FUNCTION_BLOCK "fb_53_startstopDiesel"
TITLE =Control of a Diesel engine (Start, Stop, auxiliary functions)
//Version!Date    !Author !Segment    ! Description
//-------+--------+-------+-----------+-------------------------------
// 1.3   !07.04.00!Bauch  ! ---       ! Last valid version
// 1.4   !09.05.00!Kahle  ! 50        ! Shore conn on ->stop with load redu
// 1.5   !17.05.00!Kahle  ! 79        ! store failure "engine failure"
// 1.6   !15.09.00!Kahle  ! 49        ! stop if shore on in semi also
//       !        !       ! 50        ! stop if shore on with soft unload
//       !        !       ! 51        ! stop if shore on without soft unload
// 1.7   !16.12.00!Bauch  ! 65, new66 ! Generator breaker trip command
// 1.8   !03.01.01!Kahle  !27,28,29,74! monitoring prelub.press while start
//       !        !       !22,23,29   !
//       !        !       !22         ! corr. prelub. befor start
// 1.9   !11.01.01!Bauch  ! 8         ! Add. prelubrication in all modes
//       !        !       ! 12,24     ! Signal #stat_DG_Running moved from 12->24
// 1.10  !20.01.01!Bauch  ! 76        ! No blocking by signal "#out_Fail_Stop"
// 1.11  !24.01.01!Bauch  ! 29        ! Prelubrication before start
//       !        !       ! 27-->24   ! Prelubrication failure
//       !        !       ! 37        ! New signal "#stat_StartStep3Out"
//       !        !       ! 85        ! Function for "Start & Prelub"
//       !        !       ! Deklar.   ! Naming of "in_PrelubPress_Low",
//       !        !       !           ! "in_PrelubPress_OK"
// 1.12  !26.01.01!Bauch  ! new 90    ! Indication "Rated speed" for OP7
//       !        !       !           ! New variable "in_DI_RatedSpeed"
// 1.13  !31.01.01!Bauch  ! 22        ! Prelubrication Off with disappearing
//       !        !       !           ! of start request
// 1.14  !14.02.01!Kahle  ! 42        ! Delay time "volt.missing" adjustable
//       !        !       ! 45(new)   ! Create "delay stop pulse"
//       !        !       ! 80        ! Correction "engine available"
//       !        !       ! 82        ! Correction "creating engine failure"
// 1.15  !12.03.01!Kahle  ! 56        ! No cool down in case of delayed shutdown
// 2.0   !02.01.02!Kahle  ! 9-25,29,74! Prelubrication functionality is changed
//       !        !       ! 75        !
//       !        !       ! 52        ! Diesel stop in semiIMAC if CB open only
//       !        !       ! 77 ->29   ! Blocking criterion segment changed
//       !        !       ! 78        ! Out_blocked if diesel stopped only
//       !        !       ! 73        ! del.
//       !        !       !92-94 ->88f! move segm.92-94 ->88ff
//       !        !       ! 79        ! Standstill instead of standstill_delayed
AUTHOR : Bauch
FAMILY : PMA71
NAME : DiesCont
VERSION : 2.0
CODE_VERSION1


VAR_INPUT
  in_Nmb_Gen_LoadSh : INT ;	//Number of other generators, taking part in loadsharing
  in_act_mode : BYTE ;	//Active operation mode
  in_EG_set : BOOL ;	//Generator is an emergency generator
  in_DG_Start : BOOL ;	//Diesel generator start command
  in_DG_Stop : BOOL ;	//Diesel generator stop command
  in_UndelayStop : BOOL ;	//Diesel undelayed stop command (from diesel/generator protection, etc.)
  in_DelayStop : BOOL ;	//Diesel delayed stop command (from diesel/generator protection, etc.)
  in_EmergencyStop : BOOL ;	//Diesel emergency stop command
  in_Underload_Limit : BOOL ;	//Load below limit for underload shutdown
  in_Autom_Stop : BOOL ;	//Automatik stop (e.g. Underload shutdown command)
  in_Shore_Stop : BOOL ;	//Automatik stop from shore connection/external program
  in_DG_Load_Off : BOOL ;	//Load value below the diesel stop limit (->stop after manual load reduction)
  in_DI_GenBrk_FB_On : BOOL ;	//Feedback signal generator breaker is ON
  in_DI_GenBrk_FB_Off : BOOL ;	//Feedback signal generator breaker is OFF (for stop release)
  in_DI_IgnitionSpeed : BOOL ;	//Ignition speed
  in_DI_RatedSpeed : BOOL ;	//Rated speed
  in_GenVolt_avail : BOOL ;	//Generator voltage available (Standard: >85%)
  in_MonitTime1 : BOOL ;	//Monitoring time 1
  in_DG_Block_Engine : BOOL ;	//Diesel engine blocked (signal from engine/local panel; "1"=blocked)
  in_DG_Blocking : BOOL ;	//Conditions for blocking of diesel generator
  in_Blocking_Reset : BOOL ;	//Blocking reset
  in_LubPress : BOOL ;	//Lubrication oil pressure available
  in_PrelubPress : BOOL ;	//Lubrication oil pressure available
  in_DRelStdby : BOOL ;	//Release standby function
  in_Blackout : BOOL ;	//Blackout
  in_NoWireBrk_StartValve : BOOL ;	//No wire breakage start valve (digital input)
  in_NoWireBrk_StopValve : BOOL ;	//No wire breakage stop valve (digital input)
  in_NoWireBrk_EmStopValve : BOOL ;	//No wire breakage emergency stop valve (digital input)
  in_NoWireBrk_SupprValve : BOOL ;	//No wire breakage suppression valve (digital input)
  in_Reset : BOOL ;	//Reset
END_VAR
VAR_OUTPUT
  out_Operat_Status : INT ;	//Actual operational status (as number)
  out_StartValve : BOOL ;	//Start valve
  out_StopValve : BOOL ;	//Stop valve
  out_EmStpValve : BOOL ;	//Emergency stop valve
  out_SupprValve : BOOL ;	//Suppression valve
  out_Release_SpeedContr : BOOL ;	//Release of speed controller
  out_PreLub : BOOL ;	//Prelubrication
  out_PreHeat : BOOL ;	//Preheating
  out_SlowTurn : BOOL ;	//Slow Turn
  out_StandbyStart : BOOL ;	//Request of standby start
  out_ChOver_Semi : BOOL ;	//Forced change over from automatic to semi automatic mode
  out_GenBrkOff_LoadRed : BOOL ;	//Generator breaker Off after load reduction (Off after P < Limit)
  out_GenBrkOff : BOOL ;	//Generator breaker Off command (without previous load reduction)
  out_GenBrkTrip : BOOL ;	//Generator breaker trip command
  out_DG_Blocked_Fault : BOOL ;	//Diesel generator blocked by fault
  out_DG_Blocked : BOOL ;	//Diesel generator blocked
  out_DG_Starting : BOOL ;	//Diesel generator starting
  out_DG_Runn : BOOL ;	//Diesel generator running
  out_DG_Avail : BOOL ;	//Diesel generator available
  out_Fail_Start : BOOL ;	//Start failure
  out_Fail_Stop : BOOL ;	//Stop failure
  out_Fail_IgnSpd : BOOL ;	//Signal "Ignition speed" missing, but "Gen. voltage available"
  out_Fail_GenVolt : BOOL ;	//Signal "Gen. voltage available" missing, but "Ignition speed"
  out_Fail_UndelayStop : BOOL ;	//Indication "Undelayed stop"
  out_Fail_DelayStop : BOOL ;	//Indication "Delayed stop"
  out_Fail_DieselEngine : BOOL ;	//Indication "Diesel engine failure"
  out_Fail_PrelubOil : BOOL ;	//Indication "Low prelubrication oil pressure" (Diesel engine start blocking)
  out_Fail_LubOil : BOOL ;	//Indication "Low lubrication oil pressure"
  out_Fail_WBr_StartValve : BOOL ;	//Indication "Wire breakage start valve"
  out_Fail_WBr_StopValve : BOOL ;	//Indication "Wire breakage stop valve"
  out_Fail_WBr_EmStopValve : BOOL ;	//Indication "Wire breakage emergency stop valve"
  out_Fail_WBr_SuppValve : BOOL ;	//Indication "Wire breakage suppression valve"
END_VAR
VAR
  stat_CountStAtt : INT ;	//Down-counter for start attempts
  stat_Nmb_Gen_LoadSh_Old : INT ;	//Number of other generators, taking part in loadsharing (old value)
  stat_CntValue01 : INT ;	//Memory for FC100 (timer/counter) No. 01 (Prelubr. before start necessary)
  stat_CntValue02 : INT ;	//Memory for FC100 (timer/counter) No. 02 (Prelub bef. start, prelub time)
  stat_CntValue03 : INT ;	//Memory for FC100 (timer/counter) No. 03 (Suppression valve)
  stat_CntValue04 : INT ;	//Memory for FC100 (timer/counter) No. 04 (Stopping time after ign. speed Off)
  stat_CntValue05 : INT ;	//Memory for FC100 (timer/counter) No. 05 (Time for delayed shutdown)
  stat_CntValue06 : INT ;	//Memory for FC100 (timer/counter) No. 06 (Cool down time)
  stat_CntValue07 : INT ;	//Memory for FC100 (timer/counter) No. 07 (Time for load reduction)
  stat_CntValue08 : INT ;	//Memory for FC100 (timer/counter) No. 08 (p_TManLoadRed)
  stat_CntValue09 : INT ;	//Memory for FC100 (timer/counter) No. 09 (Failure Ign. speed missing)
  stat_CntValue10 : INT ;	//Memory for FC100 (timer/counter) No. 10 (Failure Gen. voltage missing)
  stat_CntValue11 : INT ;	//Memory for FC100 (timer/counter) No. 11 (Low prelub oil press.)
  stat_CntValue12 : INT ;	//Memory for FC100 (timer/counter) No. 12 (Ignition speed is Off)
  stat_CntValue13 : INT ;	//Memory for FC100 (timer/counter) No. 13 (Wire breakage start valve)
  stat_CntValue14 : INT ;	//Memory for FC100 (timer/counter) No. 14 (Wire breakage stop valve)
  stat_CntValue15 : INT ;	//Memory for FC100 (timer/counter) No. 15 (Wire breakage emergency stop valve)
  stat_CntValue16 : INT ;	//Memory for FC100 (timer/counter) No. 16 (Wire breakage suppression valve)
  stat_CntValue17 : INT ;	//Memory for FC100 (timer/counter) No. 17 (Monitoring time for stop failure)
  stat_CntValue18 : INT ;	//Memory for FC100 (timer/counter) No. 18 (Waiting time before diesel start)
  stat_CntValue19 : INT ;	//Memory for FC100 (timer/counter) No. 19 (Monitoring time luboil after start)
  stat_CntStart01 : BOOL ;	//Memory for FC100 (timer/counter) No. 01
  stat_CntStarted01 : BOOL ;	//Memory for FC100 (timer/counter) No. 01
  stat_CntStart02 : BOOL ;	//Memory for FC100 (timer/counter) No. 02
  stat_CntStarted02 : BOOL ;	//Memory for FC100 (timer/counter) No. 02
  stat_CntStart03 : BOOL ;	//Memory for FC100 (timer/counter) No. 03
  stat_CntStarted03 : BOOL ;	//Memory for FC100 (timer/counter) No. 03
  stat_CntStart04 : BOOL ;	//Memory for FC100 (timer/counter) No. 04
  stat_CntStarted04 : BOOL ;	//Memory for FC100 (timer/counter) No. 04
  stat_CntStart05 : BOOL ;	//Memory for FC100 (timer/counter) No. 05
  stat_CntStarted05 : BOOL ;	//Memory for FC100 (timer/counter) No. 05
  stat_CntStart06 : BOOL ;	//Memory for FC100 (timer/counter) No. 06
  stat_CntStarted06 : BOOL ;	//Memory for FC100 (timer/counter) No. 06
  stat_CntStart07 : BOOL ;	//Memory for FC100 (timer/counter) No. 07
  stat_CntStarted07 : BOOL ;	//Memory for FC100 (timer/counter) No. 07
  stat_CntStart08 : BOOL ;	//Memory for FC100 (timer/counter) No. 08
  stat_CntStarted08 : BOOL ;	//Memory for FC100 (timer/counter) No. 08
  stat_CntStart09 : BOOL ;	//Memory for FC100 (timer/counter) No. 09
  stat_CntStarted09 : BOOL ;	//Memory for FC100 (timer/counter) No. 09
  stat_CntStart10 : BOOL ;	//Memory for FC100 (timer/counter) No. 10
  stat_CntStarted10 : BOOL ;	//Memory for FC100 (timer/counter) No. 10
  stat_CntStart11 : BOOL ;	//Memory for FC100 (timer/counter) No. 11
  stat_CntStarted11 : BOOL ;	//Memory for FC100 (timer/counter) No. 11
  stat_CntStart12 : BOOL ;	//Memory for FC100 (timer/counter) No. 12
  stat_CntStarted12 : BOOL ;	//Memory for FC100 (timer/counter) No. 12
  stat_CntStart13 : BOOL ;	//Memory for FC100 (timer/counter) No. 13
  stat_CntStarted13 : BOOL ;	//Memory for FC100 (timer/counter) No. 13
  stat_CntStart14 : BOOL ;	//Memory for FC100 (timer/counter) No. 14
  stat_CntStarted14 : BOOL ;	//Memory for FC100 (timer/counter) No. 14
  stat_CntStart15 : BOOL ;	//Memory for FC100 (timer/counter) No. 15
  stat_CntStarted15 : BOOL ;	//Memory for FC100 (timer/counter) No. 15
  stat_CntStart16 : BOOL ;	//Memory for FC100 (timer/counter) No. 16
  stat_CntStarted16 : BOOL ;	//Memory for FC100 (timer/counter) No. 16
  stat_CntStart17 : BOOL ;	//Memory for FC100 (timer/counter) No. 17
  stat_CntStarted17 : BOOL ;	//Memory for FC100 (timer/counter) No. 17
  stat_CntStart18 : BOOL ;	//Memory for FC100 (timer/counter) No. 18
  stat_CntStarted18 : BOOL ;	//Memory for FC100 (timer/counter) No. 18
  stat_CntStart19 : BOOL ;	//Memory for FC100 (timer/counter) No. 19
  stat_CntStarted19 : BOOL ;	//Memory for FC100 (timer/counter) No. 19
  stat_StartRequ : BOOL ;	//Diesel start request
  stat_StartBegin : BOOL ;	//Diesel start beginning
  stat_StartBegPulse : BOOL ;	//Diesel start beginning, pulse 0-->1
  stat_StartStep1Out : BOOL ;	//Diesel start, step 1 output (intermediate step)
  stat_StartStep1Fin : BOOL ;	//Diesel start, step 1 finished (intermediate step)
  stat_StartStep2Cond : BOOL ;	//Diesel start, condition for step 2 (start valve active)
  stat_StartStep2Fin : BOOL ;	//Diesel start, step 2 finished (start valve active)
  stat_StartValve : BOOL ;	//Start valve active
  stat_StartStep3Out : BOOL ;	//Diesel start, step 3 output (pause between start attempts)
  stat_StartStep3Fin : BOOL ;	//Diesel start, step 3 finished (pause between start attempts)
  stat_DG_Stop : BOOL ;	//Diesel generator stop command
  stat_DelayStopRequ_Latch : BOOL ;	//Diesel delayed stop request (caused by a failure), latch
  stat_DelayStop_TimeEx : BOOL ;	//Diesel delayed stop, time expired
  stat_Standby_Conn : BOOL ;	//New started standby set has been connected to the busbar, pulse
  stat_Stop_Shore : BOOL ;	//Automatic stop from shore connection/external program
  stat_StopLoadRed_Latch : BOOL ;	//Diesel stop request with previous load reduction, latch
  stat_StopNoLoadRed_Latch : BOOL ;	//Diesel stop request without previous load reduction, latch
  stat_Stop_CoolDown : BOOL ;	//Diesel stop request, engine running for cool down
  stat_Stop_CoolDownEx : BOOL ;	//Diesel stop request, after time for cool down has expired
  stat_Stop_EG_NoLoadRun : BOOL ;	//Diesel stop request, with previous cool down/no load run function (for EG)
  stat_Stop_BreakOff : BOOL ;	//Diesel stop request, after time for generator breaker Off has expired
  stat_StopRequ_Pulse : BOOL ;	//Diesel stop request, pulse
  stat_StopRequ_Latch : BOOL ;	//Diesel stop request, latch
  stat_StopDelay : BOOL ;	//Diesel stop command delayed Off after "Ignition speed" and "Gen. volt." is Off
  stat_StopGoing : BOOL ;	//Diesel stop procedure going on
  stat_DG_Standstill : BOOL ;	//Diesel engine standstill
  stat_DG_Standstill_Delay : BOOL ;	//Diesel engine standstill, Off-delayed
  stat_DiesStarting_Aux : BOOL ;	//Diesel engine starting, auxiliary
  stat_DiesStarting_Pulse : BOOL ;	//Diesel engine starting, pulse
  stat_DG_Running : BOOL ;	//Diesel generator running ("Ignition speed" or "Generator voltage" present)
  stat_DG_Block_Fault : BOOL ;	//Diesel engine blocked by fault
  stat_PreLAct : BOOL ;	//Prelubrication active (Standby, Auto, etc.)
  stat_PreLContMode : BOOL ;	//Mode with constant prelubrication active
  stat_PreLCyclMode : BOOL ;	//Mode with cyclic prelubrication active
  stat_PreLStartMode : BOOL ;	//Mode with prelubrication before diesel start active
  stat_PreLContOn : BOOL ;	//Constant prelubrication On
  stat_PreLCyclOn : BOOL ;	//Cyclic prelubrication On
  stat_PreLPump : BOOL ;	//Prelubrication pump running also after diesel start
  stat_PreLCyStep0Cond : BOOL ;	//Cyclic prelubrication, condition for sequence start
  stat_PreLCyStep1 : BOOL ;	//Cyclic prelubrication, condition for step 1 (intermediate step)
  stat_PreLCyStep1Fin : BOOL ;	//Cyclic prelubrication, step 1 finished (intermediate step)
  stat_PreLCyStep2Cond : BOOL ;	//Cyclic prelubrication, condition for step 2 (pause)
  stat_PreLCyStep2Fin : BOOL ;	//Cyclic prelubrication, step 2 finished (pause)
  stat_PreLCyStep3Out : BOOL ;	//Cyclic prelubrication, step 3 output (prelubrication)
  stat_PreLCyStep3Fin : BOOL ;	//Cyclic prelubrication, step 3 finished (intermediate step)
  stat_PreLStNBegin : BOOL ;	//Prelubrication before start necessity, delay time starts
  stat_PreLStNReady : BOOL ;	//Prelubrication before start necessity, prelubrication necessary
  stat_PreLStBegin : BOOL ;	//Prelubrication before start beginning
  stat_PreLlowPress : BOOL ;	//Prelubrication: failure low pressure (time exceeded)
  stat_SuppValvRequOff : BOOL ;	//Suppression valve, delayed Off request
  stat_PrelPress_Delay : BOOL ;	//"Low prelubrication oil pressure", time delayed
  stat_PrelPress_Blocking : BOOL ;	//Diesel engine blocking, caused by "Low prelubrication oil pressure"
  stat_IgnSpeedOff_Delay : BOOL ;	//Signal "Ignition speed is Off", time delayed
  stat_IgnSpeedOff_Aux : BOOL ;	//Auxiliary flag for pulse "Ignition speed is Off"
  stat_Fail_DieselEngine : BOOL ;	//Memory: Engine failure
  stat_DG_Running2 : BOOL ;	//Memory: Engine running
  stat_DelayStop : BOOL ;	//Pulse delay stop
  stat_failLubPress : BOOL ;	//Failure Lubrication pressure after start
END_VAR
VAR_TEMP
  temp_OM_Local : BOOL ;	//Active operation mode: Local
  temp_OM_Semi_OP : BOOL ;	//Active operation mode: Semi automatic OP
  temp_OM_Auto_OP : BOOL ;	//Active operation mode: Auto OP
  temp_OM_Semi_MMI : BOOL ;	//Active operation mode: Semi automatic MMI
  temp_OM_Auto_MMI : BOOL ;	//Active operation mode: Auto MMI
  temp_OM_Test : BOOL ;	//Active operation mode: Test (EG only)
  temp_Reserve_006 : BOOL ;	//Reserved (Transfer Byte --> Bit)
  temp_Reserve_007 : BOOL ;	//Reserved (Transfer Byte --> Bit)
  temp_Auto : BOOL ;	//Active operation mode: Auto
  temp_Semi : BOOL ;	//Active operation mode: Semi automatic
  temp_ScratchFlag : BOOL ;	//Scratch flag
  temp_StartStep2Fin : BOOL ;	//Diesel start, step 2 finished (start valve active)
  temp_StartStep3Fin : BOOL ;	//Diesel start, step 3 finished (pause between start attempts)
  temp_Standby_Start : BOOL ;	//Standby start command
  temp_lastSet : BOOL ;	//This set is the last one in load balance
  temp_automLoadRed : BOOL ;	//Mode "Automatic load reduction" is active
  temp_manLoadRed : BOOL ;	//Mode "Manual load reduction" is active
  temp_Fail_Stop : BOOL ;	//Stop failure
  temp_Fail_PreLub : BOOL ;	//Prelubrication failure
  temp_Pls_DelayStop : BOOL ;	//positive pulse delay stop
  temp_DelayStop : BOOL ;	//delay stop activated
  temp_PreLub : BOOL ;	//prelubrication is activated
  temp_startDiesel : BOOL ;	//start diesel if prelubrication time is exceeded
END_VAR
BEGIN
NETWORK
TITLE =Active operation mode (Transfer Byte --> Bit)
//This transfer function is relaying on the relative addresses of the "temp"
//variables "temp_OM_Local" ... "temp_OM_Auto" in the area from 0.0 ... 0.7.
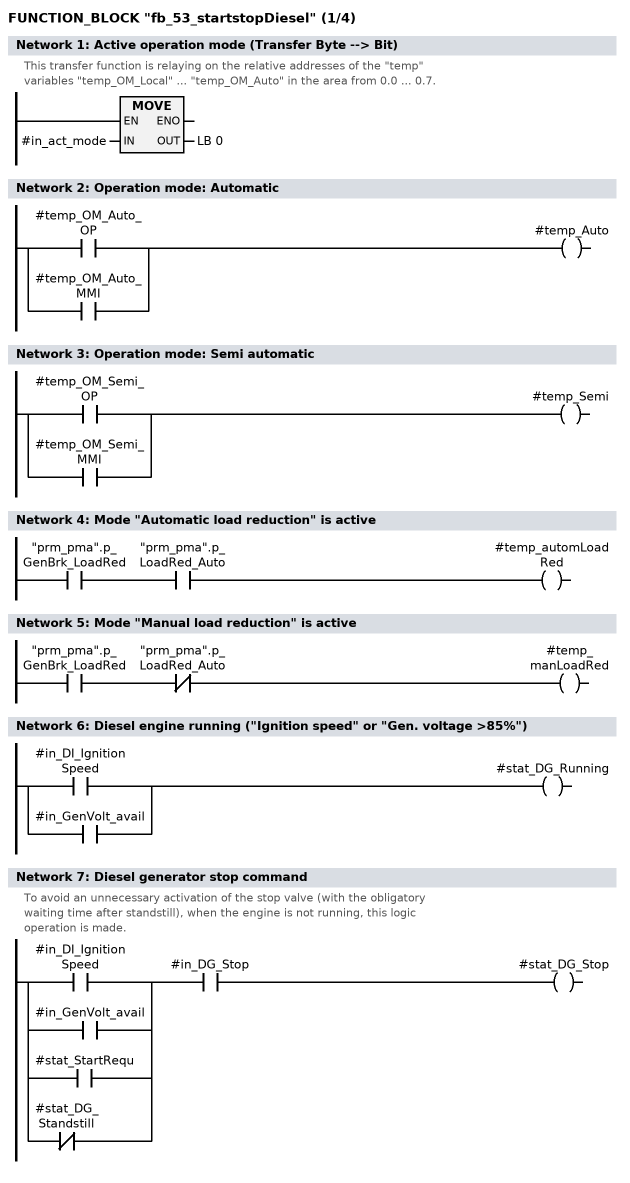
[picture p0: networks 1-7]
      L     #in_act_mode;
      T     LB     0;
NETWORK
TITLE =Operation mode: Automatic

      O     #temp_OM_Auto_OP;
      O     #temp_OM_Auto_MMI;
      =     #temp_Auto;
NETWORK
TITLE =Operation mode: Semi automatic

      O     #temp_OM_Semi_OP;
      O     #temp_OM_Semi_MMI;
      =     #temp_Semi;
NETWORK
TITLE =Mode "Automatic load reduction" is active

      U     "prm_pma".p_GenBrk_LoadRed;
      U     "prm_pma".p_LoadRed_Auto;
      =     #temp_automLoadRed;
NETWORK
TITLE =Mode "Manual load reduction" is active

      U     "prm_pma".p_GenBrk_LoadRed;
      UN    "prm_pma".p_LoadRed_Auto;
      =     #temp_manLoadRed;
NETWORK
TITLE =Diesel engine running ("Ignition speed" or "Gen. voltage >85%")

      O     #in_DI_IgnitionSpeed;
      O     #in_GenVolt_avail;
      =     #stat_DG_Running;
NETWORK
TITLE =Diesel generator stop command
//To avoid an unnecessary activation of the stop valve (with the obligatory
//waiting time after standstill), when the engine is not running, this logic
//operation is made.
      U(    ;
      O     #in_DI_IgnitionSpeed;
      O     #in_GenVolt_avail;
      O     #stat_StartRequ;
      ON    #stat_DG_Standstill;
      )     ;
      U     #in_DG_Stop;
      =     #stat_DG_Stop;
NETWORK
TITLE =Prelubrication active (with standby, auto, etc.)

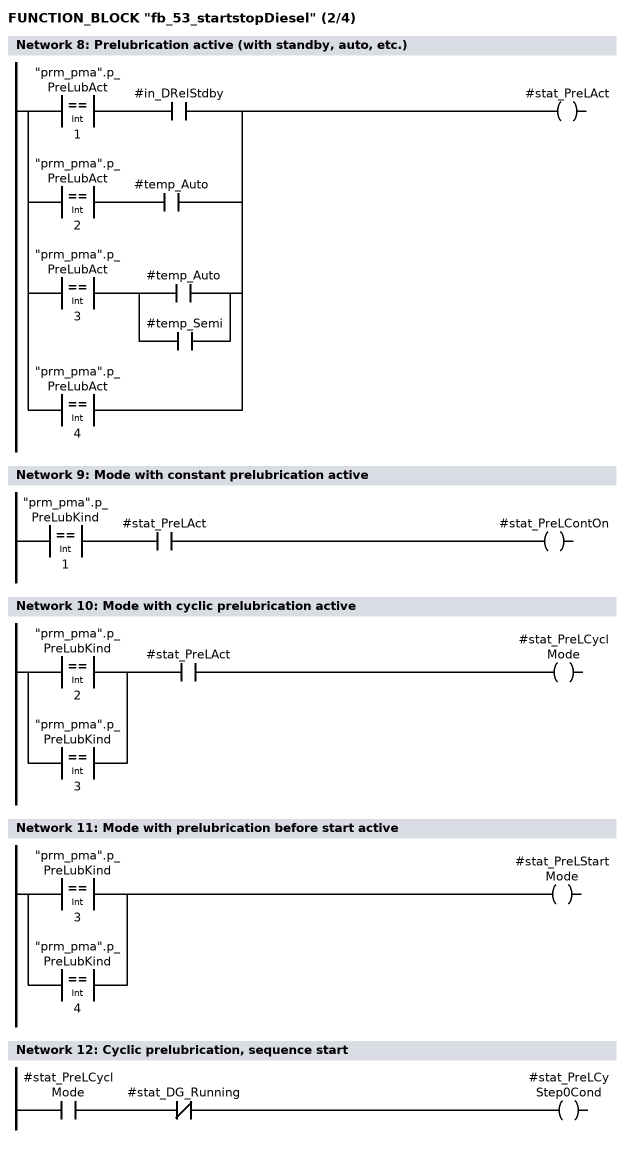
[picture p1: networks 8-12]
      U(    ;
      L     "prm_pma".p_PreLubAct;
      L     1;
      ==I   ;
      )     ;
      U     #in_DRelStdby;
      O     ;
      U(    ;
      L     "prm_pma".p_PreLubAct;
      L     2;
      ==I   ;
      )     ;
      U     #temp_Auto;
      O     ;
      U(    ;
      L     "prm_pma".p_PreLubAct;
      L     3;
      ==I   ;
      )     ;
      U(    ;
      O     #temp_Auto;
      O     #temp_Semi;
      )     ;
      O(    ;
      L     "prm_pma".p_PreLubAct;
      L     4;
      ==I   ;
      )     ;
      =     #stat_PreLAct;
NETWORK
TITLE =Mode with constant prelubrication active

      U(    ;
      L     "prm_pma".p_PreLubKind;
      L     1;
      ==I   ;
      )     ;
      U     #stat_PreLAct;
      =     #stat_PreLContOn;
NETWORK
TITLE =Mode with cyclic prelubrication active

      U(    ;
      O(    ;
      L     "prm_pma".p_PreLubKind;
      L     2;
      ==I   ;
      )     ;
      O(    ;
      L     "prm_pma".p_PreLubKind;
      L     3;
      ==I   ;
      )     ;
      )     ;
      U     #stat_PreLAct;
      =     #stat_PreLCyclMode;
NETWORK
TITLE =Mode with prelubrication before start active

      O(    ;
      L     "prm_pma".p_PreLubKind;
      L     3;
      ==I   ;
      )     ;
      O(    ;
      L     "prm_pma".p_PreLubKind;
      L     4;
      ==I   ;
      )     ;
      =     #stat_PreLStartMode;
NETWORK
TITLE =Cyclic prelubrication, sequence start

      U     #stat_PreLCyclMode;
      UN    #stat_DG_Running;
      =     #stat_PreLCyStep0Cond;
NETWORK
TITLE =NW13 -17: Cyclic prelubrication, sequence start
//The sequence starts with the stopping of the engine ("Ignition speed" and
//"Generator voltage" Off), when cyclic prelubrication is selected.
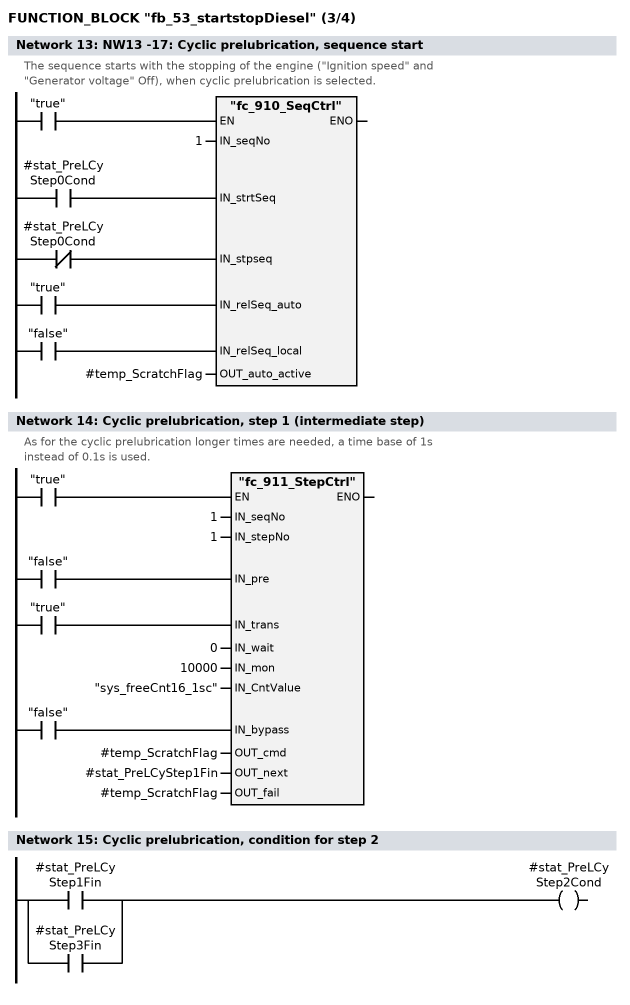
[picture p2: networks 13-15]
      U     #stat_PreLCyStep0Cond;
      =     L      3.0;
      BLD   103;
      UN    #stat_PreLCyStep0Cond;
      =     L      3.1;
      BLD   103;
      U     "true";
      =     L      3.2;
      BLD   103;
      U     "false";
      =     L      3.3;
      BLD   103;
      U     "true";
      SPBNB _00b;
      CALL "fc_910_SeqCtrl" (
           IN_seqNo                 := 1,
           IN_strtSeq               := L      3.0,
           IN_stpseq                := L      3.1,
           IN_relSeq_auto           := L      3.2,
           IN_relSeq_local          := L      3.3,
           OUT_auto_active          := #temp_ScratchFlag);
_00b: NOP   0;
NETWORK
TITLE =Cyclic prelubrication, step 1 (intermediate step)
//As for the cyclic prelubrication longer times are needed, a time base of 1s
//instead of 0.1s is used.
      U     "false";
      =     L      3.0;
      BLD   103;
      U     "true";
      =     L      3.1;
      BLD   103;
      U     "false";
      =     L      3.2;
      BLD   103;
      U     "true";
      SPBNB _00f;
      CALL "fc_911_StepCtrl" (
           IN_seqNo                 := 1,
           IN_stepNo                := 1,
           IN_pre                   := L      3.0,
           IN_trans                 := L      3.1,
           IN_wait                  := 0,
           IN_mon                   := 10000,
           IN_CntValue              := "sys_freeCnt16_1sc",
           IN_bypass                := L      3.2,
           OUT_cmd                  := #temp_ScratchFlag,
           OUT_next                 := #stat_PreLCyStep1Fin,
           OUT_fail                 := #temp_ScratchFlag);
_00f: NOP   0;
NETWORK
TITLE =Cyclic prelubrication, condition for step 2

      O     #stat_PreLCyStep1Fin;
      O     #stat_PreLCyStep3Fin;
      =     #stat_PreLCyStep2Cond;
NETWORK
TITLE =Cyclic prelubrication, step 2 (pause)
//As for the cyclic prelubrication longer times are needed, a time base of 1s
//instead of 0.1s is used.
//
//During standstill of the diesel engine the sequence moves between steps 2 and
//3.
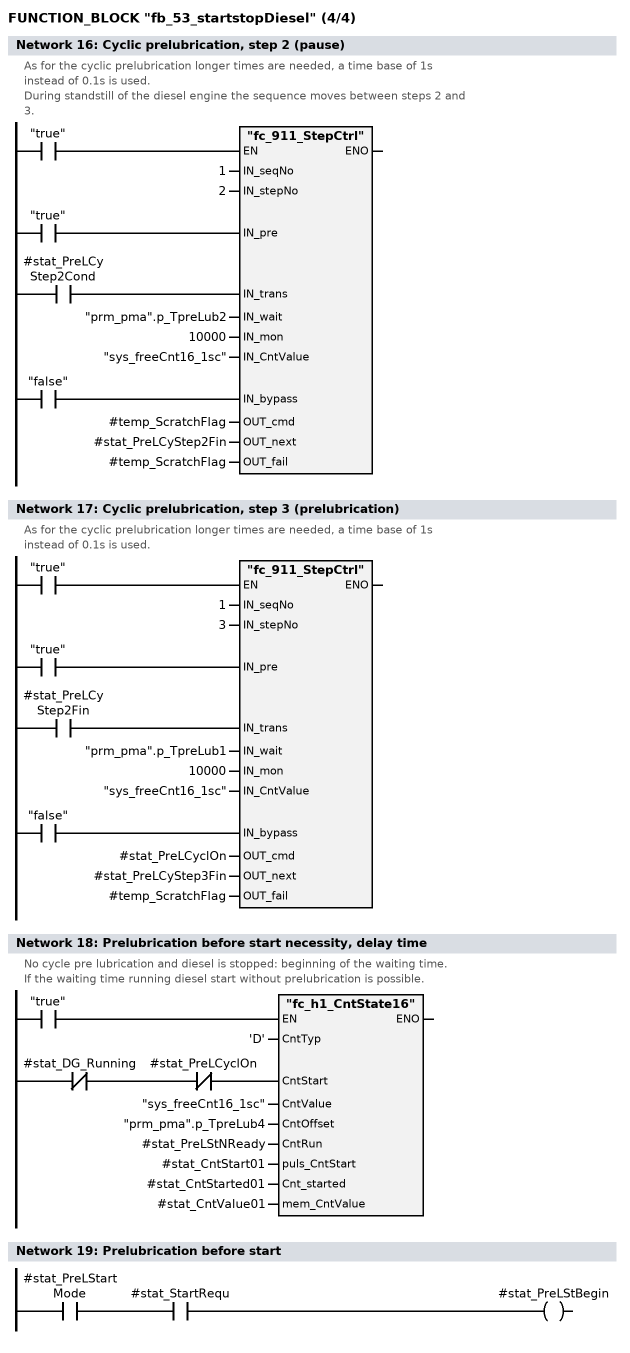
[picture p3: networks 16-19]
      U     "true";
      =     L      3.0;
      BLD   103;
      U     #stat_PreLCyStep2Cond;
      =     L      3.1;
      BLD   103;
      U     "false";
      =     L      3.2;
      BLD   103;
      U     "true";
      SPBNB _013;
      CALL "fc_911_StepCtrl" (
           IN_seqNo                 := 1,
           IN_stepNo                := 2,
           IN_pre                   := L      3.0,
           IN_trans                 := L      3.1,
           IN_wait                  := "prm_pma".p_TpreLub2,
           IN_mon                   := 10000,
           IN_CntValue              := "sys_freeCnt16_1sc",
           IN_bypass                := L      3.2,
           OUT_cmd                  := #temp_ScratchFlag,
           OUT_next                 := #stat_PreLCyStep2Fin,
           OUT_fail                 := #temp_ScratchFlag);
_013: NOP   0;
NETWORK
TITLE =Cyclic prelubrication, step 3 (prelubrication)
//As for the cyclic prelubrication longer times are needed, a time base of 1s
//instead of 0.1s is used.
      U     "true";
      =     L      3.0;
      BLD   103;
      U     #stat_PreLCyStep2Fin;
      =     L      3.1;
      BLD   103;
      U     "false";
      =     L      3.2;
      BLD   103;
      U     "true";
      SPBNB _01c;
      CALL "fc_911_StepCtrl" (
           IN_seqNo                 := 1,
           IN_stepNo                := 3,
           IN_pre                   := L      3.0,
           IN_trans                 := L      3.1,
           IN_wait                  := "prm_pma".p_TpreLub1,
           IN_mon                   := 10000,
           IN_CntValue              := "sys_freeCnt16_1sc",
           IN_bypass                := L      3.2,
           OUT_cmd                  := #stat_PreLCyclOn,
           OUT_next                 := #stat_PreLCyStep3Fin,
           OUT_fail                 := #temp_ScratchFlag);
_01c: NOP   0;
NETWORK
TITLE =Prelubrication before start necessity, delay time
//No cycle pre lubrication and diesel is stopped: beginning of the waiting time.
//If the waiting time running diesel start without prelubrication is possible.
      UN    #stat_DG_Running;
      UN    #stat_PreLCyclOn;
      =     L      3.0;
      BLD   103;
      U     "true";
      SPBNB _01d;
      CALL "fc_h1_CntState16" (
           CntTyp                   := 'D',
           CntStart                 := L      3.0,
           CntValue                 := "sys_freeCnt16_1sc",
           CntOffset                := "prm_pma".p_TpreLub4,
           CntRun                   := #stat_PreLStNReady,
           puls_CntStart            := #stat_CntStart01,
           Cnt_started              := #stat_CntStarted01,
           mem_CntValue             := #stat_CntValue01);
_01d: NOP   0;
NETWORK
TITLE =Prelubrication before start

      U     #stat_PreLStartMode;
      U     #stat_StartRequ;
      =     #stat_PreLStBegin;
NETWORK
TITLE =Prelubrication output

      U(    ;
      O     #stat_PreLContOn;
      O     ;
      U     #stat_PreLCyclOn;
      UN    #stat_PreLStNReady;
      O     #stat_PreLStBegin;
      )     ;
      UN    #stat_DG_Running;
      O(    ;
      U     #stat_PreLStBegin;
      U     "prm_pma".p_PrelubOil_Blackout;
      S     #stat_PreLPump;
      U(    ;
      O     #in_LubPress;
      O     #stat_PreLlowPress;
      O     #stat_failLubPress;
      )     ;
      R     #stat_PreLPump;
      U     #stat_PreLPump;
      )     ;
      =     #out_PreLub;
NETWORK
TITLE =Monitoring Prelubrication before start

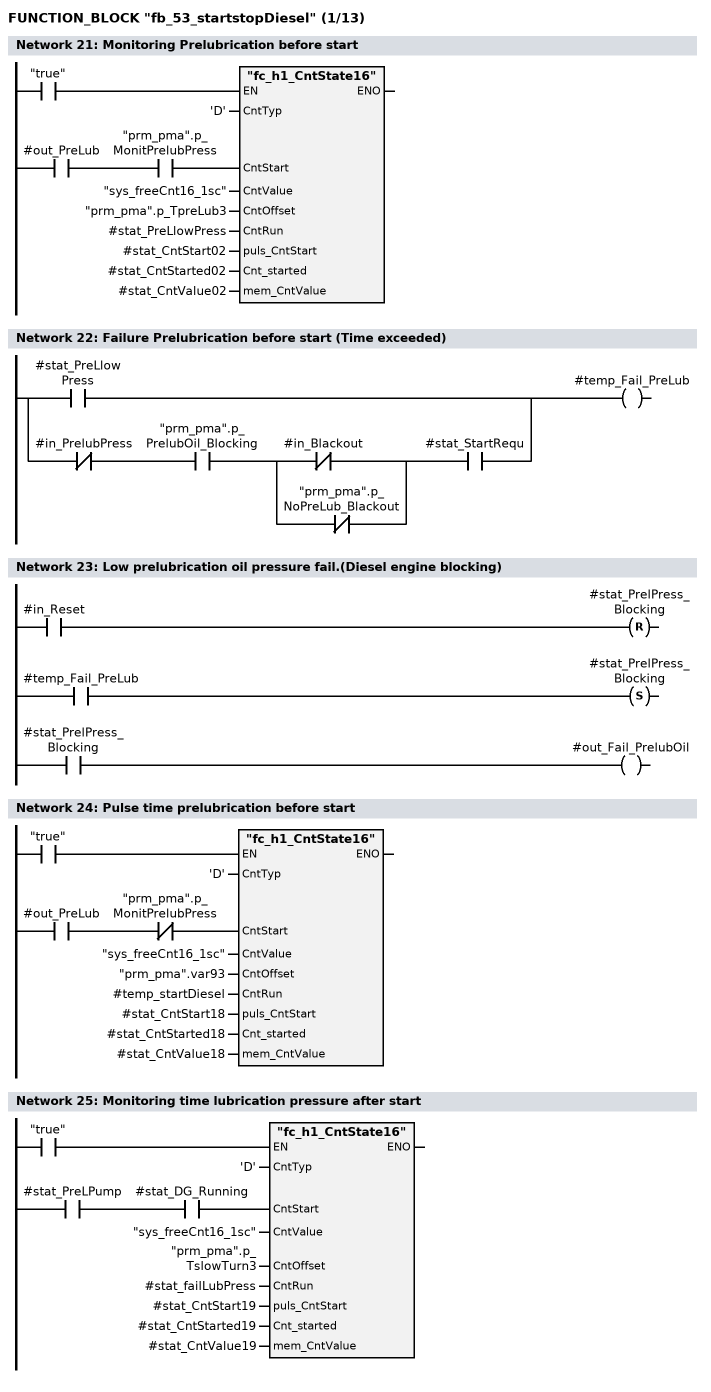
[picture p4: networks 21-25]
      U     #out_PreLub;
      U     "prm_pma".p_MonitPrelubPress;
      =     L      3.0;
      BLD   103;
      U     "true";
      SPBNB _01e;
      CALL "fc_h1_CntState16" (
           CntTyp                   := 'D',
           CntStart                 := L      3.0,
           CntValue                 := "sys_freeCnt16_1sc",
           CntOffset                := "prm_pma".p_TpreLub3,
           CntRun                   := #stat_PreLlowPress,
           puls_CntStart            := #stat_CntStart02,
           Cnt_started              := #stat_CntStarted02,
           mem_CntValue             := #stat_CntValue02);
_01e: NOP   0;
NETWORK
TITLE =Failure Prelubrication before start (Time exceeded)

      O     #stat_PreLlowPress;
      O     ;
      UN    #in_PrelubPress;
      U     "prm_pma".p_PrelubOil_Blocking;
      U(    ;
      ON    #in_Blackout;
      ON    "prm_pma".p_NoPreLub_Blackout;
      )     ;
      U     #stat_StartRequ;
      =     #temp_Fail_PreLub;
NETWORK
TITLE =Low prelubrication oil pressure fail.(Diesel engine blocking)

      U     #in_Reset;
      R     #stat_PrelPress_Blocking;
      U     #temp_Fail_PreLub;
      S     #stat_PrelPress_Blocking;
      U     #stat_PrelPress_Blocking;
      =     #out_Fail_PrelubOil;
NETWORK
TITLE =Pulse time prelubrication before start

      U     #out_PreLub;
      UN    "prm_pma".p_MonitPrelubPress;
      =     L      3.0;
      BLD   103;
      U     "true";
      SPBNB _01f;
      CALL "fc_h1_CntState16" (
           CntTyp                   := 'D',
           CntStart                 := L      3.0,
           CntValue                 := "sys_freeCnt16_1sc",
           CntOffset                := "prm_pma".var93,
           CntRun                   := #temp_startDiesel,
           puls_CntStart            := #stat_CntStart18,
           Cnt_started              := #stat_CntStarted18,
           mem_CntValue             := #stat_CntValue18);
_01f: NOP   0;
NETWORK
TITLE =Monitoring time lubrication pressure after start

      U     #stat_PreLPump;
      U     #stat_DG_Running;
      =     L      3.0;
      BLD   103;
      U     "true";
      SPBNB _022;
      CALL "fc_h1_CntState16" (
           CntTyp                   := 'D',
           CntStart                 := L      3.0,
           CntValue                 := "sys_freeCnt16_1sc",
           CntOffset                := "prm_pma".p_TslowTurn3,
           CntRun                   := #stat_failLubPress,
           puls_CntStart            := #stat_CntStart19,
           Cnt_started              := #stat_CntStarted19,
           mem_CntValue             := #stat_CntValue19);
_022: NOP   0;
NETWORK
TITLE =failure: low lubrication oil pressure

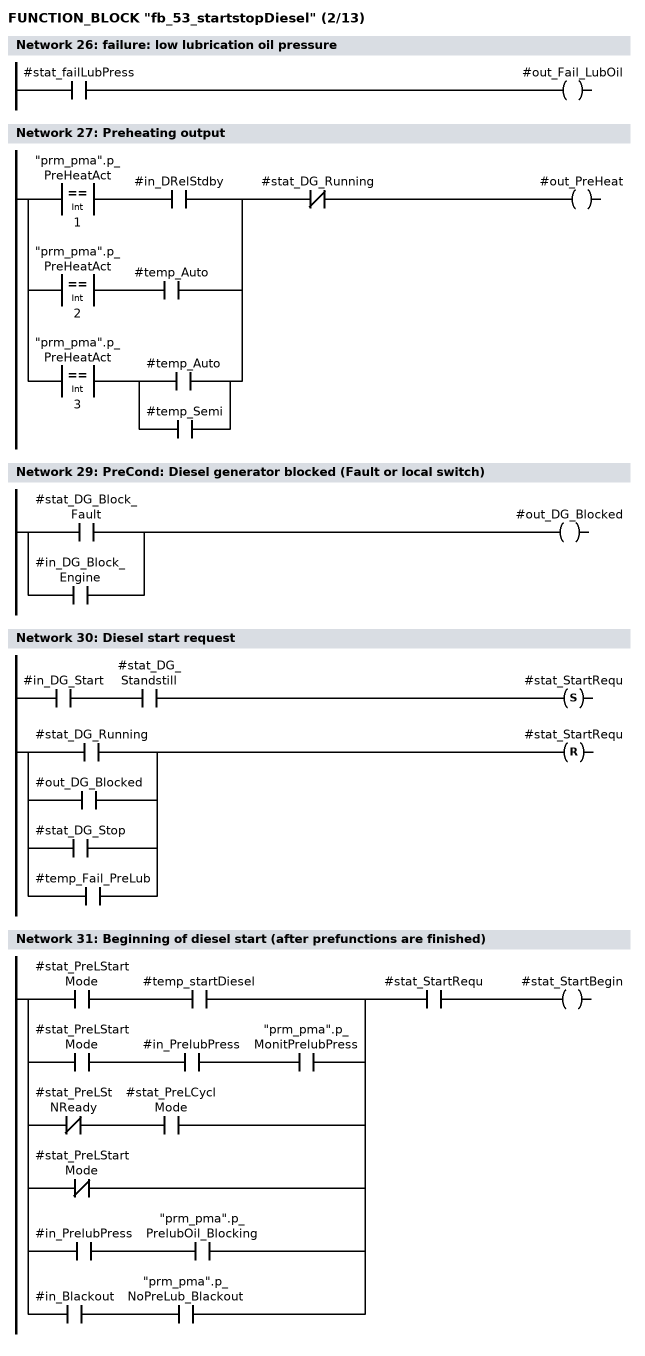
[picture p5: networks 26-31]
      U     #stat_failLubPress;
      =     #out_Fail_LubOil;
NETWORK
TITLE =Preheating output

      U(    ;
      U(    ;
      L     "prm_pma".p_PreHeatAct;
      L     1;
      ==I   ;
      )     ;
      U     #in_DRelStdby;
      O     ;
      U(    ;
      L     "prm_pma".p_PreHeatAct;
      L     2;
      ==I   ;
      )     ;
      U     #temp_Auto;
      O     ;
      U(    ;
      L     "prm_pma".p_PreHeatAct;
      L     3;
      ==I   ;
      )     ;
      U(    ;
      O     #temp_Auto;
      O     #temp_Semi;
      )     ;
      )     ;
      UN    #stat_DG_Running;
      =     #out_PreHeat;
NETWORK
TITLE =

NETWORK
TITLE =PreCond: Diesel generator blocked (Fault or local switch)

      O     #stat_DG_Block_Fault;
      O     #in_DG_Block_Engine;
      =     #out_DG_Blocked;
NETWORK
TITLE =Diesel start request

      U     #in_DG_Start;
      U     #stat_DG_Standstill;
      S     #stat_StartRequ;
      U(    ;
      O     #stat_DG_Running;
      O     #out_DG_Blocked;
      O     #stat_DG_Stop;
      O     #temp_Fail_PreLub;
      )     ;
      R     #stat_StartRequ;
      NOP   0;
NETWORK
TITLE =Beginning of diesel start (after prefunctions are finished)

      U(    ;
      U     #stat_PreLStartMode;
      U     #temp_startDiesel;
      O     ;
      U     #stat_PreLStartMode;
      U     #in_PrelubPress;
      U     "prm_pma".p_MonitPrelubPress;
      O     ;
      UN    #stat_PreLStNReady;
      U     #stat_PreLCyclMode;
      ON    #stat_PreLStartMode;
      O     ;
      U     #in_PrelubPress;
      U     "prm_pma".p_PrelubOil_Blocking;
      O     ;
      U     #in_Blackout;
      U     "prm_pma".p_NoPreLub_Blackout;
      )     ;
      U     #stat_StartRequ;
      =     #stat_StartBegin;
NETWORK
TITLE =Diesel start procedure, sequence start

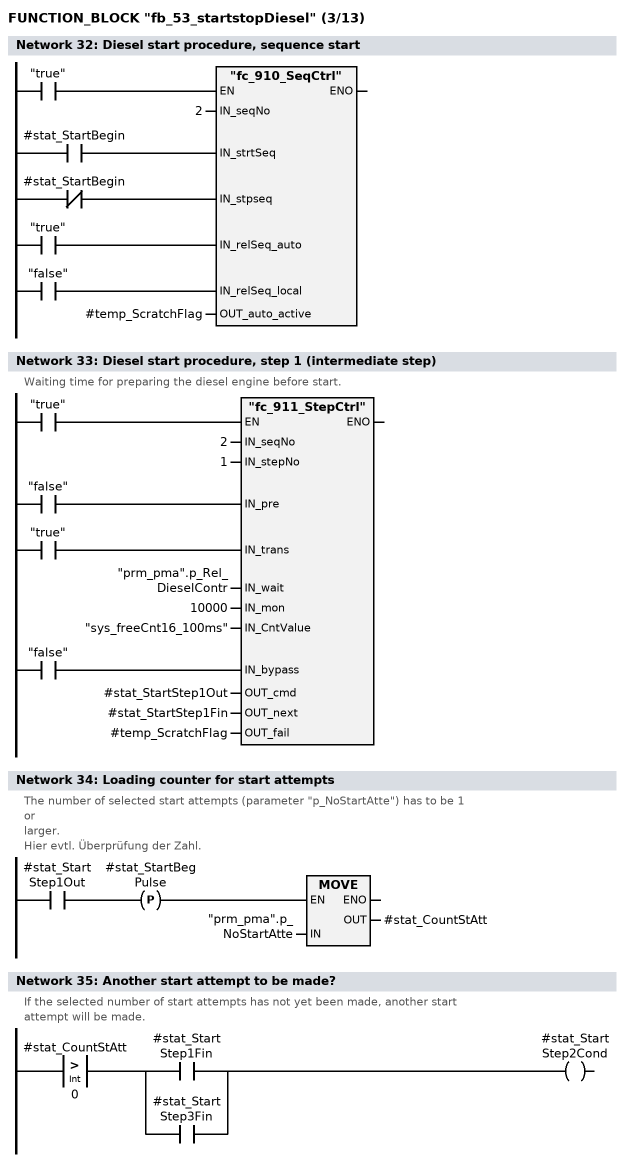
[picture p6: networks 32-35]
      U     #stat_StartBegin;
      =     L      3.0;
      BLD   103;
      UN    #stat_StartBegin;
      =     L      3.1;
      BLD   103;
      U     "true";
      =     L      3.2;
      BLD   103;
      U     "false";
      =     L      3.3;
      BLD   103;
      U     "true";
      SPBNB _02c;
      CALL "fc_910_SeqCtrl" (
           IN_seqNo                 := 2,
           IN_strtSeq               := L      3.0,
           IN_stpseq                := L      3.1,
           IN_relSeq_auto           := L      3.2,
           IN_relSeq_local          := L      3.3,
           OUT_auto_active          := #temp_ScratchFlag);
_02c: NOP   0;
NETWORK
TITLE =Diesel start procedure, step 1 (intermediate step)
//Waiting time for preparing the diesel engine before start.
      U     "false";
      =     L      3.0;
      BLD   103;
      U     "true";
      =     L      3.1;
      BLD   103;
      U     "false";
      =     L      3.2;
      BLD   103;
      U     "true";
      SPBNB _02d;
      CALL "fc_911_StepCtrl" (
           IN_seqNo                 := 2,
           IN_stepNo                := 1,
           IN_pre                   := L      3.0,
           IN_trans                 := L      3.1,
           IN_wait                  := "prm_pma".p_Rel_DieselContr,
           IN_mon                   := 10000,
           IN_CntValue              := "sys_freeCnt16_100ms",
           IN_bypass                := L      3.2,
           OUT_cmd                  := #stat_StartStep1Out,
           OUT_next                 := #stat_StartStep1Fin,
           OUT_fail                 := #temp_ScratchFlag);
_02d: NOP   0;
NETWORK
TITLE =Loading counter for start attempts
//The number of selected start attempts (parameter "p_NoStartAtte") has to be 1
//or
//larger.
//Hier evtl. Überprüfung der Zahl.
      U     #stat_StartStep1Out;
      FP    #stat_StartBegPulse;
      SPBNB _02e;
      L     "prm_pma".p_NoStartAtte;
      T     #stat_CountStAtt;
_02e: NOP   0;
NETWORK
TITLE =Another start attempt to be made?
//If the selected number of start attempts has not yet been made, another start
//attempt will be made.
      U(    ;
      L     #stat_CountStAtt;
      L     0;
      >I    ;
      )     ;
      U(    ;
      O     #stat_StartStep1Fin;
      O     #stat_StartStep3Fin;
      )     ;
      =     #stat_StartStep2Cond;
NETWORK
TITLE =Diesel start procedure, step 2 (start valve activated)

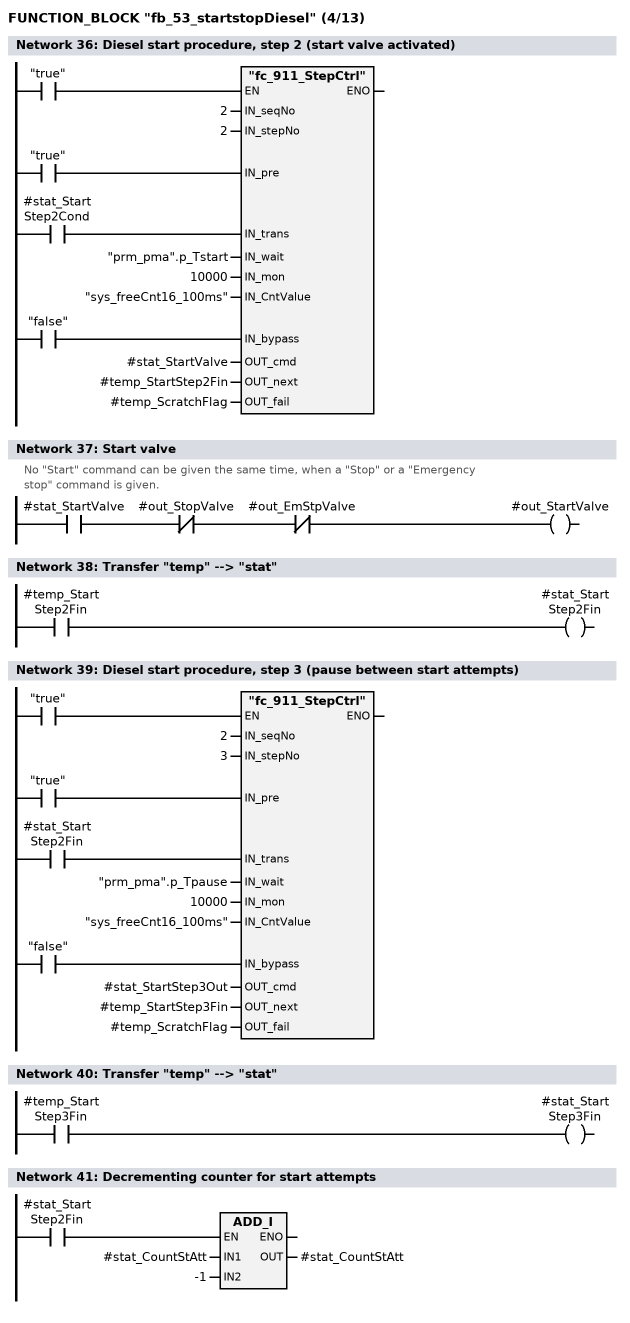
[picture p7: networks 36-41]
      U     "true";
      =     L      3.0;
      BLD   103;
      U     #stat_StartStep2Cond;
      =     L      3.1;
      BLD   103;
      U     "false";
      =     L      3.2;
      BLD   103;
      U     "true";
      SPBNB _02f;
      CALL "fc_911_StepCtrl" (
           IN_seqNo                 := 2,
           IN_stepNo                := 2,
           IN_pre                   := L      3.0,
           IN_trans                 := L      3.1,
           IN_wait                  := "prm_pma".p_Tstart,
           IN_mon                   := 10000,
           IN_CntValue              := "sys_freeCnt16_100ms",
           IN_bypass                := L      3.2,
           OUT_cmd                  := #stat_StartValve,
           OUT_next                 := #temp_StartStep2Fin,
           OUT_fail                 := #temp_ScratchFlag);
_02f: NOP   0;
NETWORK
TITLE =Start valve
//No "Start" command can be given the same time, when a "Stop" or a "Emergency
//stop" command is given.
      U     #stat_StartValve;
      UN    #out_StopValve;
      UN    #out_EmStpValve;
      =     #out_StartValve;
NETWORK
TITLE =Transfer "temp" --> "stat"

      U     #temp_StartStep2Fin;
      =     #stat_StartStep2Fin;
NETWORK
TITLE =Diesel start procedure, step 3 (pause between start attempts)

      U     "true";
      =     L      3.0;
      BLD   103;
      U     #stat_StartStep2Fin;
      =     L      3.1;
      BLD   103;
      U     "false";
      =     L      3.2;
      BLD   103;
      U     "true";
      SPBNB _037;
      CALL "fc_911_StepCtrl" (
           IN_seqNo                 := 2,
           IN_stepNo                := 3,
           IN_pre                   := L      3.0,
           IN_trans                 := L      3.1,
           IN_wait                  := "prm_pma".p_Tpause,
           IN_mon                   := 10000,
           IN_CntValue              := "sys_freeCnt16_100ms",
           IN_bypass                := L      3.2,
           OUT_cmd                  := #stat_StartStep3Out,
           OUT_next                 := #temp_StartStep3Fin,
           OUT_fail                 := #temp_ScratchFlag);
_037: NOP   0;
NETWORK
TITLE =Transfer "temp" --> "stat"

      U     #temp_StartStep3Fin;
      =     #stat_StartStep3Fin;
NETWORK
TITLE =Decrementing counter for start attempts

      U     #stat_StartStep2Fin;
      SPBNB _03b;
      L     #stat_CountStAtt;
      L     -1;
      +I    ;
      T     #stat_CountStAtt;
_03b: NOP   0;
NETWORK
TITLE =Start failure

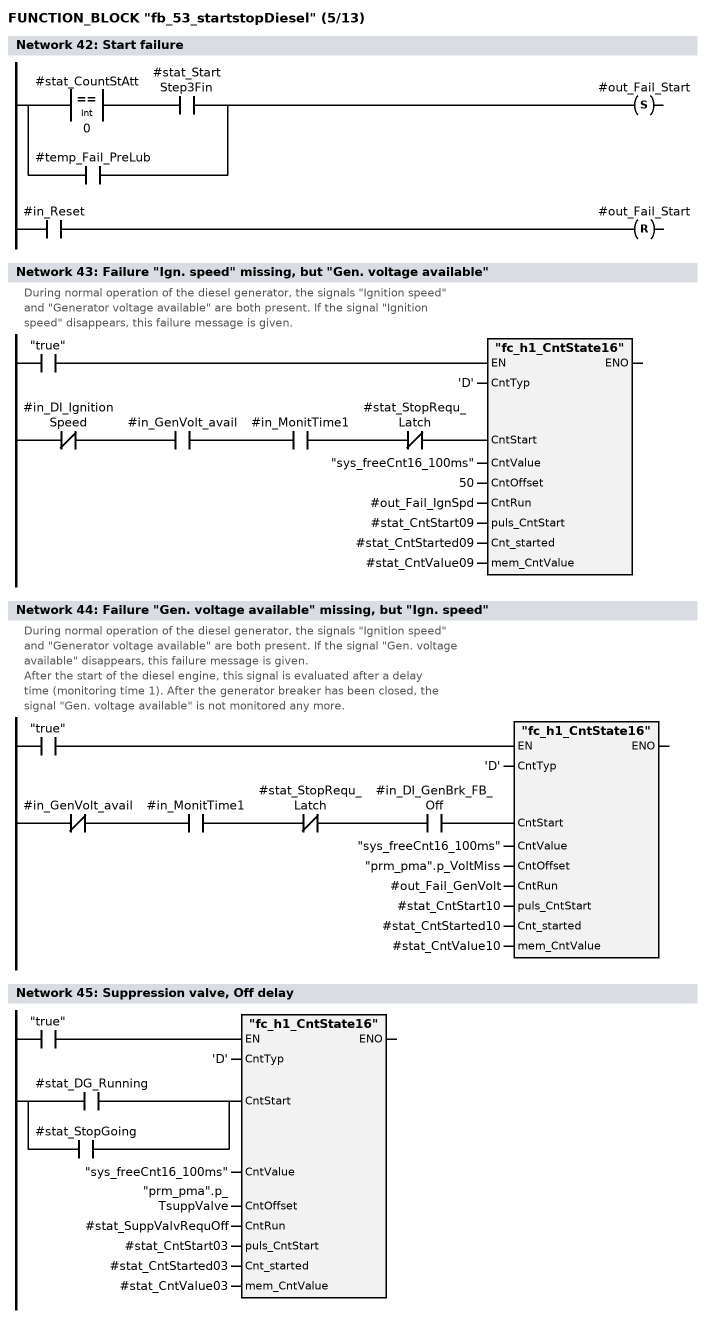
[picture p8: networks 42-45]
      U(    ;
      U(    ;
      L     #stat_CountStAtt;
      L     0;
      ==I   ;
      )     ;
      U     #stat_StartStep3Fin;
      O     #temp_Fail_PreLub;
      )     ;
      S     #out_Fail_Start;
      U     #in_Reset;
      R     #out_Fail_Start;
      NOP   0;
NETWORK
TITLE =Failure "Ign. speed" missing, but "Gen. voltage available"
//During normal operation of the diesel generator, the signals "Ignition speed"
//and "Generator voltage available" are both present. If the signal "Ignition
//speed" disappears, this failure message is given.
      UN    #in_DI_IgnitionSpeed;
      U     #in_GenVolt_avail;
      U     #in_MonitTime1;
      UN    #stat_StopRequ_Latch;
      =     L      3.0;
      BLD   103;
      U     "true";
      SPBNB _03f;
      CALL "fc_h1_CntState16" (
           CntTyp                   := 'D',
           CntStart                 := L      3.0,
           CntValue                 := "sys_freeCnt16_100ms",
           CntOffset                := 50,
           CntRun                   := #out_Fail_IgnSpd,
           puls_CntStart            := #stat_CntStart09,
           Cnt_started              := #stat_CntStarted09,
           mem_CntValue             := #stat_CntValue09);
_03f: NOP   0;
NETWORK
TITLE =Failure "Gen. voltage available" missing, but "Ign. speed"
//During normal operation of the diesel generator, the signals "Ignition speed"
//and "Generator voltage available" are both present. If the signal "Gen. voltage
//available" disappears, this failure message is given.
//
//After the start of the diesel engine, this signal is evaluated after a delay
//time (monitoring time 1). After the generator breaker has been closed, the
//signal "Gen. voltage available" is not monitored any more.
      UN    #in_GenVolt_avail;
      U     #in_MonitTime1;
      UN    #stat_StopRequ_Latch;
      U     #in_DI_GenBrk_FB_Off;
      =     L      3.0;
      BLD   103;
      U     "true";
      SPBNB _040;
      CALL "fc_h1_CntState16" (
           CntTyp                   := 'D',
           CntStart                 := L      3.0,
           CntValue                 := "sys_freeCnt16_100ms",
           CntOffset                := "prm_pma".p_VoltMiss,
           CntRun                   := #out_Fail_GenVolt,
           puls_CntStart            := #stat_CntStart10,
           Cnt_started              := #stat_CntStarted10,
           mem_CntValue             := #stat_CntValue10);
_040: NOP   0;
NETWORK
TITLE =Suppression valve, Off delay

      U(    ;
      O     #stat_DG_Running;
      O     #stat_StopGoing;
      )     ;
      =     L      3.0;
      BLD   103;
      U     "true";
      SPBNB _041;
      CALL "fc_h1_CntState16" (
           CntTyp                   := 'D',
           CntStart                 := L      3.0,
           CntValue                 := "sys_freeCnt16_100ms",
           CntOffset                := "prm_pma".p_TsuppValve,
           CntRun                   := #stat_SuppValvRequOff,
           puls_CntStart            := #stat_CntStart03,
           Cnt_started              := #stat_CntStarted03,
           mem_CntValue             := #stat_CntValue03);
_041: NOP   0;
NETWORK
TITLE =Suppression valve
//The suppression valve is active, when the diesel engine is not running, and is
//switched off with a delay time after the start of the engine.
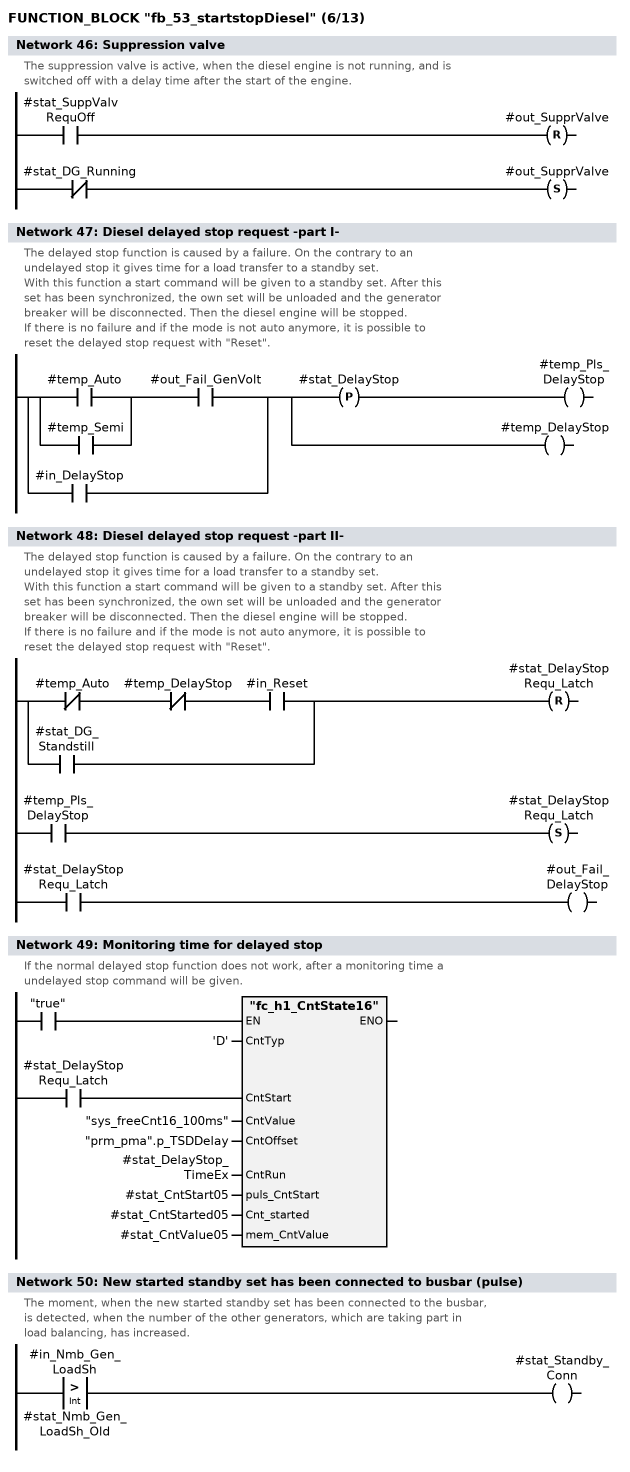
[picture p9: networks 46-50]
      U     #stat_SuppValvRequOff;
      R     #out_SupprValve;
      UN    #stat_DG_Running;
      S     #out_SupprValve;
      NOP   0;
NETWORK
TITLE =Diesel delayed stop request -part I-
//The delayed stop function is caused by a failure. On the contrary to an
//undelayed stop it gives time for a load transfer to a standby set.
//
//With this function a start command will be given to a standby set. After this
//set has been synchronized, the own set will be unloaded and the generator
//breaker will be disconnected. Then the diesel engine will be stopped.
//
//If there is no failure and if the mode is not auto anymore, it is possible to
//reset the delayed stop request with "Reset".
      U(    ;
      O     #temp_Auto;
      O     #temp_Semi;
      )     ;
      U     #out_Fail_GenVolt;
      O     #in_DelayStop;
      =     L      3.0;
      U     L      3.0;
      FP    #stat_DelayStop;
      =     #temp_Pls_DelayStop;
      U     L      3.0;
      BLD   102;
      =     #temp_DelayStop;
NETWORK
TITLE =Diesel delayed stop request -part II-
//The delayed stop function is caused by a failure. On the contrary to an
//undelayed stop it gives time for a load transfer to a standby set.
//
//With this function a start command will be given to a standby set. After this
//set has been synchronized, the own set will be unloaded and the generator
//breaker will be disconnected. Then the diesel engine will be stopped.
//
//If there is no failure and if the mode is not auto anymore, it is possible to
//reset the delayed stop request with "Reset".
      U(    ;
      UN    #temp_Auto;
      UN    #temp_DelayStop;
      U     #in_Reset;
      O     #stat_DG_Standstill;
      )     ;
      R     #stat_DelayStopRequ_Latch;
      U     #temp_Pls_DelayStop;
      S     #stat_DelayStopRequ_Latch;
      U     #stat_DelayStopRequ_Latch;
      =     #out_Fail_DelayStop;
NETWORK
TITLE =Monitoring time for delayed stop
//If the normal delayed stop function does not work, after a monitoring time a
//undelayed stop command will be given.
      U     #stat_DelayStopRequ_Latch;
      =     L      3.0;
      BLD   103;
      U     "true";
      SPBNB _042;
      CALL "fc_h1_CntState16" (
           CntTyp                   := 'D',
           CntStart                 := L      3.0,
           CntValue                 := "sys_freeCnt16_100ms",
           CntOffset                := "prm_pma".p_TSDDelay,
           CntRun                   := #stat_DelayStop_TimeEx,
           puls_CntStart            := #stat_CntStart05,
           Cnt_started              := #stat_CntStarted05,
           mem_CntValue             := #stat_CntValue05);
_042: NOP   0;
NETWORK
TITLE =New started standby set has been connected to busbar (pulse)
//The moment, when the new started standby set has been connected to the busbar,
//is detected, when the number of the other generators, which are taking part in
//load balancing, has increased.
      L     #in_Nmb_Gen_LoadSh;
      L     #stat_Nmb_Gen_LoadSh_Old;
      >I    ;
      =     #stat_Standby_Conn;
NETWORK
TITLE =Number of generators, transfer new --> old

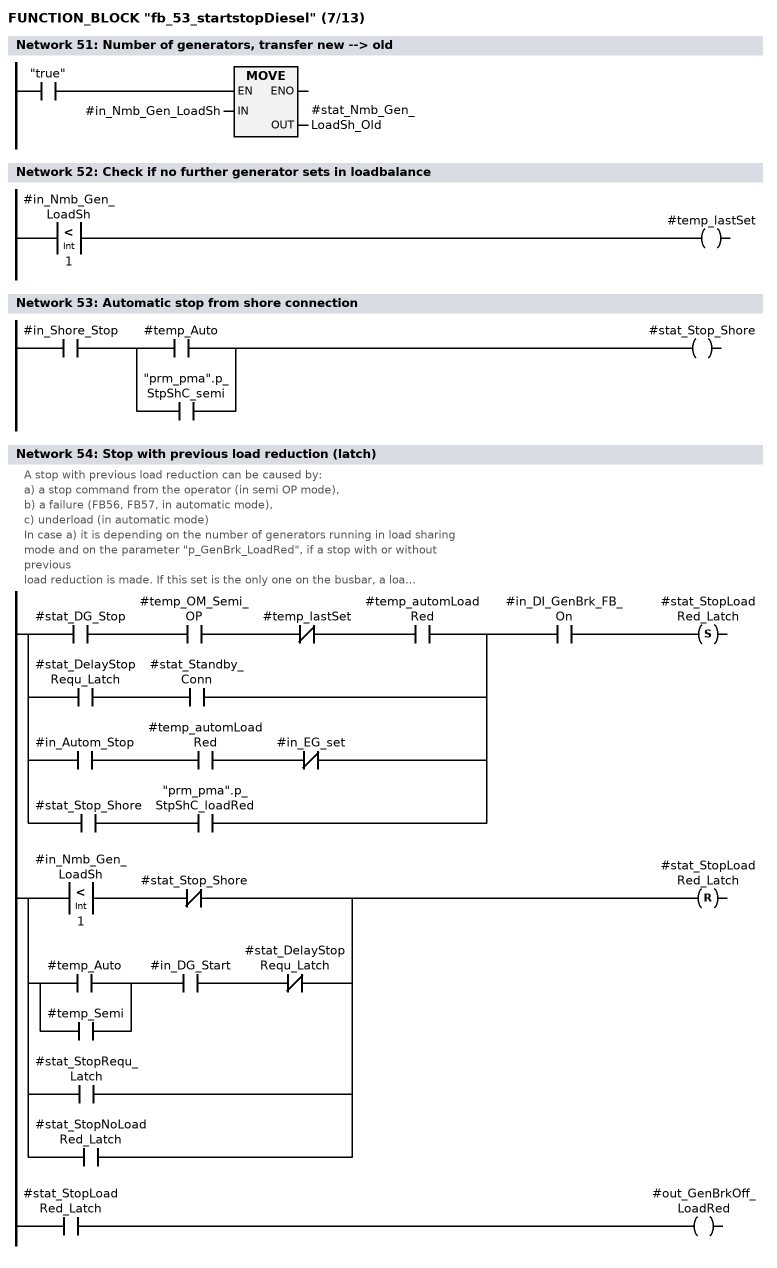
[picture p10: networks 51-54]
      U     "true";
      SPBNB _043;
      L     #in_Nmb_Gen_LoadSh;
      T     #stat_Nmb_Gen_LoadSh_Old;
_043: NOP   0;
NETWORK
TITLE =Check if no further generator sets in loadbalance

      L     #in_Nmb_Gen_LoadSh;
      L     1;
      <I    ;
      =     #temp_lastSet;
NETWORK
TITLE =Automatic stop from shore connection

      U     #in_Shore_Stop;
      U(    ;
      O     #temp_Auto;
      O     "prm_pma".p_StpShC_semi;
      )     ;
      =     #stat_Stop_Shore;
NETWORK
TITLE =Stop with previous load reduction (latch)
//A stop with previous load reduction can be caused by:
//a) a stop command from the operator (in semi OP mode),
//b) a failure (FB56, FB57, in automatic mode),
//c) underload (in automatic mode)
//
//In case a) it is depending on the number of generators running in load sharing
//mode and on the parameter "p_GenBrk_LoadRed", if a stop with or without
//previous
//load reduction is made. If this set is the only one on the busbar, a load
//transfer is not possible, and the generator breaker is tripped without load
//reduction.
//
//Depending on the parameter "p_NoLoadRun" (Running without load for cooling down
//before stopping the engine, 0= No, 1= Yes), in all cases the engine will be
//stopped, after the generator has been unloaded and the generator breaker has
//been opened or it will run without load for cooling down for some time.
//
//In case b) however, the engine will run not longer than preselected by the time
//"p_TSDDelay" (monitoring time for delayed stop). After this the engine will be
//stopped.
//=========================================================================
//Setzen u.a. mit: Verzögert Stopp, Unterlast, Fernstopp, Hand-Stopp
//   Hand-Stopp abhängig vom eingestellten Mode (ohne oder mit Entlastung)
//   Aktivierung durch verzögert Stopp erst nach Impuls "neues Aggr. auf Schiene"
//Rücksetzen u.a. mit: Kein anderes Aggr. auf Sammelschiene, neue Anforderung
      U(    ;
      U     #stat_DG_Stop;
      U     #temp_OM_Semi_OP;
      UN    #temp_lastSet;
      U     #temp_automLoadRed;
      O     ;
      U     #stat_DelayStopRequ_Latch;
      U     #stat_Standby_Conn;
      O     ;
      U     #in_Autom_Stop;
      U     #temp_automLoadRed;
      UN    #in_EG_set;
      O     ;
      U     #stat_Stop_Shore;
      U     "prm_pma".p_StpShC_loadRed;
      )     ;
      U     #in_DI_GenBrk_FB_On;
      S     #stat_StopLoadRed_Latch;
      U(    ;
      U(    ;
      L     #in_Nmb_Gen_LoadSh;
      L     1;
      <I    ;
      )     ;
      UN    #stat_Stop_Shore;
      O     ;
      U(    ;
      O     #temp_Auto;
      O     #temp_Semi;
      )     ;
      U     #in_DG_Start;
      UN    #stat_DelayStopRequ_Latch;
      O     #stat_StopRequ_Latch;
      O     #stat_StopNoLoadRed_Latch;
      )     ;
      R     #stat_StopLoadRed_Latch;
      U     #stat_StopLoadRed_Latch;
      =     #out_GenBrkOff_LoadRed;
NETWORK
TITLE =Stop without previous load reduction (latch)
//A stop without previous load reduction can be caused by:
//a) a stop command from the operator (in semi OP mode),
//b) a stop command in semi MMI mode,
//c) the time for the load reduction has expired
//d) the generator breaker is Off
//
//In case a) it is depending on the number of generators running in load sharing
//mode and on the parameter "p_GenBrk_LoadRed", if a stop with or without previous
//
//load reduction is made. If this generator set is the only one on the busbar, a
//load transfer is not possible, and the generator breaker is tripped without
//previous load reduction.
//
//Depending on the parameter "p_NoLoadRun" (Running without load for cooling down
//before stopping the engine, 0= No, 1= Yes), in all cases the engine will be
//stopped, after the generator has been unloaded and the generator breaker has
//been opened or it will run without load for cooling down for some time.
//
//=========================================================================
//Setzen u.a. mit: Verzögert Stopp, Unterlast, Fernstopp, Hand-Stopp
//   Hand-Stopp abhängig vom eingestellten Mode (ohne oder mit Entlastung)
//   Aktivierung durch verzögert Stopp erst nach Impuls "neues Aggr. auf Schiene"
//Rücksetzen u.a. mit: Kein anderes Aggr. auf Sammelschiene, neue Anforderung
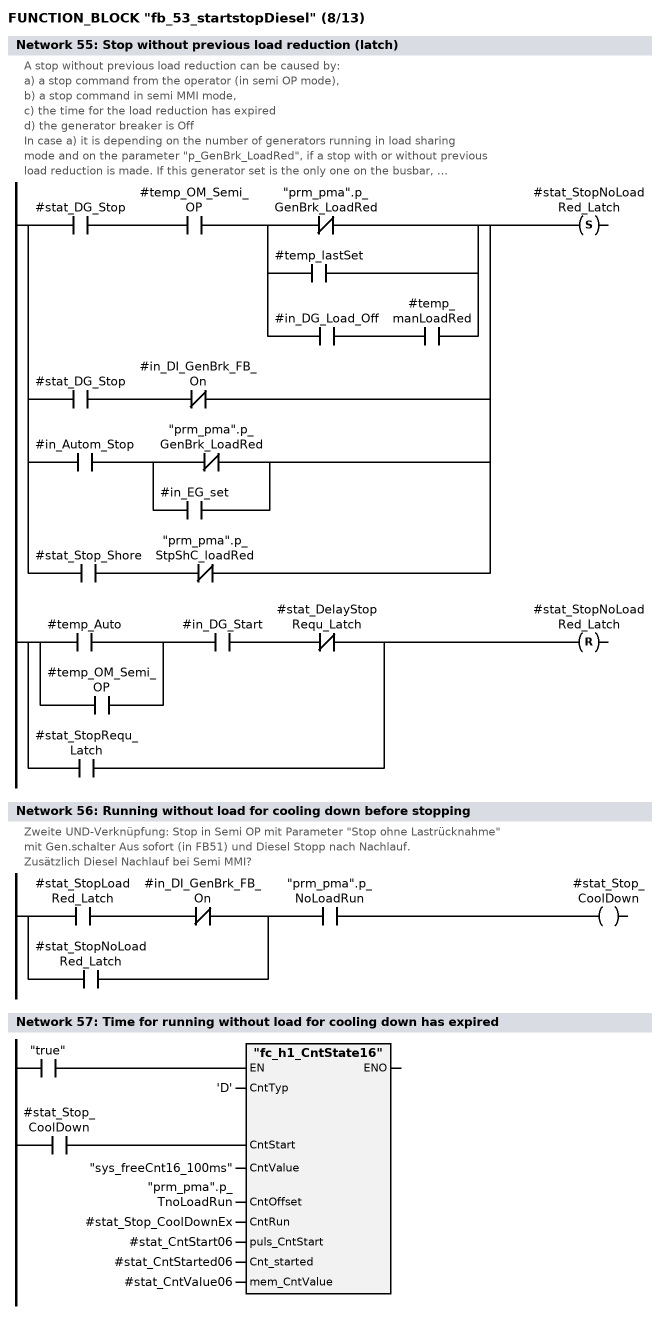
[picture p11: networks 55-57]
      U(    ;
      U     #stat_DG_Stop;
      U     #temp_OM_Semi_OP;
      U(    ;
      ON    "prm_pma".p_GenBrk_LoadRed;
      O     #temp_lastSet;
      O     ;
      U     #in_DG_Load_Off;
      U     #temp_manLoadRed;
      )     ;
      O     ;
      U     #stat_DG_Stop;
      UN    #in_DI_GenBrk_FB_On;
      O     ;
      U     #in_Autom_Stop;
      U(    ;
      ON    "prm_pma".p_GenBrk_LoadRed;
      O     #in_EG_set;
      )     ;
      O     ;
      U     #stat_Stop_Shore;
      UN    "prm_pma".p_StpShC_loadRed;
      )     ;
      S     #stat_StopNoLoadRed_Latch;
      U(    ;
      U(    ;
      O     #temp_Auto;
      O     #temp_OM_Semi_OP;
      )     ;
      U     #in_DG_Start;
      UN    #stat_DelayStopRequ_Latch;
      O     #stat_StopRequ_Latch;
      )     ;
      R     #stat_StopNoLoadRed_Latch;
      NOP   0;
NETWORK
TITLE =Running without load for cooling down before stopping
//Zweite UND-Verknüpfung: Stop in Semi OP mit Parameter "Stop ohne Lastrücknahme"
//mit Gen.schalter Aus sofort (in FB51) und Diesel Stopp nach Nachlauf.
//Zusätzlich Diesel Nachlauf bei Semi MMI?
      U(    ;
      U     #stat_StopLoadRed_Latch;
      UN    #in_DI_GenBrk_FB_On;
      O     #stat_StopNoLoadRed_Latch;
      )     ;
      U     "prm_pma".p_NoLoadRun;
      =     #stat_Stop_CoolDown;
NETWORK
TITLE =Time for running without load for cooling down has expired

      U     #stat_Stop_CoolDown;
      =     L      3.0;
      BLD   103;
      U     "true";
      SPBNB _056;
      CALL "fc_h1_CntState16" (
           CntTyp                   := 'D',
           CntStart                 := L      3.0,
           CntValue                 := "sys_freeCnt16_100ms",
           CntOffset                := "prm_pma".p_TnoLoadRun,
           CntRun                   := #stat_Stop_CoolDownEx,
           puls_CntStart            := #stat_CntStart06,
           Cnt_started              := #stat_CntStarted06,
           mem_CntValue             := #stat_CntValue06);
_056: NOP   0;
NETWORK
TITLE =Diesel stop valve

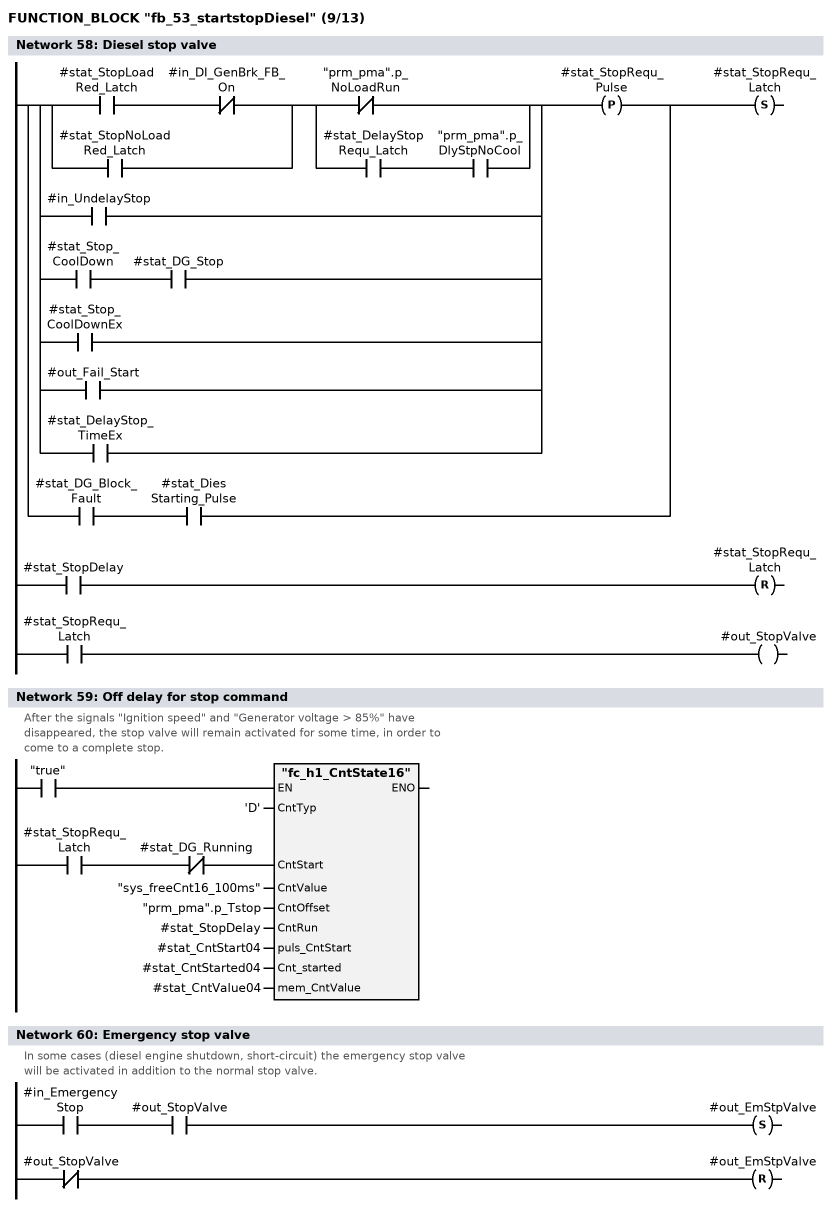
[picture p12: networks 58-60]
      U(    ;
      U(    ;
      U(    ;
      U     #stat_StopLoadRed_Latch;
      UN    #in_DI_GenBrk_FB_On;
      O     #stat_StopNoLoadRed_Latch;
      )     ;
      U(    ;
      ON    "prm_pma".p_NoLoadRun;
      O     ;
      U     #stat_DelayStopRequ_Latch;
      U     "prm_pma".p_DlyStpNoCool;
      )     ;
      O     #in_UndelayStop;
      O     ;
      U     #stat_Stop_CoolDown;
      U     #stat_DG_Stop;
      O     #stat_Stop_CoolDownEx;
      O     #out_Fail_Start;
      O     #stat_DelayStop_TimeEx;
      )     ;
      FP    #stat_StopRequ_Pulse;
      O     ;
      U     #stat_DG_Block_Fault;
      U     #stat_DiesStarting_Pulse;
      )     ;
      S     #stat_StopRequ_Latch;
      U     #stat_StopDelay;
      R     #stat_StopRequ_Latch;
      U     #stat_StopRequ_Latch;
      =     #out_StopValve;
NETWORK
TITLE =Off delay for stop command
//After the signals "Ignition speed" and "Generator voltage > 85%" have
//disappeared, the stop valve will remain activated for some time, in order to
//come to a complete stop.
      U     #stat_StopRequ_Latch;
      UN    #stat_DG_Running;
      =     L      3.0;
      BLD   103;
      U     "true";
      SPBNB _057;
      CALL "fc_h1_CntState16" (
           CntTyp                   := 'D',
           CntStart                 := L      3.0,
           CntValue                 := "sys_freeCnt16_100ms",
           CntOffset                := "prm_pma".p_Tstop,
           CntRun                   := #stat_StopDelay,
           puls_CntStart            := #stat_CntStart04,
           Cnt_started              := #stat_CntStarted04,
           mem_CntValue             := #stat_CntValue04);
_057: NOP   0;
NETWORK
TITLE =Emergency stop valve
//In some cases (diesel engine shutdown, short-circuit) the emergency stop valve
//will be activated in addition to the normal stop valve.
      U     #in_EmergencyStop;
      U     #out_StopValve;
      S     #out_EmStpValve;
      UN    #out_StopValve;
      R     #out_EmStpValve;
      NOP   0;
NETWORK
TITLE =Stop failure
//When the signals "Ignition speed" and "Generator voltage" do not disappear
//within a certain time after the begin of the stop command, it seems, that the
//engine is not able to stop and that there is something wrong.
//
//The stop command itself will be given for some time after the signals "Ignition
//speed" and "Generator voltage" have disappeared and if they do not disappear,
//permanently.
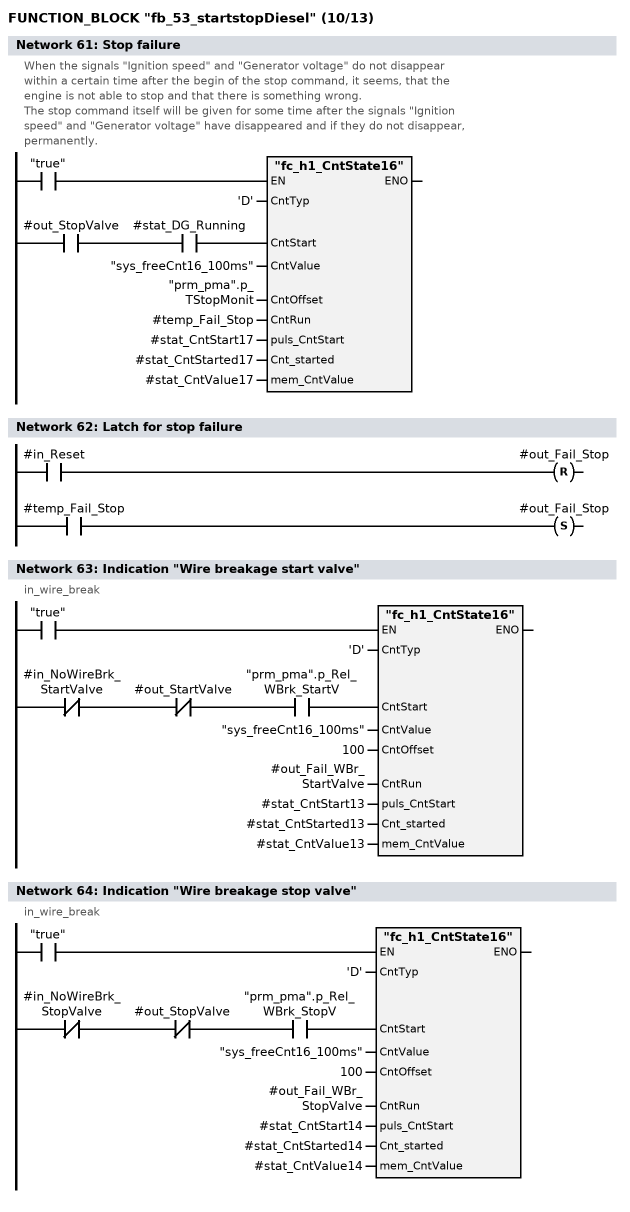
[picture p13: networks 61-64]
      U     #out_StopValve;
      U     #stat_DG_Running;
      =     L      3.0;
      BLD   103;
      U     "true";
      SPBNB _058;
      CALL "fc_h1_CntState16" (
           CntTyp                   := 'D',
           CntStart                 := L      3.0,
           CntValue                 := "sys_freeCnt16_100ms",
           CntOffset                := "prm_pma".p_TStopMonit,
           CntRun                   := #temp_Fail_Stop,
           puls_CntStart            := #stat_CntStart17,
           Cnt_started              := #stat_CntStarted17,
           mem_CntValue             := #stat_CntValue17);
_058: NOP   0;
NETWORK
TITLE =Latch for stop failure

      U     #in_Reset;
      R     #out_Fail_Stop;
      U     #temp_Fail_Stop;
      S     #out_Fail_Stop;
      NOP   0;
NETWORK
TITLE =Indication "Wire breakage start valve"
//in_wire_break
      UN    #in_NoWireBrk_StartValve;
      UN    #out_StartValve;
      U     "prm_pma".p_Rel_WBrk_StartV;
      =     L      3.0;
      BLD   103;
      U     "true";
      SPBNB _059;
      CALL "fc_h1_CntState16" (
           CntTyp                   := 'D',
           CntStart                 := L      3.0,
           CntValue                 := "sys_freeCnt16_100ms",
           CntOffset                := 100,
           CntRun                   := #out_Fail_WBr_StartValve,
           puls_CntStart            := #stat_CntStart13,
           Cnt_started              := #stat_CntStarted13,
           mem_CntValue             := #stat_CntValue13);
_059: NOP   0;
NETWORK
TITLE =Indication "Wire breakage stop valve"
//in_wire_break
      UN    #in_NoWireBrk_StopValve;
      UN    #out_StopValve;
      U     "prm_pma".p_Rel_WBrk_StopV;
      =     L      3.0;
      BLD   103;
      U     "true";
      SPBNB _05c;
      CALL "fc_h1_CntState16" (
           CntTyp                   := 'D',
           CntStart                 := L      3.0,
           CntValue                 := "sys_freeCnt16_100ms",
           CntOffset                := 100,
           CntRun                   := #out_Fail_WBr_StopValve,
           puls_CntStart            := #stat_CntStart14,
           Cnt_started              := #stat_CntStarted14,
           mem_CntValue             := #stat_CntValue14);
_05c: NOP   0;
NETWORK
TITLE =Indication "Wire breakage emergency stop valve"

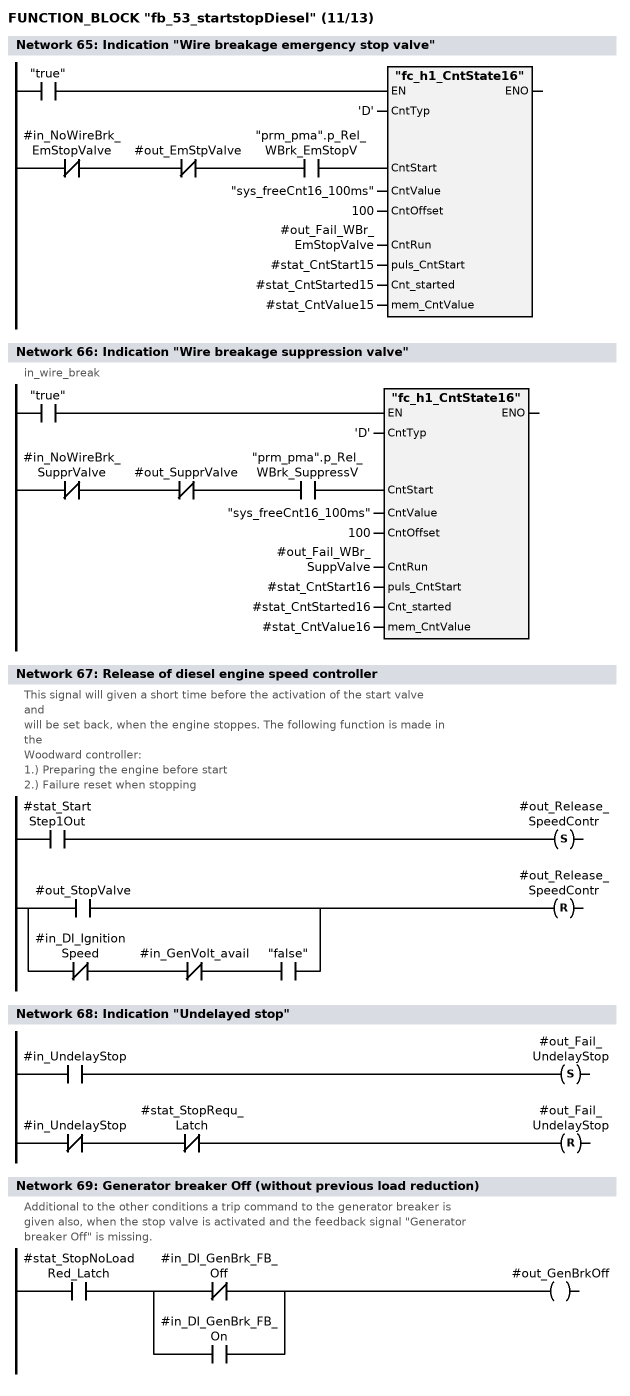
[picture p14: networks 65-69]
      UN    #in_NoWireBrk_EmStopValve;
      UN    #out_EmStpValve;
      U     "prm_pma".p_Rel_WBrk_EmStopV;
      =     L      3.0;
      BLD   103;
      U     "true";
      SPBNB _05d;
      CALL "fc_h1_CntState16" (
           CntTyp                   := 'D',
           CntStart                 := L      3.0,
           CntValue                 := "sys_freeCnt16_100ms",
           CntOffset                := 100,
           CntRun                   := #out_Fail_WBr_EmStopValve,
           puls_CntStart            := #stat_CntStart15,
           Cnt_started              := #stat_CntStarted15,
           mem_CntValue             := #stat_CntValue15);
_05d: NOP   0;
NETWORK
TITLE =Indication "Wire breakage suppression valve"
//in_wire_break
      UN    #in_NoWireBrk_SupprValve;
      UN    #out_SupprValve;
      U     "prm_pma".p_Rel_WBrk_SuppressV;
      =     L      3.0;
      BLD   103;
      U     "true";
      SPBNB _05e;
      CALL "fc_h1_CntState16" (
           CntTyp                   := 'D',
           CntStart                 := L      3.0,
           CntValue                 := "sys_freeCnt16_100ms",
           CntOffset                := 100,
           CntRun                   := #out_Fail_WBr_SuppValve,
           puls_CntStart            := #stat_CntStart16,
           Cnt_started              := #stat_CntStarted16,
           mem_CntValue             := #stat_CntValue16);
_05e: NOP   0;
NETWORK
TITLE =Release of diesel engine speed controller
//This signal will given a short time before the activation of the start valve
//and
//will be set back, when the engine stoppes. The following function is made in
//the
//Woodward controller:
//1.) Preparing the engine before start
//2.) Failure reset when stopping
      U     #stat_StartStep1Out;
      S     #out_Release_SpeedContr;
      U(    ;
      O     #out_StopValve;
      O     ;
      UN    #in_DI_IgnitionSpeed;
      UN    #in_GenVolt_avail;
      U     "false";
      )     ;
      R     #out_Release_SpeedContr;
      NOP   0;
NETWORK
TITLE =Indication "Undelayed stop"

      U     #in_UndelayStop;
      S     #out_Fail_UndelayStop;
      UN    #in_UndelayStop;
      UN    #stat_StopRequ_Latch;
      R     #out_Fail_UndelayStop;
      NOP   0;
NETWORK
TITLE =Generator breaker Off (without previous load reduction)
//Additional to the other conditions a trip command to the generator breaker is
//given also, when the stop valve is activated and the feedback signal "Generator
//breaker Off" is missing.
      U     #stat_StopNoLoadRed_Latch;
      U(    ;
      ON    #in_DI_GenBrk_FB_Off;
      O     #in_DI_GenBrk_FB_On;
      )     ;
      =     #out_GenBrkOff;
NETWORK
TITLE =Generator breaker trip command

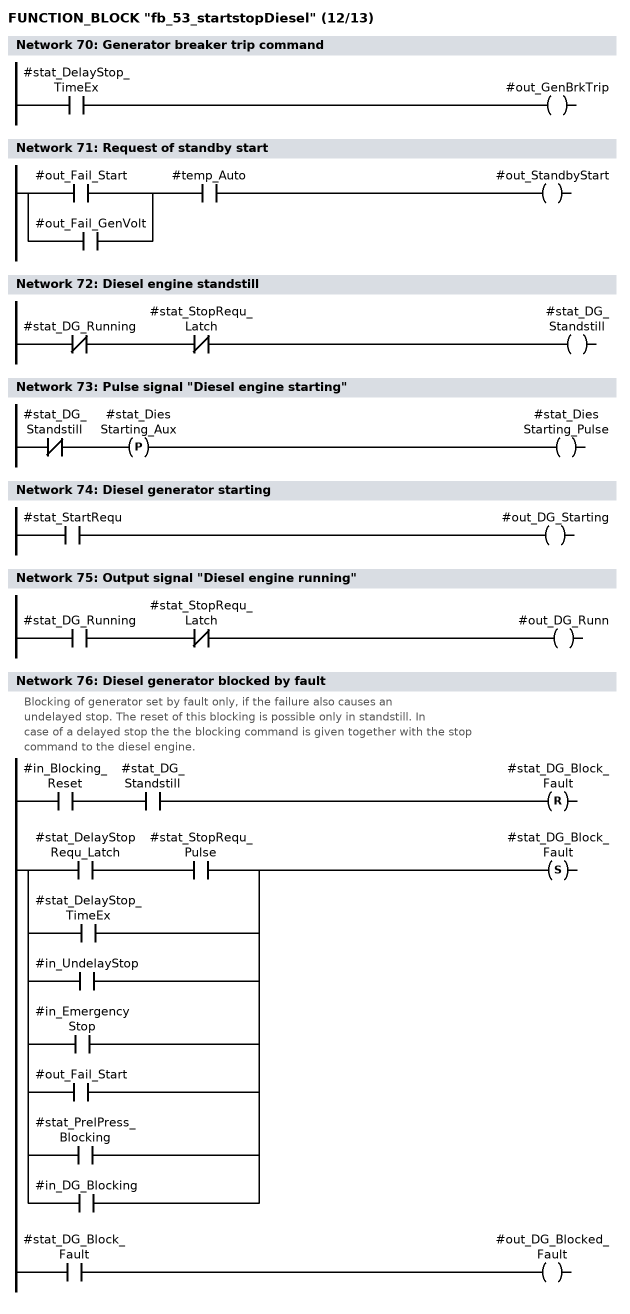
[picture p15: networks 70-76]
      U     #stat_DelayStop_TimeEx;
      =     #out_GenBrkTrip;
NETWORK
TITLE =Request of standby start

      U(    ;
      O     #out_Fail_Start;
      O     #out_Fail_GenVolt;
      )     ;
      U     #temp_Auto;
      =     #out_StandbyStart;
NETWORK
TITLE =Diesel engine standstill

      UN    #stat_DG_Running;
      UN    #stat_StopRequ_Latch;
      =     #stat_DG_Standstill;
NETWORK
TITLE =Pulse signal "Diesel engine starting"

      UN    #stat_DG_Standstill;
      FP    #stat_DiesStarting_Aux;
      =     #stat_DiesStarting_Pulse;
NETWORK
TITLE =Diesel generator starting

      U     #stat_StartRequ;
      =     #out_DG_Starting;
NETWORK
TITLE =Output signal "Diesel engine running"

      U     #stat_DG_Running;
      UN    #stat_StopRequ_Latch;
      =     #out_DG_Runn;
NETWORK
TITLE =Diesel generator blocked by fault
//Blocking of generator set by fault only, if the failure also causes an
//undelayed stop. The reset of this blocking is possible only in standstill. In
//case of a delayed stop the the blocking command is given together with the stop
//command to the diesel engine.
      U     #in_Blocking_Reset;
      U     #stat_DG_Standstill;
      R     #stat_DG_Block_Fault;
      U(    ;
      U     #stat_DelayStopRequ_Latch;
      U     #stat_StopRequ_Pulse;
      O     #stat_DelayStop_TimeEx;
      O     #in_UndelayStop;
      O     #in_EmergencyStop;
      O     #out_Fail_Start;
      O     #stat_PrelPress_Blocking;
      O     #in_DG_Blocking;
      )     ;
      S     #stat_DG_Block_Fault;
      U     #stat_DG_Block_Fault;
      =     #out_DG_Blocked_Fault;
NETWORK
TITLE =Forced change over from automatic to semi automatic mode
//The blocking of the generator set always causes a change over from "Automatic"
//to "Semi automatic" mode. There may be some additional conditions, which cause
//a
//changeover to "Semi automatic" mode, but no blocking.
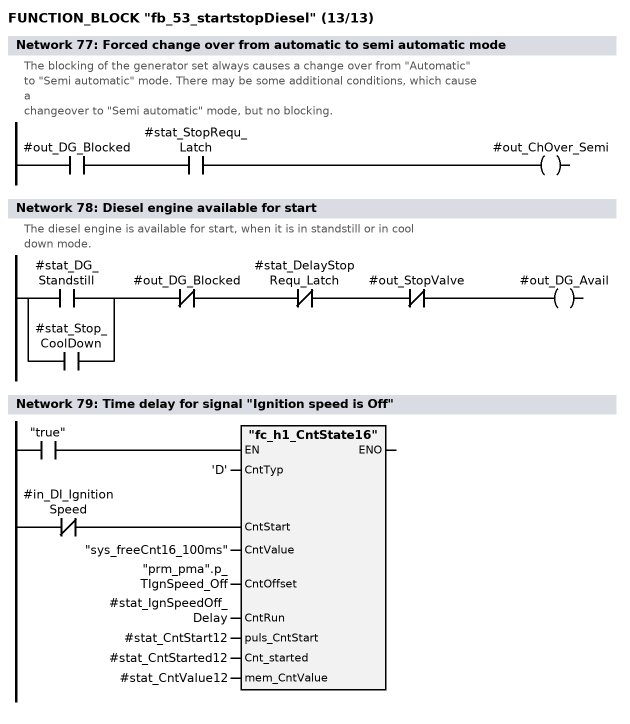
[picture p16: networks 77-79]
      U     #out_DG_Blocked;
      U     #stat_StopRequ_Latch;
      =     #out_ChOver_Semi;
NETWORK
TITLE =Diesel engine available for start
//The diesel engine is available for start, when it is in standstill or in cool
//down mode.
      U(    ;
      O     #stat_DG_Standstill;
      O     #stat_Stop_CoolDown;
      )     ;
      UN    #out_DG_Blocked;
      UN    #stat_DelayStopRequ_Latch;
      UN    #out_StopValve;
      =     #out_DG_Avail;
NETWORK
TITLE =Time delay for signal "Ignition speed is Off"

      UN    #in_DI_IgnitionSpeed;
      =     L      3.0;
      BLD   103;
      U     "true";
      SPBNB _060;
      CALL "fc_h1_CntState16" (
           CntTyp                   := 'D',
           CntStart                 := L      3.0,
           CntValue                 := "sys_freeCnt16_100ms",
           CntOffset                := "prm_pma".p_TIgnSpeed_Off,
           CntRun                   := #stat_IgnSpeedOff_Delay,
           puls_CntStart            := #stat_CntStart12,
           Cnt_started              := #stat_CntStarted12,
           mem_CntValue             := #stat_CntValue12);
_060: NOP   0;
NETWORK
TITLE =Indication "Diesel engine failure"

      U     #stat_IgnSpeedOff_Delay;
      FP    #stat_IgnSpeedOff_Aux;
      U(    ;
      U(    ;
      O     #in_DG_Start;
      O     ;
      U(    ;
      O     #temp_Auto;
      O     #temp_Semi;
      )     ;
      U     #stat_DG_Running;
      )     ;
      S     #stat_DG_Running2;
      U(    ;
      O     #stat_StopRequ_Latch;
      O     #stat_Fail_DieselEngine;
      )     ;
      R     #stat_DG_Running2;
      U     #stat_DG_Running2;
      )     ;
      S     #stat_Fail_DieselEngine;
      U     #in_Reset;
      R     #stat_Fail_DieselEngine;
      U     #stat_Fail_DieselEngine;
      =     #out_Fail_DieselEngine;
NETWORK
TITLE =Indication no. 31: "Prelubricating"

      L     31;
      U     #out_PreLub;
      UN    #out_PreHeat;
      UN    #stat_PreLPump;
      SPB   indi;
NETWORK
TITLE =Indication no. 32: "Preheating"

      L     32;
      U     #out_PreHeat;
      UN    #out_PreLub;
      SPB   indi;
NETWORK
TITLE =Indication no. 33: "Prelubricating + preheating"

      L     33;
      U     #out_PreLub;
      U     #out_PreHeat;
      UN    #stat_PreLPump;
      SPB   indi;
NETWORK
TITLE =Indication no. 34: "Start&Prelub"

      L     34;
      U     #out_PreLub;
      U     #stat_StartRequ;
      SPB   indi;
NETWORK
TITLE =Indication no. 35: "Start valve active"

      L     35;
      U     #out_StartValve;
      UN    #stat_DG_Running;
      SPB   indi;
NETWORK
TITLE =Indication no. 36: "Start pause"

      L     36;
      U     #stat_StartBegin;
      UN    #out_StartValve;
      UN    #stat_DG_Running;
      SPB   indi;
NETWORK
TITLE =Indication no. 42: "Cool down run"

      L     42;
      U     #stat_Stop_CoolDown;
      UN    #out_StopValve;
      SPB   indi;
NETWORK
TITLE =Indication no. 39: "Delayed stop" without kW display

      L     39;
      U     #stat_DelayStopRequ_Latch;
      UN    #in_DI_GenBrk_FB_On;
      UN    #stat_StopLoadRed_Latch;
      UN    #stat_Stop_CoolDown;
      UN    #out_StopValve;
      SPB   indi;
NETWORK
TITLE =Indication no. 40: "Delayed stop" with kW display

      L     40;
      U     #stat_DelayStopRequ_Latch;
      U     #in_DI_GenBrk_FB_On;
      UN    #stat_StopLoadRed_Latch;
      UN    #stat_Stop_CoolDown;
      UN    #out_StopValve;
      SPB   indi;
NETWORK
TITLE =Indication no. 41: "Load reduction"

      L     41;
      U     #stat_StopLoadRed_Latch;
      UN    #stat_Stop_CoolDown;
      UN    #out_StopValve;
      SPB   indi;
NETWORK
TITLE =Indication no. 37: "Generator set running" without kW display

      L     37;
      U     #stat_DG_Running;
      UN    #in_DI_RatedSpeed;
      UN    #in_DI_GenBrk_FB_On;
      UN    #stat_DelayStopRequ_Latch;
      UN    #out_StopValve;
      SPB   indi;
NETWORK
TITLE =Indication no. 45: "Rated speed" without kW display

      L     45;
      U     #stat_DG_Running;
      U     #in_DI_RatedSpeed;
      UN    #in_DI_GenBrk_FB_On;
      UN    #stat_DelayStopRequ_Latch;
      UN    #out_StopValve;
      SPB   indi;
NETWORK
TITLE =Indication no. 38: "Generator set running" with kW display

      L     38;
      U     #stat_DG_Running;
      U     #in_DI_GenBrk_FB_On;
      UN    #stat_DelayStopRequ_Latch;
      UN    #out_StopValve;
      SPB   indi;
NETWORK
TITLE =Indication no. 43: "Stopping"

      L     43;
      U     #out_StopValve;
      SPB   indi;
NETWORK
TITLE =Indication no. 30: "_______" (No indication)
//If there is no indication coming from this FB, "30" is delivered.
      L     30;
indi: T     #out_Operat_Status;
END_FUNCTION_BLOCK




DATA_BLOCK "startstopD"
TITLE =
VERSION : 0.0

"fb_53_startstopDiesel"
BEGIN
   in_Nmb_Gen_LoadSh := 0;
   in_act_mode := B#16#0;
   in_EG_set := FALSE;
   in_DG_Start := FALSE;
   in_DG_Stop := FALSE;
   in_UndelayStop := FALSE;
   in_DelayStop := FALSE;
   in_EmergencyStop := FALSE;
   in_Underload_Limit := FALSE;
   in_Autom_Stop := FALSE;
   in_Shore_Stop := FALSE;
   in_DG_Load_Off := FALSE;
   in_DI_GenBrk_FB_On := FALSE;
   in_DI_GenBrk_FB_Off := FALSE;
   in_DI_IgnitionSpeed := FALSE;
   in_DI_RatedSpeed := FALSE;
   in_GenVolt_avail := FALSE;
   in_MonitTime1 := FALSE;
   in_DG_Block_Engine := FALSE;
   in_DG_Blocking := FALSE;
   in_Blocking_Reset := FALSE;
   in_LubPress := FALSE;
   in_PrelubPress := FALSE;
   in_DRelStdby := FALSE;
   in_Blackout := FALSE;
   in_NoWireBrk_StartValve := FALSE;
   in_NoWireBrk_StopValve := FALSE;
   in_NoWireBrk_EmStopValve := FALSE;
   in_NoWireBrk_SupprValve := FALSE;
   in_Reset := FALSE;
   out_Operat_Status := 0;
   out_StartValve := FALSE;
   out_StopValve := FALSE;
   out_EmStpValve := FALSE;
   out_SupprValve := FALSE;
   out_Release_SpeedContr := FALSE;
   out_PreLub := FALSE;
   out_PreHeat := FALSE;
   out_SlowTurn := FALSE;
   out_StandbyStart := FALSE;
   out_ChOver_Semi := FALSE;
   out_GenBrkOff_LoadRed := FALSE;
   out_GenBrkOff := FALSE;
   out_GenBrkTrip := FALSE;
   out_DG_Blocked_Fault := FALSE;
   out_DG_Blocked := FALSE;
   out_DG_Starting := FALSE;
   out_DG_Runn := FALSE;
   out_DG_Avail := FALSE;
   out_Fail_Start := FALSE;
   out_Fail_Stop := FALSE;
   out_Fail_IgnSpd := FALSE;
   out_Fail_GenVolt := FALSE;
   out_Fail_UndelayStop := FALSE;
   out_Fail_DelayStop := FALSE;
   out_Fail_DieselEngine := FALSE;
   out_Fail_PrelubOil := FALSE;
   out_Fail_LubOil := FALSE;
   out_Fail_WBr_StartValve := FALSE;
   out_Fail_WBr_StopValve := FALSE;
   out_Fail_WBr_EmStopValve := FALSE;
   out_Fail_WBr_SuppValve := FALSE;
   stat_CountStAtt := 0;
   stat_Nmb_Gen_LoadSh_Old := 0;
   stat_CntValue01 := 0;
   stat_CntValue02 := 0;
   stat_CntValue03 := 0;
   stat_CntValue04 := 0;
   stat_CntValue05 := 0;
   stat_CntValue06 := 0;
   stat_CntValue07 := 0;
   stat_CntValue08 := 0;
   stat_CntValue09 := 0;
   stat_CntValue10 := 0;
   stat_CntValue11 := 0;
   stat_CntValue12 := 0;
   stat_CntValue13 := 0;
   stat_CntValue14 := 0;
   stat_CntValue15 := 0;
   stat_CntValue16 := 0;
   stat_CntValue17 := 0;
   stat_CntValue18 := 0;
   stat_CntValue19 := 0;
   stat_CntStart01 := FALSE;
   stat_CntStarted01 := FALSE;
   stat_CntStart02 := FALSE;
   stat_CntStarted02 := FALSE;
   stat_CntStart03 := FALSE;
   stat_CntStarted03 := FALSE;
   stat_CntStart04 := FALSE;
   stat_CntStarted04 := FALSE;
   stat_CntStart05 := FALSE;
   stat_CntStarted05 := FALSE;
   stat_CntStart06 := FALSE;
   stat_CntStarted06 := FALSE;
   stat_CntStart07 := FALSE;
   stat_CntStarted07 := FALSE;
   stat_CntStart08 := FALSE;
   stat_CntStarted08 := FALSE;
   stat_CntStart09 := FALSE;
   stat_CntStarted09 := FALSE;
   stat_CntStart10 := FALSE;
   stat_CntStarted10 := FALSE;
   stat_CntStart11 := FALSE;
   stat_CntStarted11 := FALSE;
   stat_CntStart12 := FALSE;
   stat_CntStarted12 := FALSE;
   stat_CntStart13 := FALSE;
   stat_CntStarted13 := FALSE;
   stat_CntStart14 := FALSE;
   stat_CntStarted14 := FALSE;
   stat_CntStart15 := FALSE;
   stat_CntStarted15 := FALSE;
   stat_CntStart16 := FALSE;
   stat_CntStarted16 := FALSE;
   stat_CntStart17 := FALSE;
   stat_CntStarted17 := FALSE;
   stat_CntStart18 := FALSE;
   stat_CntStarted18 := FALSE;
   stat_CntStart19 := FALSE;
   stat_CntStarted19 := FALSE;
   stat_StartRequ := FALSE;
   stat_StartBegin := FALSE;
   stat_StartBegPulse := FALSE;
   stat_StartStep1Out := FALSE;
   stat_StartStep1Fin := FALSE;
   stat_StartStep2Cond := FALSE;
   stat_StartStep2Fin := FALSE;
   stat_StartValve := FALSE;
   stat_StartStep3Out := FALSE;
   stat_StartStep3Fin := FALSE;
   stat_DG_Stop := FALSE;
   stat_DelayStopRequ_Latch := FALSE;
   stat_DelayStop_TimeEx := FALSE;
   stat_Standby_Conn := FALSE;
   stat_Stop_Shore := FALSE;
   stat_StopLoadRed_Latch := FALSE;
   stat_StopNoLoadRed_Latch := FALSE;
   stat_Stop_CoolDown := FALSE;
   stat_Stop_CoolDownEx := FALSE;
   stat_Stop_EG_NoLoadRun := FALSE;
   stat_Stop_BreakOff := FALSE;
   stat_StopRequ_Pulse := FALSE;
   stat_StopRequ_Latch := FALSE;
   stat_StopDelay := FALSE;
   stat_StopGoing := FALSE;
   stat_DG_Standstill := FALSE;
   stat_DG_Standstill_Delay := FALSE;
   stat_DiesStarting_Aux := FALSE;
   stat_DiesStarting_Pulse := FALSE;
   stat_DG_Running := FALSE;
   stat_DG_Block_Fault := FALSE;
   stat_PreLAct := FALSE;
   stat_PreLContMode := FALSE;
   stat_PreLCyclMode := FALSE;
   stat_PreLStartMode := FALSE;
   stat_PreLContOn := FALSE;
   stat_PreLCyclOn := FALSE;
   stat_PreLPump := FALSE;
   stat_PreLCyStep0Cond := FALSE;
   stat_PreLCyStep1 := FALSE;
   stat_PreLCyStep1Fin := FALSE;
   stat_PreLCyStep2Cond := FALSE;
   stat_PreLCyStep2Fin := FALSE;
   stat_PreLCyStep3Out := FALSE;
   stat_PreLCyStep3Fin := FALSE;
   stat_PreLStNBegin := FALSE;
   stat_PreLStNReady := FALSE;
   stat_PreLStBegin := FALSE;
   stat_PreLlowPress := FALSE;
   stat_SuppValvRequOff := FALSE;
   stat_PrelPress_Delay := FALSE;
   stat_PrelPress_Blocking := FALSE;
   stat_IgnSpeedOff_Delay := FALSE;
   stat_IgnSpeedOff_Aux := FALSE;
   stat_Fail_DieselEngine := FALSE;
   stat_DG_Running2 := FALSE;
   stat_DelayStop := FALSE;
   stat_failLubPress := FALSE;
END_DATA_BLOCK



FUNCTION "fc_512__SD_Function" : VOID
TITLE =Shut down function for 1 channel
//version!date    !author !change_segm!change_description
//-------+--------+-------+-----------+-------------------------------
// 1.0   !10.11.99!Bauch  ! ---       ! 1st vaild version
AUTHOR : Bauch
FAMILY : PMA71
NAME : SD_Funct
VERSION : 1.0


VAR_INPUT
  in_SD : BOOL ;	//Input "Shutdown", channel x
  in_NoWirebrk : BOOL ;	//Input "No wire breakage", channel x (0=wire breakage)
  in_MonitTime1 : BOOL ;	//Monitoring time 1
  in_MonitTime2 : BOOL ;	//Monitoring time 2
  in_SD_used : BOOL ;	//Shutdown used, channel x
  in_SD_delay_select : BOOL ;	//Delayed shutdown selected, channel x
  in_SD_MonT1_select : BOOL ;	//Release with Monitoring time 1 selected, channel x
  in_SD_MonT2_select : BOOL ;	//Release with Monitoring time 2 selected, channel x
  in_Reset : BOOL ;	//Reset
  in_Delay : INT ;	//Stabilization time (in 0.1s) for channel x
END_VAR
VAR_OUTPUT
  out_SD_undelayStop : BOOL ;	//Undelayed stop, channel x
  out_SD_delayStop : BOOL ;	//Delayed stop, channel x
  out_SD : BOOL ;	//Indication: Shutdown, channel x
  out_Wirebrk : BOOL ;	//Indication: Wire breakage, channel x
END_VAR
VAR_IN_OUT
  inout_CntValue : INT ;	//Memory for FC100 (timer/counter)
  inout_CntStart : BOOL ;	//Memory for FC100 (timer/counter)
  inout_Cnt_started : BOOL ;	//Memory for FC100 (timer/counter)
  inout_SD_undelayStop : BOOL ;	//Memory for "Undelayed Stop"
  inout_SD_delayStop : BOOL ;	//Memory for "Delayed Stop"
END_VAR
VAR_TEMP
  temp_SD_stabiliz : BOOL ;	//Shutdown after stabilization time, channel x
  temp_SD_active : BOOL ;	//Shutsdown active, channel x
END_VAR
BEGIN
NETWORK
TITLE =Stabilization time for shut down, channel x

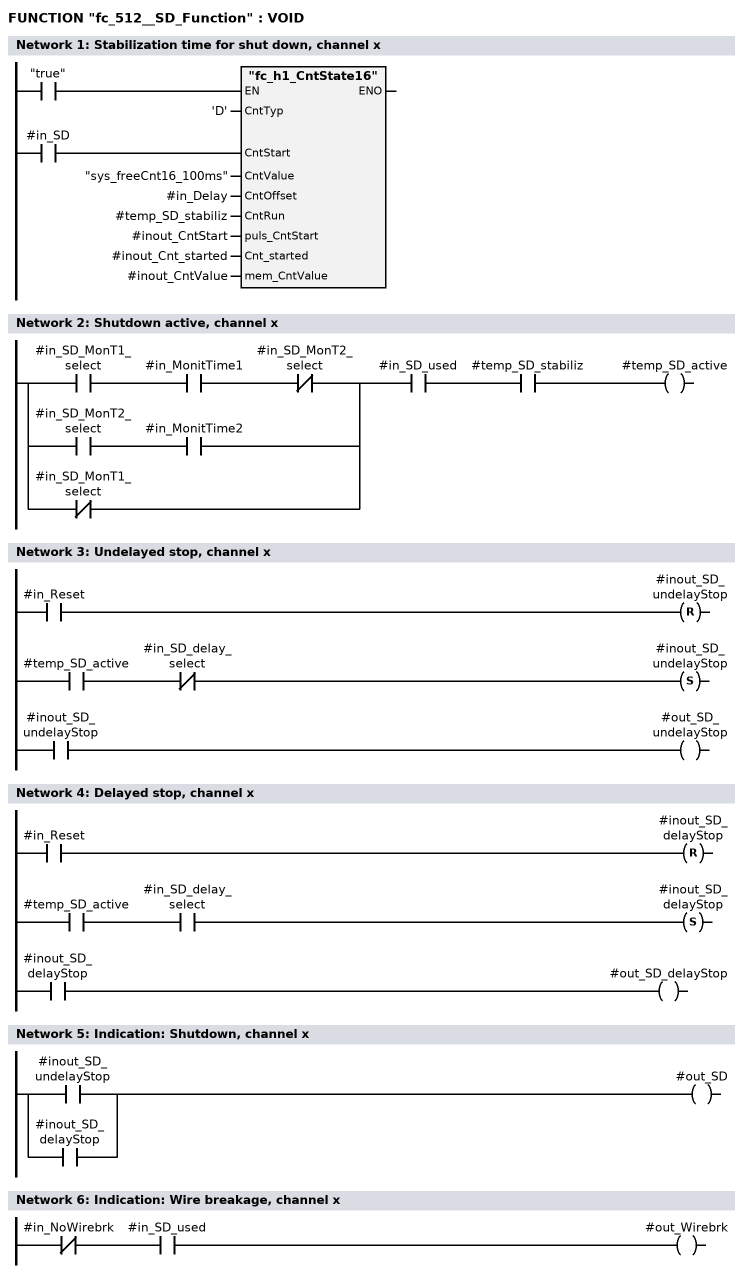
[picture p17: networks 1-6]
      U     #in_SD;
      =     L      1.0;
      BLD   103;
      U     "true";
      SPBNB _001;
      CALL "fc_h1_CntState16" (
           CntTyp                   := 'D',
           CntStart                 := L      1.0,
           CntValue                 := "sys_freeCnt16_100ms",
           CntOffset                := #in_Delay,
           CntRun                   := #temp_SD_stabiliz,
           puls_CntStart            := #inout_CntStart,
           Cnt_started              := #inout_Cnt_started,
           mem_CntValue             := #inout_CntValue);
_001: NOP   0;
NETWORK
TITLE =Shutdown active, channel x

      U(    ;
      U     #in_SD_MonT1_select;
      U     #in_MonitTime1;
      UN    #in_SD_MonT2_select;
      O     ;
      U     #in_SD_MonT2_select;
      U     #in_MonitTime2;
      ON    #in_SD_MonT1_select;
      )     ;
      U     #in_SD_used;
      U     #temp_SD_stabiliz;
      =     #temp_SD_active;
NETWORK
TITLE =Undelayed stop, channel x

      U     #in_Reset;
      R     #inout_SD_undelayStop;
      U     #temp_SD_active;
      UN    #in_SD_delay_select;
      S     #inout_SD_undelayStop;
      U     #inout_SD_undelayStop;
      =     #out_SD_undelayStop;
NETWORK
TITLE =Delayed stop, channel x

      U     #in_Reset;
      R     #inout_SD_delayStop;
      U     #temp_SD_active;
      U     #in_SD_delay_select;
      S     #inout_SD_delayStop;
      U     #inout_SD_delayStop;
      =     #out_SD_delayStop;
NETWORK
TITLE =Indication: Shutdown, channel x

      O     #inout_SD_undelayStop;
      O     #inout_SD_delayStop;
      =     #out_SD;
NETWORK
TITLE =Indication: Wire breakage, channel x

      UN    #in_NoWirebrk;
      U     #in_SD_used;
      =     #out_Wirebrk;
NETWORK
TITLE =

END_FUNCTION


FUNCTION_BLOCK "fb_512_DieselProtect"
TITLE =Protection of diesel engine (safety system function)
//version!date    !author !change_segm!change_description
//-------+--------+-------+-----------+-------------------------------
// 1.1   !17.04.00!Bauch  ! ---       ! last vaild version
// 1.2   !09.05.00!Bauch  ! 12        ! shutdown active only if no stop command
// 1.3   !14.05.00!Kahle  ! 22        ! especially input NORIS deleted
// 1.4   !29.06.00!Bauch  ! 30        ! Generator breaker Off with Emergency stop
//       !        !       !           ! manual
// 1.5   !05.08.00!Kahle  ! 27        ! EmergStopVv active in case of overspeed
//       !        !       !           ! only (selectible)
// 1.6   !31.01.01!Kahle  ! 12        ! Shutdown also active without stop command
// 1.7   !23.02.01!Kahle  ! 22        ! EmergStop activated if diesel running only
// 1.8   !12.03.01!Kahle  ! 32 new    ! Indication prealarm
// 1.9   !06.04.01!Bauch  ! 23,24     ! Standby start only if DG is running
// 1.10  !19.11.01!Kahle  ! 27        ! del. delayStop -->Emerg.Stop
AUTHOR : Bauch
FAMILY : PMA71
NAME : DiesSafe
VERSION : 1.10
CODE_VERSION1


VAR_INPUT
  in_act_mode : BYTE ;	//Active operation mode
  in_EG_Set : BOOL ;	//Generator set is an Emergency generator
  in_EG_Harbour_Mode : BOOL ;	//Emergency generator is in "Harbour mode"
  in_EG_PowerFb_Mode : BOOL ;	//Emergency generator is in "Power feedback mode"
  in_SD_C1 : BOOL ;	//Shutdown channel 1
  in_SD_C2 : BOOL ;	//Shutdown channel 2
  in_SD_C3 : BOOL ;	//Shutdown channel 3
  in_SD_C4 : BOOL ;	//Shutdown channel 4
  in_SD_C5 : BOOL ;	//Shutdown channel 5
  in_SD_C6 : BOOL ;	//Shutdown channel 6
  in_SD_C7 : BOOL ;	//Shutdown channel 7
  in_SD_C8 : BOOL ;	//Shutdown channel 8
  in_NoWirebrk_C1 : BOOL ;	//No wire breakage shutdown channel 1 (0=Wire breakage)
  in_NoWirebrk_C2 : BOOL ;	//No wire breakage shutdown channel 2 (0=Wire breakage)
  in_NoWirebrk_C3 : BOOL ;	//No wire breakage shutdown channel 3 (0=Wire breakage)
  in_NoWirebrk_C4 : BOOL ;	//No wire breakage shutdown channel 4 (0=Wire breakage)
  in_NoWirebrk_C5 : BOOL ;	//No wire breakage shutdown channel 5 (0=Wire breakage)
  in_NoWirebrk_C6 : BOOL ;	//No wire breakage shutdown channel 6 (0=Wire breakage)
  in_NoWirebrk_C7 : BOOL ;	//No wire breakage shutdown channel 7 (0=Wire breakage)
  in_NoWirebrk_C8 : BOOL ;	//No wire breakage shutdown channel 8 (0=Wire breakage)
  in_DI_EmergSt_PB : BOOL ;	//Emergency stop (Pushbutton)
  in_DI_Prealarm : BOOL ;	//Prealarm
  in_DI_FB_GenBrk_Off : BOOL ;	//Feedback signal generator breaker is OFF (for stop release)
  in_DI_IgnitionSpeed : BOOL ;	//Ignition speed
  in_GenVolt_avail : BOOL ;	//Generator voltage is available (Standard: >85%)
  in_Prelub : BOOL ;	//Diesel engine is prelubricated
  in_Stop_Command : BOOL ;	//Diesel Engine Stop Command is active
  in_Reset : BOOL ;	//Reset
END_VAR
VAR_OUTPUT
  out_StandbyStart : BOOL ;	//Request for standby generator start
  out_StandbyStart2 : BOOL ;	//Request for 2nd standby generator start (in case of shutdown)
  out_UndelayStop : BOOL ;	//Diesel undelayed stop command (to FB47)
  out_DelayStop : BOOL ;	//Diesel delayed stop command (to FB47)
  out_EmergencyStop : BOOL ;	//Diesel emergency stop command (to FB47)
  out_Blocking : BOOL ;	//Blocking of the generator set
  out_ChOver_Semi : BOOL ;	//Forced change over from automatic to semi automatic mode
  out_GenBrkOff : BOOL ;	//Generator breaker Off command
  out_MonitTime1 : BOOL ;	//Monitoring time 1 expired
  out_MonitTime2 : BOOL ;	//Monitoring time 2 expired
  out_Fail_SD_C1 : BOOL ;	//Indication: Shutdown channel 1
  out_Fail_SD_C2 : BOOL ;	//Indication: Shutdown channel 2
  out_Fail_SD_C3 : BOOL ;	//Indication: Shutdown channel 3
  out_Fail_SD_C4 : BOOL ;	//Indication: Shutdown channel 4
  out_Fail_SD_C5 : BOOL ;	//Indication: Shutdown channel 5
  out_Fail_SD_C6 : BOOL ;	//Indication: Shutdown channel 6
  out_Fail_SD_C7 : BOOL ;	//Indication: Shutdown channel 7
  out_Fail_SD_C8 : BOOL ;	//Indication: Shutdown channel 8
  out_Fail_Wbrk_C1 : BOOL ;	//Indication: Wire breakage shutdown channel 1
  out_Fail_Wbrk_C2 : BOOL ;	//Indication: Wire breakage shutdown channel 2
  out_Fail_Wbrk_C3 : BOOL ;	//Indication: Wire breakage shutdown channel 3
  out_Fail_Wbrk_C4 : BOOL ;	//Indication: Wire breakage shutdown channel 4
  out_Fail_Wbrk_C5 : BOOL ;	//Indication: Wire breakage shutdown channel 5
  out_Fail_Wbrk_C6 : BOOL ;	//Indication: Wire breakage shutdown channel 6
  out_Fail_Wbrk_C7 : BOOL ;	//Indication: Wire breakage shutdown channel 7
  out_Fail_Wbrk_C8 : BOOL ;	//Indication: Wire breakage shutdown channel 8
  out_Fail_EmStpMan : BOOL ;	//Indication: Emergency stop manual
  out_Fail_Prealarm : BOOL ;	//Indication: Prealarm
  out_Fail_Sensor_SD2 : BOOL ;	//Indication: Sensor failure of shutdown channel 2
END_VAR
VAR
  stat_CntValue01 : INT ;	//Memory for FC100 (timer/counter) No. 01 (Delay SD1)
  stat_CntValue02 : INT ;	//Memory for FC100 (timer/counter) No. 02 (Delay SD2)
  stat_CntValue03 : INT ;	//Memory for FC100 (timer/counter) No. 03 (Delay SD3)
  stat_CntValue04 : INT ;	//Memory for FC100 (timer/counter) No. 04 (Delay SD4)
  stat_CntValue05 : INT ;	//Memory for FC100 (timer/counter) No. 05 (Delay SD5)
  stat_CntValue06 : INT ;	//Memory for FC100 (timer/counter) No. 06 (Delay SD6)
  stat_CntValue07 : INT ;	//Memory for FC100 (timer/counter) No. 07 (Delay SD7)
  stat_CntValue08 : INT ;	//Memory for FC100 (timer/counter) No. 08 (Delay SD8)
  stat_CntValue09 : INT ;	//Memory for FC100 (timer/counter) No. 09 (Monitoring time 1)
  stat_CntValue10 : INT ;	//Memory for FC100 (timer/counter) No. 10 (Monitoring time 2)
  stat_CntValue11 : INT ;	//Memory for FC100 (timer/counter) No. 11 (Sensor failure SD2)
  stat_CntStart01 : BOOL ;	//Memory for FC100 (timer/counter) No. 01 (Delay SD1)
  stat_CntStarted01 : BOOL ;	//Memory for FC100 (timer/counter) No. 01 (Delay SD1)
  stat_CntStart02 : BOOL ;	//Memory for FC100 (timer/counter) No. 02 (Delay SD2)
  stat_CntStarted02 : BOOL ;	//Memory for FC100 (timer/counter) No. 02 (Delay SD2)
  stat_CntStart03 : BOOL ;	//Memory for FC100 (timer/counter) No. 03 (Delay SD3)
  stat_CntStarted03 : BOOL ;	//Memory for FC100 (timer/counter) No. 03 (Delay SD3)
  stat_CntStart04 : BOOL ;	//Memory for FC100 (timer/counter) No. 04 (Delay SD4)
  stat_CntStarted04 : BOOL ;	//Memory for FC100 (timer/counter) No. 04 (Delay SD4)
  stat_CntStart05 : BOOL ;	//Memory for FC100 (timer/counter) No. 05 (Delay SD5)
  stat_CntStarted05 : BOOL ;	//Memory for FC100 (timer/counter) No. 05 (Delay SD5)
  stat_CntStart06 : BOOL ;	//Memory for FC100 (timer/counter) No. 06 (Delay SD6)
  stat_CntStarted06 : BOOL ;	//Memory for FC100 (timer/counter) No. 06 (Delay SD6)
  stat_CntStart07 : BOOL ;	//Memory for FC100 (timer/counter) No. 07 (Delay SD7)
  stat_CntStarted07 : BOOL ;	//Memory for FC100 (timer/counter) No. 07 (Delay SD7)
  stat_CntStart08 : BOOL ;	//Memory for FC100 (timer/counter) No. 08 (Delay SD8)
  stat_CntStarted08 : BOOL ;	//Memory for FC100 (timer/counter) No. 08 (Delay SD8)
  stat_CntStart09 : BOOL ;	//Memory for FC100 (timer/counter) No. 09 (Monitoring time 1)
  stat_CntStarted09 : BOOL ;	//Memory for FC100 (timer/counter) No. 09 (Monitoring time 1)
  stat_CntStart10 : BOOL ;	//Memory for FC100 (timer/counter) No. 10 (Monitoring time 2)
  stat_CntStarted10 : BOOL ;	//Memory for FC100 (timer/counter) No. 10 (Monitoring time 2)
  stat_CntStart11 : BOOL ;	//Memory for FC100 (timer/counter) No. 11 (Sensor failure SD2)
  stat_CntStarted11 : BOOL ;	//Memory for FC100 (timer/counter) No. 11 (Sensor failure SD2)
  stat_SD1_M_Undelay : BOOL ;	//Memory for FC57 (RS) (Undelayed Stop, channel 1)
  stat_SD1_M_Delay : BOOL ;	//Memory for FC57 (RS) (Delayed Stop, channel 1)
  stat_SD2_M_Undelay : BOOL ;	//Memory for FC57 (RS) (Undelayed Stop, channel 2)
  stat_SD2_M_Delay : BOOL ;	//Memory for FC57 (RS) (Delayed Stop, channel 2)
  stat_SD3_M_Undelay : BOOL ;	//Memory for FC57 (RS) (Undelayed Stop, channel 3)
  stat_SD3_M_Delay : BOOL ;	//Memory for FC57 (RS) (Delayed Stop, channel 3)
  stat_SD4_M_Undelay : BOOL ;	//Memory for FC57 (RS) (Undelayed Stop, channel 4)
  stat_SD4_M_Delay : BOOL ;	//Memory for FC57 (RS) (Delayed Stop, channel 4)
  stat_SD5_M_Undelay : BOOL ;	//Memory for FC57 (RS) (Undelayed Stop, channel 5)
  stat_SD5_M_Delay : BOOL ;	//Memory for FC57 (RS) (Delayed Stop, channel 5)
  stat_SD6_M_Undelay : BOOL ;	//Memory for FC57 (RS) (Undelayed Stop, channel 6)
  stat_SD6_M_Delay : BOOL ;	//Memory for FC57 (RS) (Delayed Stop, channel 6)
  stat_SD7_M_Undelay : BOOL ;	//Memory for FC57 (RS) (Undelayed Stop, channel 7)
  stat_SD7_M_Delay : BOOL ;	//Memory for FC57 (RS) (Delayed Stop, channel 7)
  stat_SD8_M_Undelay : BOOL ;	//Memory for FC57 (RS) (Undelayed Stop, channel 8)
  stat_SD8_M_Delay : BOOL ;	//Memory for FC57 (RS) (Delayed Stop, channel 8)
  stat_DGRunning : BOOL ;	//Diesel generator running ("Ignition speed" or "Gen. voltage > 85%")
  stat_MonitTime1 : BOOL ;	//Monitoring time 1 expired
  stat_MonitTime2 : BOOL ;	//Monitoring time 2 expired
  stat_Harb_Feedb_Mode : BOOL ;	//Emergency generator in harbour mode or in power feedback mode
  stat_SD1_undelayStop : BOOL ;	//Undelayed stop, channel 1
  stat_SD2_undelayStop : BOOL ;	//Undelayed stop, channel 2
  stat_SD3_undelayStop : BOOL ;	//Undelayed stop, channel 3
  stat_SD4_undelayStop : BOOL ;	//Undelayed stop, channel 4
  stat_SD5_undelayStop : BOOL ;	//Undelayed stop, channel 5
  stat_SD6_undelayStop : BOOL ;	//Undelayed stop, channel 6
  stat_SD7_undelayStop : BOOL ;	//Undelayed stop, channel 7
  stat_SD8_undelayStop : BOOL ;	//Undelayed stop, channel 8
  stat_SD1_delayStop : BOOL ;	//Delayed stop, channel 1
  stat_SD2_delayStop : BOOL ;	//Delayed stop, channel 2
  stat_SD3_delayStop : BOOL ;	//Delayed stop, channel 3
  stat_SD4_delayStop : BOOL ;	//Delayed stop, channel 4
  stat_SD5_delayStop : BOOL ;	//Delayed stop, channel 5
  stat_SD6_delayStop : BOOL ;	//Delayed stop, channel 6
  stat_SD7_delayStop : BOOL ;	//Delayed stop, channel 7
  stat_SD8_delayStop : BOOL ;	//Delayed stop, channel 8
  stat_UndelayStop : BOOL ;	//SD1...8 undelayed stop
  stat_DelayStop : BOOL ;	//SD1...8 delayed stop
  stat_EmergStop_Man : BOOL ;	//Emergency stop push-button operated
  stat_UndelStop_SD3_8 : BOOL ;	//Undelayed shutdown, channel 3...8 (for EG depending on the active mode)
END_VAR
VAR_TEMP
  temp_OM_Local : BOOL ;	//Active operation mode: Local
  temp_OM_Semi_OP : BOOL ;	//Active operation mode: Semi automatic OP
  temp_OM_Auto_OP : BOOL ;	//Active operation mode: Auto OP
  temp_OM_Semi_MMI : BOOL ;	//Active operation mode: Semi automatic MMI
  temp_OM_Auto_MMI : BOOL ;	//Active operation mode: Auto MMI
  temp_OM_Test : BOOL ;	//Active operation mode: Test (EG only)
  temp_Reserve_006 : BOOL ;	//Reserved (Transfer Byte --> Bit)
  temp_Reserve_007 : BOOL ;	//Reserved (Transfer Byte --> Bit)
  temp_SD1_used : BOOL ;	//SD1 used
  temp_SD2_used : BOOL ;	//SD2 used
  temp_SD3_used : BOOL ;	//SD3 used
  temp_SD4_used : BOOL ;	//SD4 used
  temp_SD5_used : BOOL ;	//SD5 used
  temp_SD6_used : BOOL ;	//SD6 used
  temp_SD7_used : BOOL ;	//SD7 used
  temp_SD8_used : BOOL ;	//SD8 used
  temp_SD1_delay_select : BOOL ;	//SD1 delayed shutdown selected
  temp_SD2_delay_select : BOOL ;	//SD2 delayed shutdown selected
  temp_SD3_delay_select : BOOL ;	//SD3 delayed shutdown selected
  temp_SD4_delay_select : BOOL ;	//SD4 delayed shutdown selected
  temp_SD5_delay_select : BOOL ;	//SD5 delayed shutdown selected
  temp_SD6_delay_select : BOOL ;	//SD6 delayed shutdown selected
  temp_SD7_delay_select : BOOL ;	//SD7 delayed shutdown selected
  temp_SD8_delay_select : BOOL ;	//SD8 delayed shutdown selected
  temp_SD1_MonT1_select : BOOL ;	//SD1 Release with Monitoring Time 1 selected
  temp_SD2_MonT1_select : BOOL ;	//SD2 Release with Monitoring Time 1 selected
  temp_SD3_MonT1_select : BOOL ;	//SD3 Release with Monitoring Time 1 selected
  temp_SD4_MonT1_select : BOOL ;	//SD4 Release with Monitoring Time 1 selected
  temp_SD5_MonT1_select : BOOL ;	//SD5 Release with Monitoring Time 1 selected
  temp_SD6_MonT1_select : BOOL ;	//SD6 Release with Monitoring Time 1 selected
  temp_SD7_MonT1_select : BOOL ;	//SD7 Release with Monitoring Time 1 selected
  temp_SD8_MonT1_select : BOOL ;	//SD8 Release with Monitoring Time 1 selected
  temp_SD1_MonT2_select : BOOL ;	//SD1 Release with Monitoring Time 2 selected
  temp_SD2_MonT2_select : BOOL ;	//SD2 Release with Monitoring Time 2 selected
  temp_SD3_MonT2_select : BOOL ;	//SD3 Release with Monitoring Time 2 selected
  temp_SD4_MonT2_select : BOOL ;	//SD4 Release with Monitoring Time 2 selected
  temp_SD5_MonT2_select : BOOL ;	//SD5 Release with Monitoring Time 2 selected
  temp_SD6_MonT2_select : BOOL ;	//SD6 Release with Monitoring Time 2 selected
  temp_SD7_MonT2_select : BOOL ;	//SD7 Release with Monitoring Time 2 selected
  temp_SD8_MonT2_select : BOOL ;	//SD8 Release with Monitoring Time 2 selected
  temp_Auto : BOOL ;	//Active operation mode: Auto
  temp_Semi : BOOL ;	//Active operation mode: Semi
  temp_ScratchFlag : BOOL ;	//Scratch flag
END_VAR
BEGIN
NETWORK
TITLE =Active operation mode (Transfer Byte --> Bit)
//This transfer function is relaying on the relative addresses of the "temp"
//variables "temp_OM_Local" ... "temp_OM_Auto" in the area from 0.0 ... 0.7.
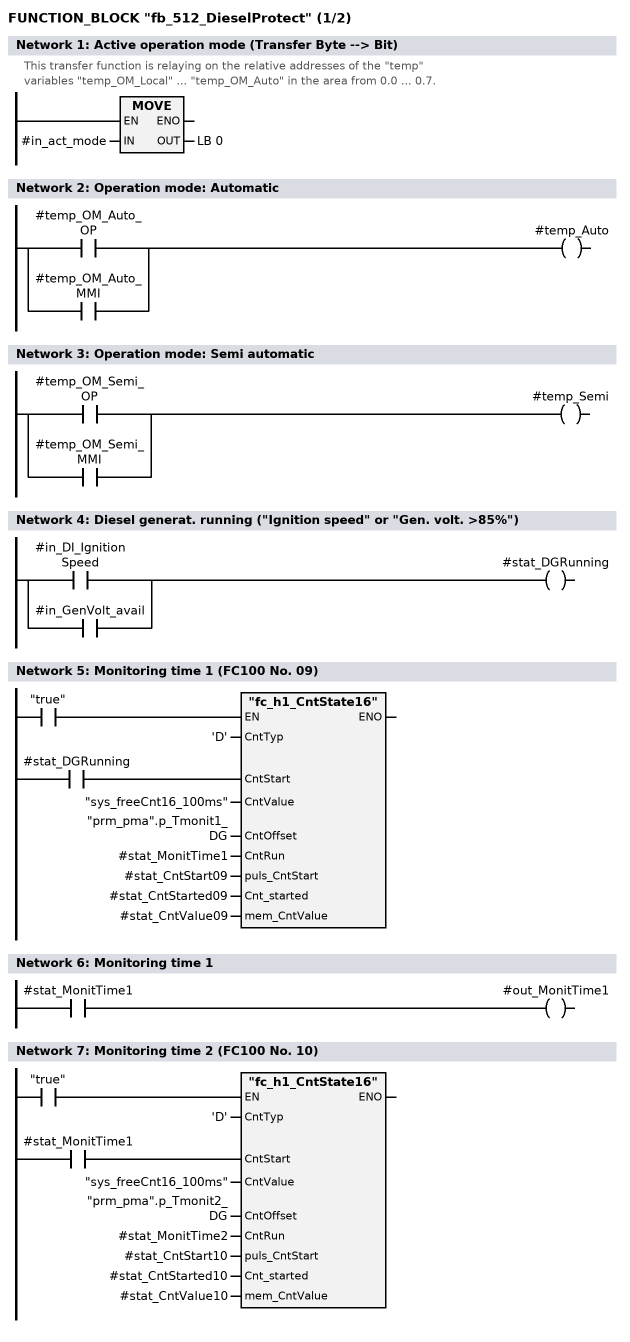
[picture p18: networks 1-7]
      L     #in_act_mode;
      T     LB     0;
NETWORK
TITLE =Operation mode: Automatic

      O     #temp_OM_Auto_OP;
      O     #temp_OM_Auto_MMI;
      =     #temp_Auto;
NETWORK
TITLE =Operation mode: Semi automatic

      O     #temp_OM_Semi_OP;
      O     #temp_OM_Semi_MMI;
      =     #temp_Semi;
NETWORK
TITLE =Diesel generat. running ("Ignition speed" or "Gen. volt. >85%")

      O     #in_DI_IgnitionSpeed;
      O     #in_GenVolt_avail;
      =     #stat_DGRunning;
NETWORK
TITLE =Monitoring time 1 (FC100 No. 09)

      U     #stat_DGRunning;
      =     L      6.0;
      BLD   103;
      U     "true";
      SPBNB _001;
      CALL "fc_h1_CntState16" (
           CntTyp                   := 'D',
           CntStart                 := L      6.0,
           CntValue                 := "sys_freeCnt16_100ms",
           CntOffset                := "prm_pma".p_Tmonit1_DG,
           CntRun                   := #stat_MonitTime1,
           puls_CntStart            := #stat_CntStart09,
           Cnt_started              := #stat_CntStarted09,
           mem_CntValue             := #stat_CntValue09);
_001: NOP   0;
NETWORK
TITLE =Monitoring time 1

      U     #stat_MonitTime1;
      =     #out_MonitTime1;
NETWORK
TITLE =Monitoring time 2 (FC100 No. 10)

      U     #stat_MonitTime1;
      =     L      6.0;
      BLD   103;
      U     "true";
      SPBNB _002;
      CALL "fc_h1_CntState16" (
           CntTyp                   := 'D',
           CntStart                 := L      6.0,
           CntValue                 := "sys_freeCnt16_100ms",
           CntOffset                := "prm_pma".p_Tmonit2_DG,
           CntRun                   := #stat_MonitTime2,
           puls_CntStart            := #stat_CntStart10,
           Cnt_started              := #stat_CntStarted10,
           mem_CntValue             := #stat_CntValue10);
_002: NOP   0;
NETWORK
TITLE =Monitoring time 2

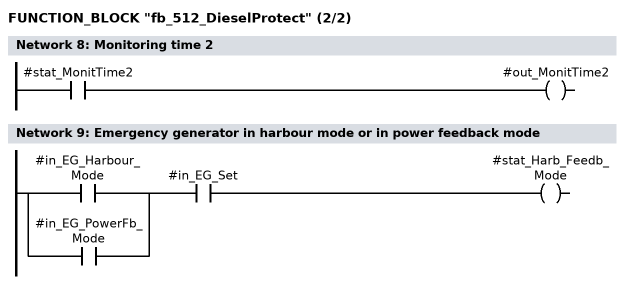
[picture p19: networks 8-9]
      U     #stat_MonitTime2;
      =     #out_MonitTime2;
NETWORK
TITLE =Emergency generator in harbour mode or in power feedback mode

      U(    ;
      O     #in_EG_Harbour_Mode;
      O     #in_EG_PowerFb_Mode;
      )     ;
      U     #in_EG_Set;
      =     #stat_Harb_Feedb_Mode;
NETWORK
TITLE =Transfer of parameters (Byte --> Bit)
//This transfer function is relaying on the relative adresses of the "temp"
//variables "temp_SD1_used" ... "temp_SD8_MonT2_select" in the area
//from 1.0 ...  4.7.
      U     #in_EG_Set;
      SPB   EG;
//Standard Diesel/Shaft generator mode
      L     DB41.DBB  367;
      T     LB     1;
      L     DB41.DBB  368;
      T     LB     2;
      L     DB41.DBB  369;
      T     LB     3;
      L     DB41.DBB  370;
      T     LB     4;
      SPA   End;

EG:   O     #in_EG_Harbour_Mode;
      O     #in_EG_PowerFb_Mode;
      SPB   Harb;
//Emergency generator mode
      L     DB41.DBB  588;
      T     LB     1;
      L     DB41.DBB  589;
      T     LB     2;
      L     DB41.DBB  590;
      T     LB     3;
      L     DB41.DBB  591;
      T     LB     4;
      SPA   End;

Harb: U     #in_EG_PowerFb_Mode;
      SPB   PFbk;
//Harbour mode
      L     DB41.DBB  592;
      T     LB     1;
      L     DB41.DBB  593;
      T     LB     2;
      L     DB41.DBB  594;
      T     LB     3;
      L     DB41.DBB  595;
      T     LB     4;
      SPA   End;

PFbk: NOP   0;
//Power feedback mode
      L     DB41.DBB  596;
      T     LB     1;
      L     DB41.DBB  597;
      T     LB     2;
      L     DB41.DBB  598;
      T     LB     3;
      L     DB41.DBB  599;
      T     LB     4;

End:  NOP   0;

NETWORK
TITLE =Shutdown processing, channel 1

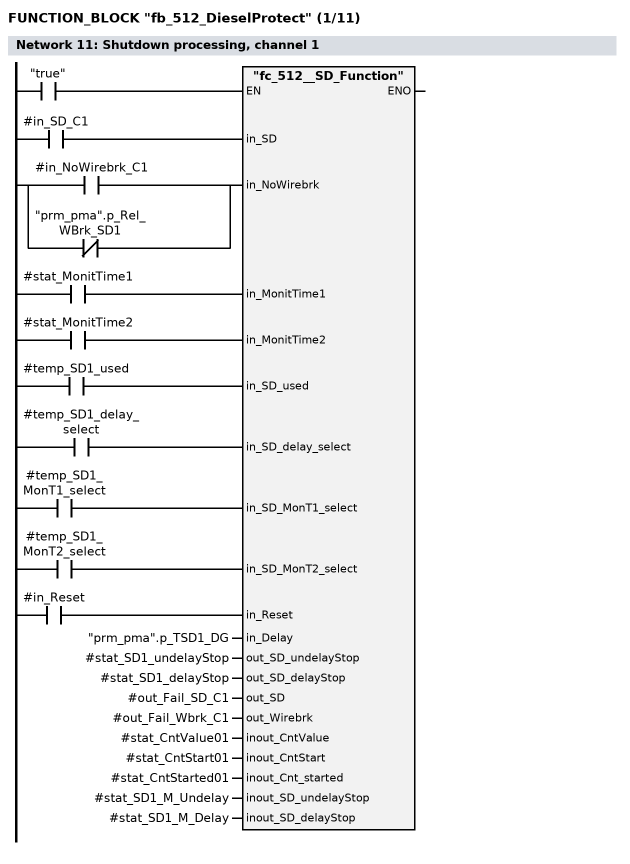
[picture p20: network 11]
      U     #in_SD_C1;
      =     L      6.0;
      BLD   103;
      U(    ;
      O     #in_NoWirebrk_C1;
      ON    "prm_pma".p_Rel_WBrk_SD1;
      )     ;
      =     L      6.1;
      BLD   103;
      U     #stat_MonitTime1;
      =     L      6.2;
      BLD   103;
      U     #stat_MonitTime2;
      =     L      6.3;
      BLD   103;
      U     #temp_SD1_used;
      =     L      6.4;
      BLD   103;
      U     #temp_SD1_delay_select;
      =     L      6.5;
      BLD   103;
      U     #temp_SD1_MonT1_select;
      =     L      6.6;
      BLD   103;
      U     #temp_SD1_MonT2_select;
      =     L      6.7;
      BLD   103;
      U     #in_Reset;
      =     L      7.0;
      BLD   103;
      U     "true";
      SPBNB _003;
      CALL "fc_512__SD_Function" (
           in_SD                    := L      6.0,
           in_NoWirebrk             := L      6.1,
           in_MonitTime1            := L      6.2,
           in_MonitTime2            := L      6.3,
           in_SD_used               := L      6.4,
           in_SD_delay_select       := L      6.5,
           in_SD_MonT1_select       := L      6.6,
           in_SD_MonT2_select       := L      6.7,
           in_Reset                 := L      7.0,
           in_Delay                 := "prm_pma".p_TSD1_DG,
           out_SD_undelayStop       := #stat_SD1_undelayStop,
           out_SD_delayStop         := #stat_SD1_delayStop,
           out_SD                   := #out_Fail_SD_C1,
           out_Wirebrk              := #out_Fail_Wbrk_C1,
           inout_CntValue           := #stat_CntValue01,
           inout_CntStart           := #stat_CntStart01,
           inout_Cnt_started        := #stat_CntStarted01,
           inout_SD_undelayStop     := #stat_SD1_M_Undelay,
           inout_SD_delayStop       := #stat_SD1_M_Delay);
_003: NOP   0;
NETWORK
TITLE =Shutdown processing, channel 2

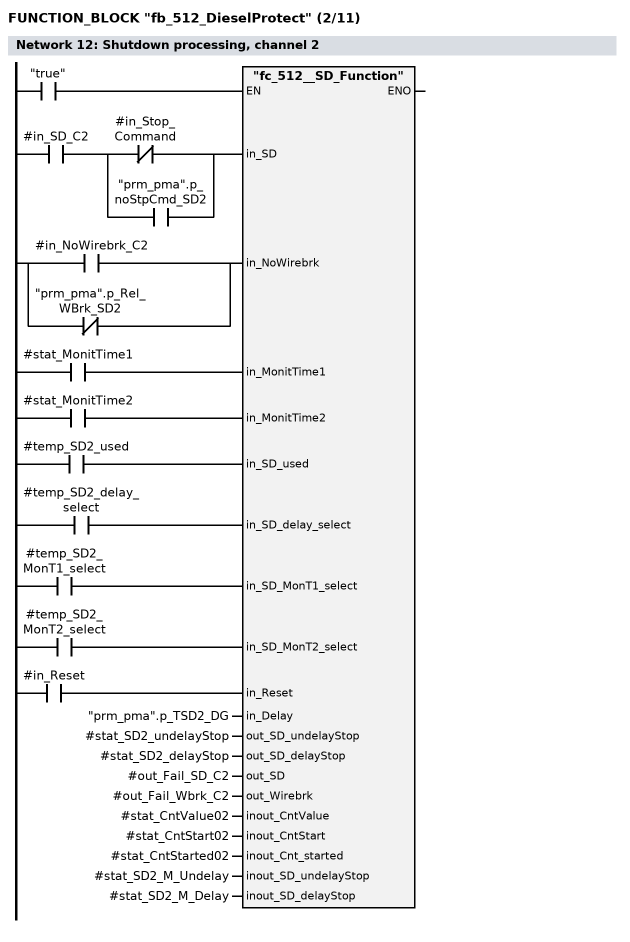
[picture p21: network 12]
      U     #in_SD_C2;
      U(    ;
      ON    #in_Stop_Command;
      O     "prm_pma".p_noStpCmd_SD2;
      )     ;
      =     L      6.0;
      BLD   103;
      U(    ;
      O     #in_NoWirebrk_C2;
      ON    "prm_pma".p_Rel_WBrk_SD2;
      )     ;
      =     L      6.1;
      BLD   103;
      U     #stat_MonitTime1;
      =     L      6.2;
      BLD   103;
      U     #stat_MonitTime2;
      =     L      6.3;
      BLD   103;
      U     #temp_SD2_used;
      =     L      6.4;
      BLD   103;
      U     #temp_SD2_delay_select;
      =     L      6.5;
      BLD   103;
      U     #temp_SD2_MonT1_select;
      =     L      6.6;
      BLD   103;
      U     #temp_SD2_MonT2_select;
      =     L      6.7;
      BLD   103;
      U     #in_Reset;
      =     L      7.0;
      BLD   103;
      U     "true";
      SPBNB _00e;
      CALL "fc_512__SD_Function" (
           in_SD                    := L      6.0,
           in_NoWirebrk             := L      6.1,
           in_MonitTime1            := L      6.2,
           in_MonitTime2            := L      6.3,
           in_SD_used               := L      6.4,
           in_SD_delay_select       := L      6.5,
           in_SD_MonT1_select       := L      6.6,
           in_SD_MonT2_select       := L      6.7,
           in_Reset                 := L      7.0,
           in_Delay                 := "prm_pma".p_TSD2_DG,
           out_SD_undelayStop       := #stat_SD2_undelayStop,
           out_SD_delayStop         := #stat_SD2_delayStop,
           out_SD                   := #out_Fail_SD_C2,
           out_Wirebrk              := #out_Fail_Wbrk_C2,
           inout_CntValue           := #stat_CntValue02,
           inout_CntStart           := #stat_CntStart02,
           inout_Cnt_started        := #stat_CntStarted02,
           inout_SD_undelayStop     := #stat_SD2_M_Undelay,
           inout_SD_delayStop       := #stat_SD2_M_Delay);
_00e: NOP   0;
NETWORK
TITLE =Shutdown processing, channel 3

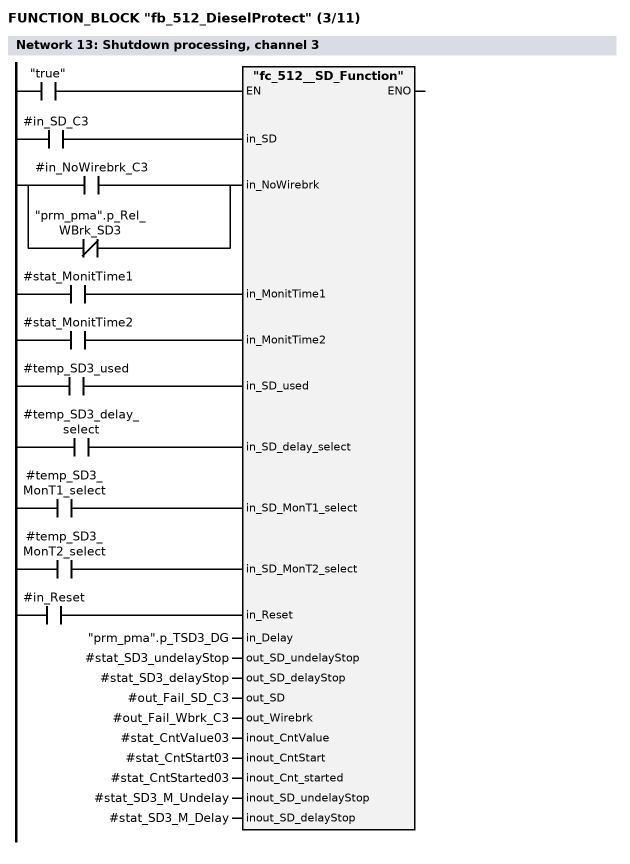
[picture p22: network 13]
      U     #in_SD_C3;
      =     L      6.0;
      BLD   103;
      U(    ;
      O     #in_NoWirebrk_C3;
      ON    "prm_pma".p_Rel_WBrk_SD3;
      )     ;
      =     L      6.1;
      BLD   103;
      U     #stat_MonitTime1;
      =     L      6.2;
      BLD   103;
      U     #stat_MonitTime2;
      =     L      6.3;
      BLD   103;
      U     #temp_SD3_used;
      =     L      6.4;
      BLD   103;
      U     #temp_SD3_delay_select;
      =     L      6.5;
      BLD   103;
      U     #temp_SD3_MonT1_select;
      =     L      6.6;
      BLD   103;
      U     #temp_SD3_MonT2_select;
      =     L      6.7;
      BLD   103;
      U     #in_Reset;
      =     L      7.0;
      BLD   103;
      U     "true";
      SPBNB _011;
      CALL "fc_512__SD_Function" (
           in_SD                    := L      6.0,
           in_NoWirebrk             := L      6.1,
           in_MonitTime1            := L      6.2,
           in_MonitTime2            := L      6.3,
           in_SD_used               := L      6.4,
           in_SD_delay_select       := L      6.5,
           in_SD_MonT1_select       := L      6.6,
           in_SD_MonT2_select       := L      6.7,
           in_Reset                 := L      7.0,
           in_Delay                 := "prm_pma".p_TSD3_DG,
           out_SD_undelayStop       := #stat_SD3_undelayStop,
           out_SD_delayStop         := #stat_SD3_delayStop,
           out_SD                   := #out_Fail_SD_C3,
           out_Wirebrk              := #out_Fail_Wbrk_C3,
           inout_CntValue           := #stat_CntValue03,
           inout_CntStart           := #stat_CntStart03,
           inout_Cnt_started        := #stat_CntStarted03,
           inout_SD_undelayStop     := #stat_SD3_M_Undelay,
           inout_SD_delayStop       := #stat_SD3_M_Delay);
_011: NOP   0;
NETWORK
TITLE =Shutdown processing, channel 4

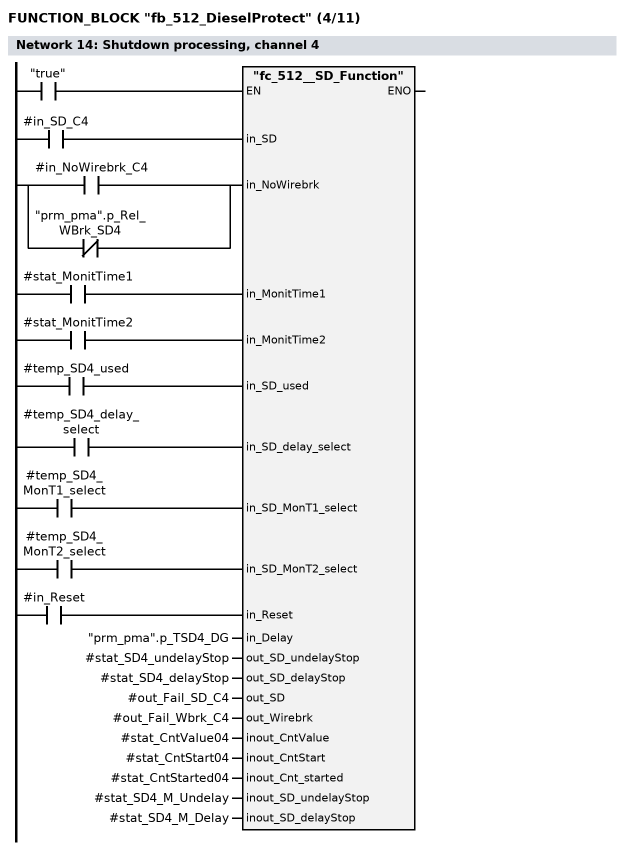
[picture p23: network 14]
      U     #in_SD_C4;
      =     L      6.0;
      BLD   103;
      U(    ;
      O     #in_NoWirebrk_C4;
      ON    "prm_pma".p_Rel_WBrk_SD4;
      )     ;
      =     L      6.1;
      BLD   103;
      U     #stat_MonitTime1;
      =     L      6.2;
      BLD   103;
      U     #stat_MonitTime2;
      =     L      6.3;
      BLD   103;
      U     #temp_SD4_used;
      =     L      6.4;
      BLD   103;
      U     #temp_SD4_delay_select;
      =     L      6.5;
      BLD   103;
      U     #temp_SD4_MonT1_select;
      =     L      6.6;
      BLD   103;
      U     #temp_SD4_MonT2_select;
      =     L      6.7;
      BLD   103;
      U     #in_Reset;
      =     L      7.0;
      BLD   103;
      U     "true";
      SPBNB _012;
      CALL "fc_512__SD_Function" (
           in_SD                    := L      6.0,
           in_NoWirebrk             := L      6.1,
           in_MonitTime1            := L      6.2,
           in_MonitTime2            := L      6.3,
           in_SD_used               := L      6.4,
           in_SD_delay_select       := L      6.5,
           in_SD_MonT1_select       := L      6.6,
           in_SD_MonT2_select       := L      6.7,
           in_Reset                 := L      7.0,
           in_Delay                 := "prm_pma".p_TSD4_DG,
           out_SD_undelayStop       := #stat_SD4_undelayStop,
           out_SD_delayStop         := #stat_SD4_delayStop,
           out_SD                   := #out_Fail_SD_C4,
           out_Wirebrk              := #out_Fail_Wbrk_C4,
           inout_CntValue           := #stat_CntValue04,
           inout_CntStart           := #stat_CntStart04,
           inout_Cnt_started        := #stat_CntStarted04,
           inout_SD_undelayStop     := #stat_SD4_M_Undelay,
           inout_SD_delayStop       := #stat_SD4_M_Delay);
_012: NOP   0;
NETWORK
TITLE =Shutdown processing, channel 5

      U     #in_SD_C5;
      =     L      6.0;
      BLD   103;
      U(    ;
      O     #in_NoWirebrk_C5;
      ON    "prm_pma".p_Rel_WBrk_SD5;
      )     ;
      =     L      6.1;
      BLD   103;
      U     #stat_MonitTime1;
      =     L      6.2;
      BLD   103;
      U     #stat_MonitTime2;
      =     L      6.3;
      BLD   103;
      U     #temp_SD5_used;
      =     L      6.4;
      BLD   103;
      U     #temp_SD5_delay_select;
      =     L      6.5;
      BLD   103;
      U     #temp_SD5_MonT1_select;
      =     L      6.6;
      BLD   103;
      U     #temp_SD5_MonT2_select;
      =     L      6.7;
      BLD   103;
      U     #in_Reset;
      =     L      7.0;
      BLD   103;
      U     "true";
      SPBNB _013;
      CALL "fc_512__SD_Function" (
           in_SD                    := L      6.0,
           in_NoWirebrk             := L      6.1,
           in_MonitTime1            := L      6.2,
           in_MonitTime2            := L      6.3,
           in_SD_used               := L      6.4,
           in_SD_delay_select       := L      6.5,
           in_SD_MonT1_select       := L      6.6,
           in_SD_MonT2_select       := L      6.7,
           in_Reset                 := L      7.0,
           in_Delay                 := "prm_pma".p_TSD5_DG,
           out_SD_undelayStop       := #stat_SD5_undelayStop,
           out_SD_delayStop         := #stat_SD5_delayStop,
           out_SD                   := #out_Fail_SD_C5,
           out_Wirebrk              := #out_Fail_Wbrk_C5,
           inout_CntValue           := #stat_CntValue05,
           inout_CntStart           := #stat_CntStart05,
           inout_Cnt_started        := #stat_CntStarted05,
           inout_SD_undelayStop     := #stat_SD5_M_Undelay,
           inout_SD_delayStop       := #stat_SD5_M_Delay);
_013: NOP   0;
NETWORK
TITLE =Shutdown processing, channel 6

      U     #in_SD_C6;
      =     L      6.0;
      BLD   103;
      U(    ;
      O     #in_NoWirebrk_C6;
      ON    "prm_pma".p_Rel_WBrk_SD6;
      )     ;
      =     L      6.1;
      BLD   103;
      U     #stat_MonitTime1;
      =     L      6.2;
      BLD   103;
      U     #stat_MonitTime2;
      =     L      6.3;
      BLD   103;
      U     #temp_SD6_used;
      =     L      6.4;
      BLD   103;
      U     #temp_SD6_delay_select;
      =     L      6.5;
      BLD   103;
      U     #temp_SD6_MonT1_select;
      =     L      6.6;
      BLD   103;
      U     #temp_SD6_MonT2_select;
      =     L      6.7;
      BLD   103;
      U     #in_Reset;
      =     L      7.0;
      BLD   103;
      U     "true";
      SPBNB _017;
      CALL "fc_512__SD_Function" (
           in_SD                    := L      6.0,
           in_NoWirebrk             := L      6.1,
           in_MonitTime1            := L      6.2,
           in_MonitTime2            := L      6.3,
           in_SD_used               := L      6.4,
           in_SD_delay_select       := L      6.5,
           in_SD_MonT1_select       := L      6.6,
           in_SD_MonT2_select       := L      6.7,
           in_Reset                 := L      7.0,
           in_Delay                 := "prm_pma".p_TSD6_DG,
           out_SD_undelayStop       := #stat_SD6_undelayStop,
           out_SD_delayStop         := #stat_SD6_delayStop,
           out_SD                   := #out_Fail_SD_C6,
           out_Wirebrk              := #out_Fail_Wbrk_C6,
           inout_CntValue           := #stat_CntValue06,
           inout_CntStart           := #stat_CntStart06,
           inout_Cnt_started        := #stat_CntStarted06,
           inout_SD_undelayStop     := #stat_SD6_M_Undelay,
           inout_SD_delayStop       := #stat_SD6_M_Delay);
_017: NOP   0;
NETWORK
TITLE =Shutdown processing, channel 7

      U     #in_SD_C7;
      =     L      6.0;
      BLD   103;
      U(    ;
      O     #in_NoWirebrk_C7;
      ON    "prm_pma".p_Rel_WBrk_SD7;
      )     ;
      =     L      6.1;
      BLD   103;
      U     #stat_MonitTime1;
      =     L      6.2;
      BLD   103;
      U     #stat_MonitTime2;
      =     L      6.3;
      BLD   103;
      U     #temp_SD7_used;
      =     L      6.4;
      BLD   103;
      U     #temp_SD7_delay_select;
      =     L      6.5;
      BLD   103;
      U     #temp_SD7_MonT1_select;
      =     L      6.6;
      BLD   103;
      U     #temp_SD7_MonT2_select;
      =     L      6.7;
      BLD   103;
      U     #in_Reset;
      =     L      7.0;
      BLD   103;
      U     "true";
      SPBNB _01b;
      CALL "fc_512__SD_Function" (
           in_SD                    := L      6.0,
           in_NoWirebrk             := L      6.1,
           in_MonitTime1            := L      6.2,
           in_MonitTime2            := L      6.3,
           in_SD_used               := L      6.4,
           in_SD_delay_select       := L      6.5,
           in_SD_MonT1_select       := L      6.6,
           in_SD_MonT2_select       := L      6.7,
           in_Reset                 := L      7.0,
           in_Delay                 := "prm_pma".p_TSD7_DG,
           out_SD_undelayStop       := #stat_SD7_undelayStop,
           out_SD_delayStop         := #stat_SD7_delayStop,
           out_SD                   := #out_Fail_SD_C7,
           out_Wirebrk              := #out_Fail_Wbrk_C7,
           inout_CntValue           := #stat_CntValue07,
           inout_CntStart           := #stat_CntStart07,
           inout_Cnt_started        := #stat_CntStarted07,
           inout_SD_undelayStop     := #stat_SD7_M_Undelay,
           inout_SD_delayStop       := #stat_SD7_M_Delay);
_01b: NOP   0;
NETWORK
TITLE =Shutdown processing, channel 8

      U     #in_SD_C8;
      =     L      6.0;
      BLD   103;
      U(    ;
      O     #in_NoWirebrk_C8;
      ON    "prm_pma".p_Rel_WBrk_SD8;
      )     ;
      =     L      6.1;
      BLD   103;
      U     #stat_MonitTime1;
      =     L      6.2;
      BLD   103;
      U     #stat_MonitTime2;
      =     L      6.3;
      BLD   103;
      U     #temp_SD8_used;
      =     L      6.4;
      BLD   103;
      U     #temp_SD8_delay_select;
      =     L      6.5;
      BLD   103;
      U     #temp_SD8_MonT1_select;
      =     L      6.6;
      BLD   103;
      U     #temp_SD8_MonT2_select;
      =     L      6.7;
      BLD   103;
      U     #in_Reset;
      =     L      7.0;
      BLD   103;
      U     "true";
      SPBNB _01c;
      CALL "fc_512__SD_Function" (
           in_SD                    := L      6.0,
           in_NoWirebrk             := L      6.1,
           in_MonitTime1            := L      6.2,
           in_MonitTime2            := L      6.3,
           in_SD_used               := L      6.4,
           in_SD_delay_select       := L      6.5,
           in_SD_MonT1_select       := L      6.6,
           in_SD_MonT2_select       := L      6.7,
           in_Reset                 := L      7.0,
           in_Delay                 := "prm_pma".p_TSD8_DG,
           out_SD_undelayStop       := #stat_SD8_undelayStop,
           out_SD_delayStop         := #stat_SD8_delayStop,
           out_SD                   := #out_Fail_SD_C8,
           out_Wirebrk              := #out_Fail_Wbrk_C8,
           inout_CntValue           := #stat_CntValue08,
           inout_CntStart           := #stat_CntStart08,
           inout_Cnt_started        := #stat_CntStarted08,
           inout_SD_undelayStop     := #stat_SD8_M_Undelay,
           inout_SD_delayStop       := #stat_SD8_M_Delay);
_01c: NOP   0;
NETWORK
TITLE =SD3...8 undelayed shutdown

      U(    ;
      O     #stat_SD3_undelayStop;
      O     #stat_SD4_undelayStop;
      O     #stat_SD5_undelayStop;
      O     #stat_SD6_undelayStop;
      O     #stat_SD7_undelayStop;
      O     #stat_SD8_undelayStop;
      )     ;
      U(    ;
      ON    #in_EG_Set;
      O     #stat_Harb_Feedb_Mode;
      )     ;
      =     #stat_UndelStop_SD3_8;
NETWORK
TITLE =SD1...8 undelayed shutdown

      O     #stat_SD1_undelayStop;
      O     #stat_SD2_undelayStop;
      O     #stat_UndelStop_SD3_8;
      =     #stat_UndelayStop;
NETWORK
TITLE =SD1...8 delayed shutdown

      O     #stat_SD1_delayStop;
      O     #stat_SD2_delayStop;
      O     ;
      U(    ;
      O     #stat_SD3_delayStop;
      O     #stat_SD4_delayStop;
      O     #stat_SD5_delayStop;
      O     #stat_SD6_delayStop;
      O     #stat_SD7_delayStop;
      O     #stat_SD8_delayStop;
      )     ;
      U(    ;
      ON    #in_EG_Set;
      O     #stat_Harb_Feedb_Mode;
      )     ;
      =     #stat_DelayStop;
NETWORK
TITLE =Emergency stop push-button
//Emergency stop push-button is monitored only if DG is running!
      U     #in_Reset;
      UN    #stat_DGRunning;
      R     #stat_EmergStop_Man;
      U     #in_DI_EmergSt_PB;
      U     #stat_DGRunning;
      S     #stat_EmergStop_Man;
      U     #stat_EmergStop_Man;
      =     #out_Fail_EmStpMan;
NETWORK
TITLE =Request for standby generator start
//Standby start request only if DG is running!
      U(    ;
      O     #stat_UndelayStop;
      O     #stat_DelayStop;
      O     #in_DI_Prealarm;
      )     ;
      UN    #in_EG_Set;
      U     #temp_Auto;
      U     #stat_DGRunning;
      =     #out_StandbyStart;
NETWORK
TITLE =Request for 2nd standby generator start in case of shutdown
//Standby start request only if DG is running!
      U(    ;
      O     #stat_UndelayStop;
      O     #stat_DelayStop;
      )     ;
      U     "prm_pma".p_SD_StdbySt2;
      UN    #in_EG_Set;
      U     #temp_Auto;
      U     #stat_DGRunning;
      =     #out_StandbyStart2;
NETWORK
TITLE =Undelayed stop command (to FB47)

      O     #stat_UndelayStop;
      O     #stat_EmergStop_Man;
      =     #out_UndelayStop;
NETWORK
TITLE =Delayed stop command (to FB47)
//The function of "Prealarm" is depending on the parameter "prm_pma".p_Prealarm:
//0=Set will be stopped, 1=Set remains running
//Evtl. kein Stopp, wenn Standby-Aggregat nicht startet?
//Evtl. nur im Auto-Betrieb?
      O     #stat_DelayStop;
      O     ;
      U     #in_DI_Prealarm;
      UN    "prm_pma".p_Prealarm;
      U     #temp_Auto;
      =     #out_DelayStop;
NETWORK
TITLE =Emergency stop command (to FB47)

      U     #stat_UndelayStop;
      UN    "prm_pma".p_EmergStp_OvSpeed;
      O     ;
      U     #stat_SD1_undelayStop;
      U     "prm_pma".p_EmergStp_OvSpeed;
      O     #stat_EmergStop_Man;
      =     #out_EmergencyStop;
NETWORK
TITLE =Blocking of generator set by fault
//Blocking of generator set by fault only, if the failure also causes an
//undelayed
//stop. The reset of this blocking is possible only in standstill. In case of a
//delayed stop the the blocking command is given together with the stop command
//to
//the diesel engine.
      O     #stat_UndelayStop;
      O     #stat_EmergStop_Man;
      =     #out_Blocking;
NETWORK
TITLE =Forced change over from automatic to semi automatic mode
//The blocking of the generator set always causes a change over from "Automatic"
//to "Semi automatic" mode. There may be some additional conditions, which cause
//a
//changeover to "Semi automatic" mode, but no blocking.
      O     #out_Blocking;
      O     #stat_DelayStop;
      =     #out_ChOver_Semi;
NETWORK
TITLE =Generator breaker Off command
//For shutdown channel 1 (Overspeed) it can be selected, if the generator breaker
//shall be tripped immediately or after the input signal "Overspeed" has
//disappeared. (Of course undelayed stop must been selected for this channel,
//which is normal for overspeed.) All other undelayed shutdown channels cause an
//immediate trip of the generator breaker.
//
//If delayed stop is selected, the generator breaker is tripped at that time,
//when a stop command is given to the diesel engine. This is made in FB 47.
      U     #stat_SD1_undelayStop;
      U(    ;
      ON    #in_SD_C1;
      ON    "prm_pma".p_GenBrkOff_OvSpeed;
      )     ;
      O     #stat_SD2_undelayStop;
      O     #stat_UndelStop_SD3_8;
      O     #stat_EmergStop_Man;
      =     #out_GenBrkOff;
NETWORK
TITLE =Indication: Sensor failure shutdown channel 2
//With this function the sensor for SD channel 2 ("Low lubrication oil pressure")
//can be monitored. Normally this sensor signal goes from "Normal pressure" ("0")
//to "Low pressure" ("1") some time after the engine has stopped. If the signal
//remains in "0", there may be a failure of the sensor.
//
//This function can not be used, when the sensor is connected to a separate
//safety
//system and not directly to the PMA71. In this case the safety system will give
//a
//"1" only when there is a shutdown.
      UN    #in_SD_C2;
      U     #in_NoWirebrk_C2;
      UN    #stat_DGRunning;
      UN    #in_Prelub;
      U     "prm_pma".p_Sensor_SD2;
      =     L      6.0;
      BLD   103;
      U     "true";
      SPBNB _01d;
      CALL "fc_h1_CntState16" (
           CntTyp                   := 'D',
           CntStart                 := L      6.0,
           CntValue                 := "sys_freeCnt16_100ms",
           CntOffset                := "prm_pma".p_TSensor_SD2,
           CntRun                   := #out_Fail_Sensor_SD2,
           puls_CntStart            := #stat_CntStart11,
           Cnt_started              := #stat_CntStarted11,
           mem_CntValue             := #stat_CntValue11);
_01d: NOP   0;
NETWORK
TITLE =Indication: Prealarm

      U     #in_Reset;
      R     #out_Fail_Prealarm;
      U     #in_DI_Prealarm;
      S     #out_Fail_Prealarm;
      NOP   0;
END_FUNCTION_BLOCK




DATA_BLOCK "DPrtct"
TITLE =
VERSION : 0.0

"fb_512_DieselProtect"
BEGIN
   in_act_mode := B#16#0;
   in_EG_Set := FALSE;
   in_EG_Harbour_Mode := FALSE;
   in_EG_PowerFb_Mode := FALSE;
   in_SD_C1 := FALSE;
   in_SD_C2 := FALSE;
   in_SD_C3 := FALSE;
   in_SD_C4 := FALSE;
   in_SD_C5 := FALSE;
   in_SD_C6 := FALSE;
   in_SD_C7 := FALSE;
   in_SD_C8 := FALSE;
   in_NoWirebrk_C1 := FALSE;
   in_NoWirebrk_C2 := FALSE;
   in_NoWirebrk_C3 := FALSE;
   in_NoWirebrk_C4 := FALSE;
   in_NoWirebrk_C5 := FALSE;
   in_NoWirebrk_C6 := FALSE;
   in_NoWirebrk_C7 := FALSE;
   in_NoWirebrk_C8 := FALSE;
   in_DI_EmergSt_PB := FALSE;
   in_DI_Prealarm := FALSE;
   in_DI_FB_GenBrk_Off := FALSE;
   in_DI_IgnitionSpeed := FALSE;
   in_GenVolt_avail := FALSE;
   in_Prelub := FALSE;
   in_Stop_Command := FALSE;
   in_Reset := FALSE;
   out_StandbyStart := FALSE;
   out_StandbyStart2 := FALSE;
   out_UndelayStop := FALSE;
   out_DelayStop := FALSE;
   out_EmergencyStop := FALSE;
   out_Blocking := FALSE;
   out_ChOver_Semi := FALSE;
   out_GenBrkOff := FALSE;
   out_MonitTime1 := FALSE;
   out_MonitTime2 := FALSE;
   out_Fail_SD_C1 := FALSE;
   out_Fail_SD_C2 := FALSE;
   out_Fail_SD_C3 := FALSE;
   out_Fail_SD_C4 := FALSE;
   out_Fail_SD_C5 := FALSE;
   out_Fail_SD_C6 := FALSE;
   out_Fail_SD_C7 := FALSE;
   out_Fail_SD_C8 := FALSE;
   out_Fail_Wbrk_C1 := FALSE;
   out_Fail_Wbrk_C2 := FALSE;
   out_Fail_Wbrk_C3 := FALSE;
   out_Fail_Wbrk_C4 := FALSE;
   out_Fail_Wbrk_C5 := FALSE;
   out_Fail_Wbrk_C6 := FALSE;
   out_Fail_Wbrk_C7 := FALSE;
   out_Fail_Wbrk_C8 := FALSE;
   out_Fail_EmStpMan := FALSE;
   out_Fail_Prealarm := FALSE;
   out_Fail_Sensor_SD2 := FALSE;
   stat_CntValue01 := 0;
   stat_CntValue02 := 0;
   stat_CntValue03 := 0;
   stat_CntValue04 := 0;
   stat_CntValue05 := 0;
   stat_CntValue06 := 0;
   stat_CntValue07 := 0;
   stat_CntValue08 := 0;
   stat_CntValue09 := 0;
   stat_CntValue10 := 0;
   stat_CntValue11 := 0;
   stat_CntStart01 := FALSE;
   stat_CntStarted01 := FALSE;
   stat_CntStart02 := FALSE;
   stat_CntStarted02 := FALSE;
   stat_CntStart03 := FALSE;
   stat_CntStarted03 := FALSE;
   stat_CntStart04 := FALSE;
   stat_CntStarted04 := FALSE;
   stat_CntStart05 := FALSE;
   stat_CntStarted05 := FALSE;
   stat_CntStart06 := FALSE;
   stat_CntStarted06 := FALSE;
   stat_CntStart07 := FALSE;
   stat_CntStarted07 := FALSE;
   stat_CntStart08 := FALSE;
   stat_CntStarted08 := FALSE;
   stat_CntStart09 := FALSE;
   stat_CntStarted09 := FALSE;
   stat_CntStart10 := FALSE;
   stat_CntStarted10 := FALSE;
   stat_CntStart11 := FALSE;
   stat_CntStarted11 := FALSE;
   stat_SD1_M_Undelay := FALSE;
   stat_SD1_M_Delay := FALSE;
   stat_SD2_M_Undelay := FALSE;
   stat_SD2_M_Delay := FALSE;
   stat_SD3_M_Undelay := FALSE;
   stat_SD3_M_Delay := FALSE;
   stat_SD4_M_Undelay := FALSE;
   stat_SD4_M_Delay := FALSE;
   stat_SD5_M_Undelay := FALSE;
   stat_SD5_M_Delay := FALSE;
   stat_SD6_M_Undelay := FALSE;
   stat_SD6_M_Delay := FALSE;
   stat_SD7_M_Undelay := FALSE;
   stat_SD7_M_Delay := FALSE;
   stat_SD8_M_Undelay := FALSE;
   stat_SD8_M_Delay := FALSE;
   stat_DGRunning := FALSE;
   stat_MonitTime1 := FALSE;
   stat_MonitTime2 := FALSE;
   stat_Harb_Feedb_Mode := FALSE;
   stat_SD1_undelayStop := FALSE;
   stat_SD2_undelayStop := FALSE;
   stat_SD3_undelayStop := FALSE;
   stat_SD4_undelayStop := FALSE;
   stat_SD5_undelayStop := FALSE;
   stat_SD6_undelayStop := FALSE;
   stat_SD7_undelayStop := FALSE;
   stat_SD8_undelayStop := FALSE;
   stat_SD1_delayStop := FALSE;
   stat_SD2_delayStop := FALSE;
   stat_SD3_delayStop := FALSE;
   stat_SD4_delayStop := FALSE;
   stat_SD5_delayStop := FALSE;
   stat_SD6_delayStop := FALSE;
   stat_SD7_delayStop := FALSE;
   stat_SD8_delayStop := FALSE;
   stat_UndelayStop := FALSE;
   stat_DelayStop := FALSE;
   stat_EmergStop_Man := FALSE;
   stat_UndelStop_SD3_8 := FALSE;
END_DATA_BLOCK

FUNCTION "fc_PMA_DG" : VOID
TITLE =PMA call for diesel generator (DG) function
//
//                                                                               !
//- Start/ stop sequence (FB53)
//- Generator protection (FB56)
//- Diesel engine shutdown functions (FB57)
//- Start/ stop diesel (FB47)
//- Close/open generator breaker (FB51)
//
//version!date    !author !change_segm!change_description
//-------+--------+-------+-----------+-------------------------------
// 1.4   !28.02.00!Bauch  ! ---       ! vaild version
// 1.5   !26.04.00!Kahle  ! 36        ! parameter "shore conn.off": new signal
//       !        !       !           !            "shore disconn"
// 1.6   !09.05.00!Bauch  ! 31        ! add.parameter: stop_command
//       !        !       ! 21        ! delayed short circuit
// 1.7   !17.07.00!Bauch  ! 22,24,26  ! add.signal "IN_brk_clse"
// 1.8   !27.09.00!Kahle  ! 36        ! Input "shore off" release CB
//       !        !       ! 5         ! Selector 'local'
//       !        !       ! 20        ! SC delay time adjustable
//       !        !       ! 37        ! corr.current breaker 3WN6
// 1.9   !05.12.00!Kahle  ! 36        ! ext.blocking -->in_norm_Pos
//       !        !       ! 51,52     ! indication isochronous mode
// 1.10  !03.01.01!Kahle  ! 33        ! add.signal "IN_ratedSpeed",
//       !        !       !           ! "IN_LuboilPress_ok"
// 1.11  !09.01.01!Kahle  ! 33,36     ! new parameter "o53_GenBrk_trip"
//       !        !       ! 42        ! Standby start if at least on set o.k.
// 1.12  !15.01.00!Bauch  ! 36        ! Signal "Rated speed" added for
//       !        !       !           ! "Gen. breaker external release"
//       !        !       !           ! No generator breaker Off with
//       !        !       !           ! pushbutton "Manual Off"
// 1.13  !08.03.01!Kahle  ! 21        ! add.signal "underload shutdown possible"
//       !        !       !           ! new ind 'overcurr', 'overload'
//       !        !       !           ! if ext.block & no ign.speed->protc block
//       !        !       ! 33        ! ext.blocking diesel start
//       !        !       ! 36        ! ext.blocking also in test position active
//       !        !       ! 36,55,59  ! new ind. "not ready (generator breaker)"
//       !        !       ! 40        ! Alarm"blackout expected" selectable
//       !        !       ! 5         ! new para."ext DG start" ->DG start
//       !        !       ! 36        ! new para."ext GenBrk off" ->CB off
//       !        !       !           ! new para." "MEM".o53_extBlockDG"
// 1.14  !12.03.01!Kahle  ! 21        ! new para."diff.protect.warning"
//       !        !       ! 36,55,59  ! corr.signal "not ready GB"
//       !        !       ! 23,25,27  ! Latch for indication "uness.cons.1-3"
// 1.15  !02.01.02!Kahle  ! 21        ! new para."in_GENOP_OvCurr_3"
//       !        !       ! 23,25,27  ! Blocking of alarms "Unessential consumer"
//       !        !       ! 34,37,    ! Unloading before Gen. brk Off, if at least
//       !        !       ! new 19    ! 1 other gen. is on line, instead of 1
//       !        !       !           ! other gen. is in Auto on line
//       !        !       ! 42        ! GenAvail or GenRun & CBready ->Standby
AUTHOR : Bauch
FAMILY : PMA71
NAME : CallPMA
VERSION : 1.15


VAR_TEMP
  temp_OM_Local : BOOL ;	//Active operation mode: Local
  temp_OM_Semi_OP : BOOL ;	//Active operation mode: Semi automatic OP
  temp_OM_Auto_OP : BOOL ;	//Active operation mode: Automatic OP
  temp_OM_Semi_MMI : BOOL ;	//Active operation mode: Semi automatic MMI
  temp_OM_Auto_MMI : BOOL ;	//Active operation mode: Automatic MMI
  temp_OM_Test : BOOL ;	//Active operation mode: Test (EG only)
  temp_Reserve_006 : BOOL ;	//Reserved (Transfer Byte --> Bit)
  temp_Reserve_007 : BOOL ;	//Reserved (Transfer Byte --> Bit)
  temp_Auto : BOOL ;	//Active operation mode: Auto
  temp_Semi : BOOL ;	//Active operation mode: Semi automatic
  temp_ScratchFlag : BOOL ;	//Scratch flag
  temp_013 : BOOL ;	//Spare
  temp_014 : BOOL ;	//Spare
  temp_015 : BOOL ;	//Spare
  temp_016 : BOOL ;	//Spare
  temp_017 : BOOL ;	//Spare
  temp_GEN_I_L1 : INT ;	//Generator current L1 (in 100.00% of nominal value)
  temp_GEN_I_L2 : INT ;	//Generator current L1 (in 100.00% of nominal value)
  temp_GEN_I_L3 : INT ;	//Generator current L1 (in 100.00% of nominal value)
  temp_GEN_P_SUM : INT ;	//Generator active load (in 100.00% of nominal value)
  temp_BUS_f : INT ;	//Bus bar frequency (in 100.00% of nominal value)
  temp_BUS_U_L1L2 : INT ;	//Bus bar voltage L1/L2 (in 100.00% of nominal value)
  temp_BUS_U_L2L3 : INT ;	//Bus bar voltage L2/L3 (in 100.00% of nominal value)
  temp_BUS_U_L3L1 : INT ;	//Bus bar voltage L3/L1 (in 100.00% of nominal value)
  temp_GEN_U_L1L2 : INT ;	//Generator voltage L1/L2 (in 100.00% of nominal value)
  temp_GEN_U_L2L3 : INT ;	//Generator voltage L2/L3 (in 100.00% of nominal value)
  temp_GEN_U_L3L1 : INT ;	//Generator voltage L3/L1 (in 100.00% of nominal value)
  temp_Indication2_FB47 : INT ;	//Indication number, line 2, from FB47
  temp_Indication2_FB51 : INT ;	//Indication number, line 2, from FB51
  temp_Uness1_Off_Comm : BOOL ;	//From FB56: Unessential consumers 1 Off command
  temp_Uness2_Off_Comm : BOOL ;	//From FB56: Unessential consumers 2 Off command
  temp_Uness3_Off_Comm : BOOL ;	//From FB56: Unessential consumers 3 Off command
  temp_Fail_Overcurr : BOOL ;	//From FB56: Failure "Trip of generator breaker by overcurrent"
  temp_Fail_RevPower : BOOL ;	//From FB56: Failure "Reverse power"
  temp_DO_GenBrk_Cmd_Off : BOOL ;	//Generator breaker OFF command on DO
  temp_IN_brk_prepared : BOOL ;	//Generator beaker is ready for closing
  temp_AutoStop : BOOL ;	//Generator set stop in automatic mode (deloading, GBoff, DGstop)
  temp_DelayStopAct : BOOL ;	//Delay stop is activing
  temp_Rel_UnderlShd : BOOL ;	//Release of underload shutdown
  temp_Rel_EngineContr : BOOL ;	//Release of engine controller
  temp_GenBrk_rdy : BOOL ;	//Generator breaker is ready for close
  temp_alarmBrkTrip : BOOL ;	//Alarm "generator breaker tripped"
  temp_GenNo_onbus : INT ;	//Number of generator which are on busbar
END_VAR
BEGIN
NETWORK
TITLE =Active operation mode (Transfer Byte --> Bit)

      L     "MEM".o51_mode_bin;
      T     LB     0;
NETWORK
TITLE =Adapting the hardware inputs to the current hardware
//Digital input E 0.7 used for another function.
      NOP   0;

//IN_brk_opn not available
      UN    "prm_pma".p_noBrkOffSign;
      SPB   in_2;
      UN    "IN_brk_clse";
      =     "IN_brk_opn";

//IN_MSB_Auto not available
in_2: UN    "prm_pma".p_noMSB_Auto;
      SPB   in_3;
      =     "IN_MSB_Auto";

//IN_shore_opn not available
in_3: UN    "prm_pma".p_noShoreOff;
      SPB   in_4;
      =     "IN_shore_opn";

in_4: NOP   0;
NETWORK
TITLE =Operation mode: Automatic

      O     #temp_OM_Auto_OP;
      O     #temp_OM_Auto_MMI;
      =     #temp_Auto;
NETWORK
TITLE =Operation mode: Semi automatic

      O     #temp_OM_Semi_OP;
      O     #temp_OM_Semi_MMI;
      =     #temp_Semi;
NETWORK
TITLE =Gen. set start/stop, gen. breaker ON/OFF, load balancing ON
//In case of blackout the start command for the standby set is coming from the
//own
//generator set ("MEM".o511_req_Ustrt), in all other cases it is coming from
//another generator set ("MEM".o515R_c_reqStrt). The start command is only
//working with the release for a standby start ("MEM".o52_stdby_1st).
//
//The same applies for the start of a second standby set (if selected).
//
//There is no standby start or blackout start of a SG.
      U     "MEM".o53_Gen_Available;
      =     L     32.0;
      BLD   103;
      U(    ;
      O     "I_MMI_SR".c_Dstrt;
      O     ;
      U     "IN_LocalPB_Start";
      U(    ;
      O     "IN_LocalSw_Local";
      O     "prm_pma".p_noLocalSwtch;
      )     ;
      )     ;
      =     L     32.1;
      BLD   103;
      U(    ;
      O     "I_MMI_SR".c_Dstp;
      O     ;
      U     "IN_LocalPB_Stop";
      U(    ;
      O     "IN_LocalSw_Local";
      O     "prm_pma".p_noLocalSwtch;
      )     ;
      )     ;
      =     L     32.2;
      BLD   103;
      U     "I_MMI_SR".c_genBrk_opn;
      =     L     32.3;
      BLD   103;
      U(    ;
      O     "I_MMI_SR".c_Ustrt;
      O     "MEM".o515R_c_strtSet;
      O     "MEM".o53_ExtStrtCmd;
      )     ;
      =     L     32.4;
      BLD   103;
      U     "I_MMI_SR".c_Ustp;
      =     L     32.5;
      BLD   103;
      U     "MEM".o513_i_PBstpPos;
      =     L     32.6;
      BLD   103;
      U(    ;
      O     "MEM".o515R_c_reqStrt;
      O     "MEM".o511_Blackout;
      )     ;
      =     L     32.7;
      BLD   103;
      U     "MEM".o52_stdby_1st;
      =     L     33.0;
      BLD   103;
      U(    ;
      O     "MEM".o515R_c_req2Strt;
      O     ;
      U     "MEM".o511_Blackout;
      U     "prm_pma".p_Blackout_StdbySt2;
      )     ;
      =     L     33.1;
      BLD   103;
      U     "MEM".o52_stdby_2nd;
      =     L     33.2;
      BLD   103;
      U     "MEM".o511_Underload_Shd;
      =     L     33.3;
      BLD   103;
      U     "IN_brk_clse";
      =     L     33.4;
      BLD   103;
      U     "IN_brk_opn";
      =     L     33.5;
      BLD   103;
      U     "IN_IgnitSpeed";
      =     L     33.6;
      BLD   103;
      U     "MEM".o511_GenVolt_avail;
      =     L     33.7;
      BLD   103;
      U     "MEM".o513_i_isochron;
      UN    "MEM".o513_i_Backup;
      =     L     34.0;
      BLD   103;
      U     "I_MMI_SR".c_rst_alm;
      =     L     34.1;
      BLD   103;
      U     "true";
      SPBNB _007;
      CALL "fb_59_GenSet" , "startU" (
           in_act_mode              := "MEM".o51_mode_bin,
           in_Set_Avail             := L     32.0,
           in_PB_Start              := L     32.1,
           in_PB_Stop               := L     32.2,
           in_PB_GB_Open            := L     32.3,
           in_PB_Start_Auto         := L     32.4,
           in_PB_Stop_Auto          := L     32.5,
           in_PB_StopRelease        := L     32.6,
           in_Standby_Start         := L     32.7,
           in_Standby_Release       := L     33.0,
           in_Standby_Start2        := L     33.1,
           in_Standby_Release2      := L     33.2,
           in_Stop_Auto             := L     33.3,
           in_DI_FB_GenBrk_On       := L     33.4,
           in_DI_FB_GenBrk_Off      := L     33.5,
           in_DI_FireSpeed          := L     33.6,
           in_GenVolt               := L     33.7,
           in_lockCtrl              := L     34.0,
           in_reset                 := L     34.1,
           out_Start_Comm           := "MEM".o59_Start_Comm,
           out_Stop_Comm            := "MEM".o59_Stop_Comm,
           out_StopAuto             := #temp_AutoStop,
           out_GenBrk_Off           := "MEM".o59_GenBrk_Off,
           out_LoadBal_On           := "MEM".o59_LoadBal_On,
           out_fail_noStopPos       := "I_MMI_SR".e_StopNotPermit);
_007: NOP   0;
NETWORK
TITLE =Scaling of generator current L1

      U     "true";
      SPBNB _00a;
      CALL "int_norm100INT" (
           in_Value                 := "I_prtcSR".a_I_L1,
           in_Norm                  := "prm_pma".p_nomCurr,
           out_Value                := #temp_GEN_I_L1);
_00a: NOP   0;
NETWORK
TITLE =Scaling of generator current L2

      U     "true";
      SPBNB _00f;
      CALL "int_norm100INT" (
           in_Value                 := "I_prtcSR".a_I_L2,
           in_Norm                  := "prm_pma".p_nomCurr,
           out_Value                := #temp_GEN_I_L2);
_00f: NOP   0;
NETWORK
TITLE =Scaling of generator current L3

      U     "true";
      SPBNB _012;
      CALL "int_norm100INT" (
           in_Value                 := "I_prtcSR".a_I_L3,
           in_Norm                  := "prm_pma".p_nomCurr,
           out_Value                := #temp_GEN_I_L3);
_012: NOP   0;
NETWORK
TITLE =Scaling of generator active load

      U     "true";
      SPBNB _015;
      CALL "int_norm100INT" (
           in_Value                 := "I_prtcSR".a_P_SUM,
           in_Norm                  := "prm_pma".p_NomPower_Gen,
           out_Value                := #temp_GEN_P_SUM);
_015: NOP   0;
NETWORK
TITLE =Active load --> Instrument in MSB
//O P T I O N
      U     "true";
      SPBNB _016;
      CALL "fc_opt1_AO" ;
_016: NOP   0;
NETWORK
TITLE =Scaling of busbar frequency

      U     "true";
      SPBNB _017;
      CALL "int_norm100INT" (
           in_Value                 := "I_prtcSR".a_FREQ_BUS,
           in_Norm                  := "prm_pma".p_nomFreq,
           out_Value                := #temp_BUS_f);
_017: NOP   0;
NETWORK
TITLE =Scaling of busbar voltage L1/L2

      U     "true";
      SPBNB _01b;
      CALL "int_norm100INT" (
           in_Value                 := "I_prtcSR".a_BUS_L1_L2,
           in_Norm                  := "prm_pma".p_nomVolt,
           out_Value                := #temp_BUS_U_L1L2);
_01b: NOP   0;
NETWORK
TITLE =Scaling of busbar voltage L2/L3

      U     "true";
      SPBNB _01f;
      CALL "int_norm100INT" (
           in_Value                 := "I_prtcSR".a_BUS_L2_L3,
           in_Norm                  := "prm_pma".p_nomVolt,
           out_Value                := #temp_BUS_U_L2L3);
_01f: NOP   0;
NETWORK
TITLE =Scaling of busbar voltage L3/L1

      U     "true";
      SPBNB _028;
      CALL "int_norm100INT" (
           in_Value                 := "I_prtcSR".a_BUS_L1_L3,
           in_Norm                  := "prm_pma".p_nomVolt,
           out_Value                := #temp_BUS_U_L3L1);
_028: NOP   0;
NETWORK
TITLE =Scaling of generator voltage L1/L2

      U     "true";
      SPBNB _029;
      CALL "int_norm100INT" (
           in_Value                 := "I_prtcSR".a_GEN_L1_L2,
           in_Norm                  := "prm_pma".p_nomVolt,
           out_Value                := #temp_GEN_U_L1L2);
_029: NOP   0;
NETWORK
TITLE =Scaling of generator voltage L2/L3

      U     "true";
      SPBNB _02a;
      CALL "int_norm100INT" (
           in_Value                 := "I_prtcSR".a_GEN_L2_L3,
           in_Norm                  := "prm_pma".p_nomVolt,
           out_Value                := #temp_GEN_U_L2L3);
_02a: NOP   0;
NETWORK
TITLE =Scaling of generator voltage L3/L1

      U     "true";
      SPBNB _02b;
      CALL "int_norm100INT" (
           in_Value                 := "I_prtcSR".a_GEN_L1_L3,
           in_Norm                  := "prm_pma".p_nomVolt,
           out_Value                := #temp_GEN_U_L3L1);
_02b: NOP   0;
NETWORK
TITLE =Alarm "generator set in underload -no shutdown- "

      U     "MEM".o513_i_SGonly;
      U     "prm_pma".p_NoUndS_SGonly;
      U     "MEM".o52_SD;
      U     "prm_pma".p_Underl_Rel;
      U     "MEM".o511_Underload_Limit;
      U(    ;
      O     #temp_OM_Auto_OP;
      O     #temp_OM_Auto_MMI;
      )     ;
      =     "I_MMI_SR".e_LoadTooLow;
NETWORK
TITLE =Number of generators on busbar
//p#38.2 = f_brk_clse
      U     "true";
      SPBNB _02f;
      CALL "fc_h20_NoParticip" (
           IN_bytebit               := P#38.2,
           IN_release               := "MEM".o51_actCfg,
           OUT_Signal_No            := #temp_GenNo_onbus,
           OUT_GenSetOnbus          := MW   250);
_02f: NOP   0;
NETWORK
TITLE =Release of underload shutdown

      U     "prm_pma".p_Underl_Rel;
      U     "MEM".o52_SD;
      U(    ;
      UN    "MEM".o513_c_UBLmin;
      UN    "MEM".o513_c_UBLmode;
      ON    "prm_pma".p_UBL_ShdPos;
      )     ;
      UN    "MEM".o515R_c_lockShtdwn;
      U(    ;
      U     "MEM".o513_i_SGonly;
      U     "prm_pma".p_NoUndS_SGonly;
      NOT   ;
      )     ;
      =     #temp_Rel_UnderlShd;
NETWORK
TITLE =Short circuit signal will be delayed

      U     "MEM".o515R_f_i_SC;
      L     "prm_pma".p_dlyT_SC;
      SE    "dlyT_ShortOther";
NETWORK
TITLE =Generator protection (FB56)
//Digital input E1.1 used for another function.
      U     "false";
      =     L     32.0;
      BLD   103;
      U     "false";
      =     L     32.1;
      BLD   103;
      U     "false";
      =     L     32.2;
      BLD   103;
      U     "IN_black_1";
      =     L     32.3;
      BLD   103;
      U     "IN_non_black_2";
      =     L     32.4;
      BLD   103;
      U     "IN_IgnitSpeed";
      =     L     32.5;
      BLD   103;
      U     "IN_brk_clse";
      U(    ;
      ON    "MEM".o53_extBlockDG;
      O     "IN_IgnitSpeed";
      O     "I_MMI_SR".e_IgnSp_RelGenBrk_Fail;
      )     ;
      =     L     32.6;
      BLD   103;
      U     "false";
      =     L     32.7;
      BLD   103;
      U     "IN_diffPrtct_warn";
      =     L     33.0;
      BLD   103;
      U     "IN_diffPrtct_trip";
      =     L     33.1;
      BLD   103;
      U     "IN_Brk_Tripped";
      =     L     33.2;
      BLD   103;
      U     "I_prtcSR".e_I_SC_VER;
      =     L     33.3;
      BLD   103;
      U     "I_prtcSR".e_I_GW4VER;
      =     L     33.4;
      BLD   103;
      U     "I_prtcSR".e_P_GW1VER;
      =     L     33.5;
      BLD   103;
      U     "I_prtcSR".e_I_GW1VER;
      =     L     33.6;
      BLD   103;
      U     "I_prtcSR".e_I_GW2VER;
      =     L     33.7;
      BLD   103;
      U     "I_prtcSR".e_I_GW3VER;
      =     L     34.0;
      BLD   103;
      U     "I_prtcSR".e_I_GW31VER;
      =     L     34.1;
      BLD   103;
      U     #temp_Rel_UnderlShd;
      =     L     34.2;
      BLD   103;
      U     "MEM".o513_i_PBstpPos;
      =     L     34.3;
      BLD   103;
      U     "dlyT_ShortOther";
      =     L     34.4;
      BLD   103;
      U     "I_MMI_SR".c_rst_alm;
      =     L     34.5;
      BLD   103;
      U     "true";
      SPBNB _032;
      CALL "fb_511_GenProtect" , "GPrtct" (
           in_GEN_I_L1              := #temp_GEN_I_L1,
           in_GEN_I_L2              := #temp_GEN_I_L2,
           in_GEN_I_L3              := #temp_GEN_I_L3,
           in_GEN_P_SUM             := #temp_GEN_P_SUM,
           in_BUS_f                 := #temp_BUS_f,
           in_BUS_U_L1L2            := #temp_BUS_U_L1L2,
           in_BUS_U_L2L3            := #temp_BUS_U_L2L3,
           in_BUS_U_L3L1            := #temp_BUS_U_L3L1,
           in_GEN_U_L1L2            := #temp_GEN_U_L1L2,
           in_GEN_U_L2L3            := #temp_GEN_U_L2L3,
           in_GEN_U_L3L1            := #temp_GEN_U_L3L1,
           in_Nmb_Generator         := "MEM".o513_NoActGen,
           in_act_mode              := "MEM".o51_mode_bin,
           in_EG_Set                := L     32.0,
           in_EG_Harbour_Mode       := L     32.1,
           in_EG_PowerFb_Mode       := L     32.2,
           in_DI_Blackout           := L     32.3,
           in_DI_BusbarVolt         := L     32.4,
           in_DI_FireSpeedRelGenBrk := L     32.5,
           in_DI_FB_GenBrk_On       := L     32.6,
           in_DI_Wind_Overtemp      := L     32.7,
           in_DiffProt_warn         := L     33.0,
           in_DiffProt_Trip         := L     33.1,
           in_Overc_ShortC_extern   := L     33.2,
           in_GENOP_ShortCircuit    := L     33.3,
           in_GENOP_OvCurr_trip     := L     33.4,
           in_GENOP_ReversePower    := L     33.5,
           in_GENOP_OvCurr_1_dly_1  := L     33.6,
           in_GENOP_OvCurr_1_dly_2  := L     33.7,
           in_GENOP_OvCurr_1_dly_3  := L     34.0,
           in_GENOP_OvCurr_3        := L     34.1,
           in_Rel_UnderlShd         := L     34.2,
           in_UnderShd_pos          := L     34.3,
           in_ShortCirc_OtherGen    := L     34.4,
           in_Reset                 := L     34.5,
           out_Blackout             := "MEM".o511_Blackout,
           out_BusVolt_avail        := "MEM".o511_BusVolt_avail,
           out_GenVolt_avail        := "MEM".o511_GenVolt_avail,
           out_StandbyStart         := "MEM".o511_req_Ustrt,
           out_Uness1_Off           := #temp_Uness1_Off_Comm,
           out_Uness2_Off           := #temp_Uness2_Off_Comm,
           out_Uness3_Off           := #temp_Uness3_Off_Comm,
           out_GenBrk_Off           := "MEM".o511_GenBrk_Off,
           out_ShortCirc_OtherGen   := "MEM".o515_f_i_SC,
           out_VoltContr_Off        := "OUT_Gen_Deexitation",
           out_UndelayStop          := "MEM".o511_UndelayStop,
           out_Blocking             := "MEM".o511_Blocking,
           out_ChOver_Semi          := "MEM".o511_ChOver_Semi,
           out_ChOver_Blackout      := "MEM".o511_ChOver_Blackout,
           out_Underload_Limit      := "MEM".o511_Underload_Limit,
           out_Underload_Shd        := "MEM".o511_Underload_Shd,
           out_Fail_Busbar          := "I_MMI_SR".e_BusBar_Monit_Fail,
           out_Fail_Current         := "I_MMI_SR".e_Curr_Monit_Fail,
           out_Fail_Overcurr        := "I_MMI_SR".e_GenBrkOff_Prtct,
           out_Fail_RevPower        := "I_MMI_SR".e_RevPower,
           out_Fail_overcurrent     := "I_MMI_SR".e_warnCurrent1,
           out_Fail_overload        := "I_MMI_SR".e_warnload1,
           out_Fail_Underfrequ1     := "I_MMI_SR".e_Underfrequ1,
           out_Fail_Underfrequ2     := "I_MMI_SR".e_Underfrequ2,
           out_Fail_Underfrequ3     := "I_MMI_SR".e_Underfrequ3,
           out_Fail_Overfrequ       := "I_MMI_SR".e_Overfrequ,
           out_Fail_Undervolt1      := "I_MMI_SR".e_Undervolt1,
           out_Fail_Undervolt2      := "I_MMI_SR".e_Undervolt2,
           out_Fail_Overvolt1       := "I_MMI_SR".e_Overvolt1,
           out_Fail_Overvolt2       := "I_MMI_SR".e_Overvolt2,




           out_Fail_ShortCirc_Other := "I_MMI_SR".e_ShCirc_OtherSet,
           out_Fail_DiffProt_Warn   := "I_MMI_SR".e_warnDiffProtect,
           out_Fail_DiffProt_Trip   := "I_MMI_SR".e_DiffProt_Trip,
           out_Fail_Wind_Overtemp   := "I_MMI_SR".e_WindOvertemp,
           out_Fail_Underload       := "I_MMI_SR".e_UnderlShd_Ann,

           out_Fail_Underl_SD       := "I_MMI_SR".e_UnderlShd_Act,
           out_Spare_1              := #temp_ScratchFlag,
           out_Spare_2              := #temp_ScratchFlag);

_032: NOP   0;
NETWORK
TITLE =To GENOP71: Unessential consumers 1 Off command
//Additional Off command from Thruster control
      O     #temp_Uness1_Off_Comm;
      O     "MEM".o512_uness_1;
      O     ;
      U     "MEM".o512_UndelayStop;
      U     "IN_brk_clse";
      =     "I_prtcSR".c_GW1_OUT_ON;
NETWORK
TITLE =To MMI: Unessential consumers 1 tripped

      U     "I_prtcSR".e_GW1_OUT_ON;
      UN    "prm_pma".p_Prtc_uness1_lock;
      S     "I_MMI_SR".e_NEconsu1off;
      U     "I_MMI_SR".c_rst_alm;
      R     "I_MMI_SR".e_NEconsu1off;
      NOP   0;
NETWORK
TITLE =To GENOP71: Unessential consumers 2 Off command
//Additional Off command from Thruster control
      O     #temp_Uness2_Off_Comm;
      O     "MEM".o512_uness_2;
      O     ;
      U     "MEM".o512_UndelayStop;
      U     "IN_brk_clse";
      =     "I_prtcSR".c_GW2_OUT_ON;
NETWORK
TITLE =To MMI: Unessential consumers 2 tripped

      U     "I_prtcSR".e_GW2_OUT_ON;
      UN    "prm_pma".p_Prtc_uness2_lock;
      S     "I_MMI_SR".e_NEconsu2off;
      U     "I_MMI_SR".c_rst_alm;
      R     "I_MMI_SR".e_NEconsu2off;
      NOP   0;
NETWORK
TITLE =To GENOP71: Unessential consumers 3 Off command
//Additional Off command from Thruster control
      O     #temp_Uness3_Off_Comm;
      O     "MEM".o512_uness_3;
      O     ;
      U     "MEM".o512_UndelayStop;
      U     "IN_brk_clse";
      =     "I_prtcSR".c_GW3_OUT_ON;
NETWORK
TITLE =To MMI: Unessential consumers 3 tripped

      U     "I_prtcSR".e_GW3_OUT_ON;
      UN    "prm_pma".p_Prtc_uness3_lock;
      S     "I_MMI_SR".e_NEconsu3off;
      U     "I_MMI_SR".c_rst_alm;
      R     "I_MMI_SR".e_NEconsu3off;
      NOP   0;
NETWORK
TITLE =To MMI: Blackout

      U     "MEM".o511_Blackout;
      =     "I_MMI_SR".e_blackout;
      =     "MEM".o515_f_blackout;
NETWORK
TITLE =To MMI: Short circuit (own set)

      U     "MEM".o515_f_i_SC;
      =     "I_MMI_SR".e_i_SC;
NETWORK
TITLE =To MMI: Failure of differential protection device
//Digital input E1.2 used for another function.
      UN    "IN_diffPrtct_ok";
      U     "prm_pma".p_DiffProt_Avail;
      =     "I_MMI_SR".e_DiffProt_Failure;
NETWORK
TITLE =Diesel protection (FB57)

      U     "false";
      =     L     32.0;
      BLD   103;
      U     "false";
      =     L     32.1;
      BLD   103;
      U     "false";
      =     L     32.2;
      BLD   103;
      U     "IN_SD_1_ovsp";
      =     L     32.3;
      BLD   103;
      U     "IN_SD_2_lubP";
      =     L     32.4;
      BLD   103;
      U     "IN_SD_3_cwT";
      =     L     32.5;
      BLD   103;
      U     "IN_SD_4_MajAlarm";
      =     L     32.6;
      BLD   103;
      U     "IN_SD_5";
      =     L     32.7;
      BLD   103;
      U     "IN_SD_6";
      =     L     33.0;
      BLD   103;
      U     "IN_SD_7";
      =     L     33.1;
      BLD   103;
      U     "IN_SD_8";
      =     L     33.2;
      BLD   103;
      U     "IN_wirebrk_in1";
      =     L     33.3;
      BLD   103;
      U     "IN_wirebrk_in2";
      =     L     33.4;
      BLD   103;
      U     "IN_wirebrk_in3";
      =     L     33.5;
      BLD   103;
      U     "IN_wirebrk_in4";
      =     L     33.6;
      BLD   103;
      U     "IN_wirebrk_in5";
      =     L     33.7;
      BLD   103;
      U     "IN_wirebrk_in6";
      =     L     34.0;
      BLD   103;
      U     "IN_wirebrk_in7";
      =     L     34.1;
      BLD   103;
      U     "IN_wirebrk_in8";
      =     L     34.2;
      BLD   103;
      U     "IN_PB_EmergStp";
      =     L     34.3;
      BLD   103;
      U     "false";
      =     L     34.4;
      BLD   103;
      U     "IN_brk_opn";
      =     L     34.5;
      BLD   103;
      U     "IN_IgnitSpeed";
      =     L     34.6;
      BLD   103;
      U     "MEM".o511_GenVolt_avail;
      =     L     34.7;
      BLD   103;
      U     "OUT_PreLub";
      =     L     35.0;
      BLD   103;
      U     "OUT_stpVv";
      =     L     35.1;
      BLD   103;
      U     "I_MMI_SR".c_rst_alm;
      =     L     35.2;
      BLD   103;
      U     "true";
      SPBNB _037;
      CALL "fb_512_DieselProtect" , "DPrtct" (
           in_act_mode              := "MEM".o51_mode_bin,
           in_EG_Set                := L     32.0,
           in_EG_Harbour_Mode       := L     32.1,
           in_EG_PowerFb_Mode       := L     32.2,
           in_SD_C1                 := L     32.3,
           in_SD_C2                 := L     32.4,
           in_SD_C3                 := L     32.5,
           in_SD_C4                 := L     32.6,
           in_SD_C5                 := L     32.7,
           in_SD_C6                 := L     33.0,
           in_SD_C7                 := L     33.1,
           in_SD_C8                 := L     33.2,
           in_NoWirebrk_C1          := L     33.3,
           in_NoWirebrk_C2          := L     33.4,
           in_NoWirebrk_C3          := L     33.5,
           in_NoWirebrk_C4          := L     33.6,
           in_NoWirebrk_C5          := L     33.7,
           in_NoWirebrk_C6          := L     34.0,
           in_NoWirebrk_C7          := L     34.1,
           in_NoWirebrk_C8          := L     34.2,
           in_DI_EmergSt_PB         := L     34.3,
           in_DI_Prealarm           := L     34.4,
           in_DI_FB_GenBrk_Off      := L     34.5,
           in_DI_IgnitionSpeed      := L     34.6,
           in_GenVolt_avail         := L     34.7,
           in_Prelub                := L     35.0,
           in_Stop_Command          := L     35.1,
           in_Reset                 := L     35.2,
           out_StandbyStart         := "MEM".o512_req_Ustrt,
           out_StandbyStart2        := "MEM".o512_req_Ustrt2,
           out_UndelayStop          := "MEM".o512_UndelayStop,
           out_DelayStop            := "MEM".o512_DelayStop,
           out_EmergencyStop        := "MEM".o512_EmergencyStop,
           out_Blocking             := "MEM".o512_Blocking,
           out_ChOver_Semi          := "MEM".o512_Chover_Semi,
           out_GenBrkOff            := "MEM".o512_genBrk_off,
           out_MonitTime1           := "MEM".o512_MonitTime1,
           out_MonitTime2           := "MEM".o512_MonitTime2,
           out_Fail_SD_C1           := "I_MMI_SR".e_SD_C1,
           out_Fail_SD_C2           := "I_MMI_SR".e_SD_C2,
           out_Fail_SD_C3           := "I_MMI_SR".e_SD_C3,
           out_Fail_SD_C4           := "I_MMI_SR".e_SD_C4,
           out_Fail_SD_C5           := "I_MMI_SR".e_SD_C5,
           out_Fail_SD_C6           := "I_MMI_SR".e_SD_C6,
           out_Fail_SD_C7           := "I_MMI_SR".e_SD_C7,
           out_Fail_SD_C8           := "I_MMI_SR".e_SD_C8,
           out_Fail_Wbrk_C1         := "I_MMI_SR".e_wirebrk_C1,
           out_Fail_Wbrk_C2         := "I_MMI_SR".e_wirebrk_C2,
           out_Fail_Wbrk_C3         := "I_MMI_SR".e_wirebrk_C3,
           out_Fail_Wbrk_C4         := "I_MMI_SR".e_wirebrk_C4,
           out_Fail_Wbrk_C5         := "I_MMI_SR".e_wirebrk_C5,
           out_Fail_Wbrk_C6         := "I_MMI_SR".e_wirebrk_C6,
           out_Fail_Wbrk_C7         := "I_MMI_SR".e_wirebrk_C7,
           out_Fail_Wbrk_C8         := "I_MMI_SR".e_wirebrk_C8,
           out_Fail_EmStpMan        := "I_MMI_SR".e_EMStpMan,
           out_Fail_Prealarm        := "I_MMI_SR".e_Prealarm,
           out_Fail_Sensor_SD2      := "I_MMI_SR".e_Sensor_SD_C2);
_037: NOP   0;
NETWORK
TITLE =Diesel engine blocked from local switch

      U     "prm_pma".p_local_remote;
      UN    "IN_LocalSw_Remote";
      UN    "IN_LocalSw_Local";
      =     "MEM".o53_Blocked_Switch;
NETWORK
TITLE =Control of Diesel engine (FB47)

      U     "false";
      =     L     32.0;
      BLD   103;
      U     "MEM".o59_Start_Comm;
      =     L     32.1;
      BLD   103;
      U     "MEM".o59_Stop_Comm;
      =     L     32.2;
      BLD   103;
      U(    ;
      O     "MEM".o512_UndelayStop;
      O     "MEM".o511_UndelayStop;
      O     "MEM".o57_UndelayStop;
      )     ;
      =     L     32.3;
      BLD   103;
      U(    ;
      O     "MEM".o512_DelayStop;
      O     "MEM".o57_DelayStop;
      )     ;
      =     L     32.4;
      BLD   103;
      U     "MEM".o512_EmergencyStop;
      =     L     32.5;
      BLD   103;
      U     "MEM".o511_Underload_Limit;
      =     L     32.6;
      BLD   103;
      U     #temp_AutoStop;
      =     L     32.7;
      BLD   103;
      U     "MEM".o515R_c_shoreOn;
      UN    "prm_pma".p_BrkOpnShC;
      =     L     33.0;
      BLD   103;
      U     "MEM".o513_c_stpPunder;
      =     L     33.1;
      BLD   103;
      U     "IN_brk_clse";
      =     L     33.2;
      BLD   103;
      U     "IN_brk_opn";
      =     L     33.3;
      BLD   103;
      U     "IN_IgnitSpeed";
      =     L     33.4;
      BLD   103;
      U     "IN_RatedSpeed";
      =     L     33.5;
      BLD   103;
      U     "MEM".o511_GenVolt_avail;
      =     L     33.6;
      BLD   103;
      U     "MEM".o512_MonitTime1;
      =     L     33.7;
      BLD   103;
      U(    ;
      O     "MEM".o53_Blocked_Switch;
      ON    "IN_D_noLock";
      O     "MEM".o51_blockD_OP;
      O     "MEM".o53_extBlockDG;
      )     ;
      =     L     34.0;
      BLD   103;
      U(    ;
      O     "MEM".o511_Blocking;
      O     "MEM".o512_Blocking;
      O     "MEM".o57_Blocking;
      )     ;
      =     L     34.1;
      BLD   103;
      U     "MEM".o51_blockF_reset;
      =     L     34.2;
      BLD   103;
      U     "IN_LowPreLubOil";
      =     L     34.3;
      BLD   103;
      U     "IN_PrelubPress_OK";
      =     L     34.4;
      BLD   103;
      U     "MEM".o52_stdby_1st;
      =     L     34.5;
      BLD   103;
      U     "MEM".o511_Blackout;
      =     L     34.6;
      BLD   103;
      U     "IN_wirebrk_out1";
      =     L     34.7;
      BLD   103;
      U     "IN_wirebrk_out2";
      =     L     35.0;
      BLD   103;
      U     "IN_wirebrk_out3";
      =     L     35.1;
      BLD   103;
      U     "IN_wirebrk_out4";
      =     L     35.2;
      BLD   103;
      U     "I_MMI_SR".c_rst_alm;
      =     L     35.3;
      BLD   103;
      U     "true";
      SPBNB _03a;
      CALL "fb_53_startstopDiesel" , "startstopD" (
           in_Nmb_Gen_LoadSh        := #temp_GenNo_onbus,
           in_act_mode              := "MEM".o51_mode_bin,
           in_EG_set                := L     32.0,
           in_DG_Start              := L     32.1,
           in_DG_Stop               := L     32.2,
           in_UndelayStop           := L     32.3,
           in_DelayStop             := L     32.4,
           in_EmergencyStop         := L     32.5,
           in_Underload_Limit       := L     32.6,
           in_Autom_Stop            := L     32.7,
           in_Shore_Stop            := L     33.0,
           in_DG_Load_Off           := L     33.1,
           in_DI_GenBrk_FB_On       := L     33.2,
           in_DI_GenBrk_FB_Off      := L     33.3,
           in_DI_IgnitionSpeed      := L     33.4,
           in_DI_RatedSpeed         := L     33.5,
           in_GenVolt_avail         := L     33.6,
           in_MonitTime1            := L     33.7,
           in_DG_Block_Engine       := L     34.0,
           in_DG_Blocking           := L     34.1,
           in_Blocking_Reset        := L     34.2,
           in_LubPress              := L     34.3,
           in_PrelubPress           := L     34.4,
           in_DRelStdby             := L     34.5,
           in_Blackout              := L     34.6,
           in_NoWireBrk_StartValve  := L     34.7,
           in_NoWireBrk_StopValve   := L     35.0,
           in_NoWireBrk_EmStopValve := L     35.1,
           in_NoWireBrk_SupprValve  := L     35.2,
           in_Reset                 := L     35.3,
           out_Operat_Status        := #temp_Indication2_FB47,
           out_StartValve           := "OUT_strtVv",
           out_StopValve            := "OUT_stpVv",
           out_EmStpValve           := "OUT_emergVv",
           out_SupprValve           := "OUT_supprVv",
           out_Release_SpeedContr   := "OUT_rel_SPC",
           out_PreLub               := "OUT_PreLub",
           out_PreHeat              := "OUT_heating",
           out_SlowTurn             := M    255.0,
           out_StandbyStart         := "MEM".o53_req_Ustrt,
           out_ChOver_Semi          := "MEM".o53_ChOver_Semi,
           out_GenBrkOff_LoadRed    := "MEM".o53_GenBrkOff_LoadRed,
           out_GenBrkOff            := "MEM".o53_GenBrkOff,
           out_GenBrkTrip           := "MEM".o53_GenBrkTrip,
           out_DG_Blocked_Fault     := "MEM".o53_Blocked_Fault,
           out_DG_Blocked           := "MEM".o53_Gen_Blocked,
           out_DG_Starting          := "MEM".o53_Gen_Starting,
           out_DG_Runn              := "MEM".o53_Gen_Running,
           out_DG_Avail             := "MEM".o53_Gen_Available,
           out_Fail_Start           := "I_MMI_SR".e_Start_Fail,
           out_Fail_Stop            := "I_MMI_SR".e_Stop_Fail,
           out_Fail_IgnSpd          := "I_MMI_SR".e_IgnSp_RelGenBrk_Fail,
           out_Fail_GenVolt         := "I_MMI_SR".e_GenVolt_Fail,
           out_Fail_UndelayStop     := M    255.0,
           out_Fail_DelayStop       := #temp_DelayStopAct,
           out_Fail_DieselEngine    := "I_MMI_SR".e_DiesEngine_Fail,
           out_Fail_PrelubOil       := "I_MMI_SR".e_Block_PreLubOil,
           out_Fail_WBr_StartValve  := "I_MMI_SR".e_wirebrk_V1,
           out_Fail_WBr_StopValve   := "I_MMI_SR".e_wirebrk_V2,
           out_Fail_WBr_EmStopValve := "I_MMI_SR".e_wirebrk_V3,
           out_Fail_WBr_SuppValve   := "I_MMI_SR".e_wirebrk_V4);
_03a: NOP   0;
NETWORK
TITLE =To MMI: Generator set is ready for start

      U     "MEM".o53_Gen_Available;
      =     "I_MMI_SR".i_Gen_RdyStrt;
NETWORK
TITLE =Differences between 3VF and 3WN6 Breaker

      L     2; //parameter =3VF
      L     "prm_pma".p_GenBrk_Type;
      ==I   ;
      SPB   O3VF;
      L     1;
      ==I   ;
      SPB   O3W1; //parameter =3WN1
      L     0;
      L     "prm_pma".p_GenBrk_Type;
      ==I   ;
      SPB   O3W6; //parameter =3WN6
      SPA   brk;
//Current Breaker =3VF
O3VF: SET   ;
      =     #temp_IN_brk_prepared;
      SPA   brk;
//Current Breaker =3WN1
O3W1: NOP   0;
      SPA   brk;
//Current Breaker =3WN6
O3W6: U     "IN_brk_prepared";
      =     #temp_IN_brk_prepared;

brk:  NOP   0;
NETWORK
TITLE =Control of generator breaker (FB51)

      U     "MEM".o513_c_stpPunder;
      =     L     32.0;
      BLD   103;
      U     "false";
      =     L     32.1;
      BLD   103;
      U     "MEM".o511_Blackout;
      =     L     32.2;
      BLD   103;
      U     "MEM".o515_ownBlock;
      =     L     32.3;
      BLD   103;
      U     "MEM".o515_simulLockErr;
      =     L     32.4;
      BLD   103;
      U     "MEM".o515_simulLockAct;
      =     L     32.5;
      BLD   103;
      U     "MEM".o53_Gen_Running;
      =     L     32.6;
      BLD   103;
      U     "OUT_stpVv";
      =     L     32.7;
      BLD   103;
      U     "MEM".o53_GenBrkOff_LoadRed;
      =     L     33.0;
      BLD   103;
      U(    ;
      O     "MEM".o53_GenBrkOff;
      O     "MEM".o512_genBrk_off;
      ON    "IN_PB_GenBrk_Off";
      O     "IN_LocalPB_Stop";
      O(    ;
      U     "MEM".o515R_c_shoreOn;
      FP    "pls_brkOff_ShC";
      U     "prm_pma".p_BrkOpnShC;
      )     ;
      O     "MEM".o57_ExtCBopenCmd;
      )     ;
      =     L     33.1;
      BLD   103;
      U(    ;
      O     "MEM".o511_GenBrk_Off;
      O     "MEM".o53_GenBrkTrip;
      )     ;
      =     L     33.2;
      BLD   103;
      U     "MEM".o511_ChOver_Blackout;
      =     L     33.3;
      BLD   103;
      U     "MEM".o515R_f_rdy_swtchOn;
      =     L     33.4;
      BLD   103;
      U(    ;
      U     "IN_shore_opn";
      UN    "MEM".o515R_f_shoreMode;
      O     "MEM".o515R_f_shore_dis;
      )     ;
      =     L     33.5;
      BLD   103;
      U(    ;
      O     #temp_IN_brk_prepared;
      O     ;
      U     "MEM".o515R_f_shoreExp;
      U     "prm_pma".p_GBprepExpShore;
      )     ;
      =     L     33.6;
      BLD   103;
      U     "false";
      =     L     33.7;
      BLD   103;
      U     "IN_brk_normPos";
      UN    "MEM".o57_extBlock;
      =     L     34.0;
      BLD   103;
      U     "IN_brk_testPos";
      UN    "MEM".o57_extBlock;
      =     L     34.1;
      BLD   103;
      U     "IN_brk_clse";
      =     L     34.2;
      BLD   103;
      U     "IN_brk_opn";
      =     L     34.3;
      BLD   103;
      U     "I_prtcSR".i_BR_ON;
      =     L     34.4;
      BLD   103;
      U     "MEM".o53_Gen_Running;
      U     "IN_RatedSpeed";
      U     "MEM".o511_GenVolt_avail;
      UN    "OUT_stpVv";
      =     L     34.5;
      BLD   103;
      U     "MEM".o53_extBlockDG;
      =     L     34.6;
      BLD   103;
      U     "false";
      =     L     34.7;
      BLD   103;
      U     "false";
      =     L     35.0;
      BLD   103;
      U     "false";
      =     L     35.1;
      BLD   103;
      U     "I_MMI_SR".c_genBrk_clse;
      =     L     35.2;
      BLD   103;
      U     "I_MMI_SR".c_genBrk_opn;
      =     L     35.3;
      BLD   103;
      UN    "IN_PB_GenBrk_Off";
      =     L     35.4;
      BLD   103;
      U     "I_MMI_SR".c_rst_alm;
      =     L     35.6;
      BLD   103;
      U     "true";
      SPBNB _03d;
      CALL "fb_57_clseopnBrk" , "clsopnBrk" (
           in_DGLoad_off            := L     32.0,
           in_Nmb_Gen_LoadSh        := #temp_GenNo_onbus,
           in_act_mode              := "MEM".o51_mode_bin,
           in_EG_Set                := L     32.1,
           in_Blackout              := L     32.2,
           in_SimLock_Blocked       := L     32.3,
           in_SimLock_Fault         := L     32.4,
           in_SimLock_Release       := L     32.5,
           in_DGWG_run              := L     32.6,
           in_DGWG_Stop             := L     32.7,
           in_GenBrkOff_LoadRed     := L     33.0,
           in_DGWG_GenBrk_Cmd_Off   := L     33.1,
           in_DGWG_GenBrk_Cmd_Trip  := L     33.2,
           in_ChOver_Blackout       := L     33.3,
           in_Standby_ReadyConn     := L     33.4,
           in_ShoreConn_Off         := L     33.5,
           in_DI_GenBrk_ReadyClose  := L     33.6,
           in_DI_GenBrk_Tripped     := L     33.7,
           in_DI_GenBrk_PosNorm     := L     34.0,
           in_DI_GenBrk_PosTest     := L     34.1,
           in_DI_GenBrk_FB_On       := L     34.2,
           in_DI_GenBrk_FB_Off      := L     34.3,
           in_GENOP_SynCmd_On       := L     34.4,
           in_GenBrk_Ext_Release    := L     34.5,
           in_ext_DG_block          := L     34.6,
           in_EG_GB_Close           := L     34.7,
           in_EG_Cmd_Synchr_On      := L     35.0,
           in_EG_GB_Open            := L     35.1,
           in_PB_GenBrk_Close       := L     35.2,
           in_PB_GenBrk_Open        := L     35.3,
           in_PB_GenBrk_Open_Man    := L     35.4,
           in_Reset                 := L     35.6,
           out_Operat_Status        := #temp_Indication2_FB51,
           out_StandbyStart         := "MEM".o57_req_Ustrt,
           out_SimLock_Request      := "MEM".o515_c_simulLock,
           out_DO_GenBrk_Cmd_Off    := "OUT_GenBrk_opn",
           out_GENOP_GenBrk_Cmd_On  := "I_prtcSR".c_BR_ON,
           out_GENOP_GenBrk_Cmd_Off := "I_prtcSR".c_BR_OFF,
           out_GENOP_SynchRelease   := "I_prtcSR".c_SYN_EN,
           out_GenBrk_Ready         := "I_MMI_SR".i_GenBrk_rdy,
           out_GenBrk_Ready_Standby := "MEM".o57_Brk_Ready_Standby,
           out_GenBrk_Ready_Close   := "MEM".o57_Brk_Ready_Closing,
           out_Brk_Closed_Plausib   := M    255.0,
           out_UndelayStop          := "MEM".o57_UndelayStop,
           out_DelayStop            := "MEM".o57_DelayStop,
           out_LoadReduction        := "MEM".o53_LoadRed,
           out_Blocking             := "MEM".o57_Blocking,
           out_ChOver_Semi          := "MEM".o57_ChOver_Semi,
           out_Fail_Ready           := "I_MMI_SR".e_brk_ready_fail,
           out_Fail_FeedbOn         := "I_MMI_SR".e_brk_on_fail,
           out_Fail_FeedbOff        := "I_MMI_SR".e_brk_off_fail,
           out_Fail_FeedbOffOn      := "I_MMI_SR".e_brk_onOff_fail,
           out_Fail_BrkTrip         := "I_MMI_SR".e_brk_trip,
           out_Fail_SynTime         := "I_MMI_SR".e_SynchrTime_Fail,
           out_Fail_GenFailure      := "MEM".o57_GenBrk_Failure,
           out_Fail_ShoreC_GenBrk   := "I_MMI_SR".e_GenBrk_ShoreConn,
           out_Fail_ChgViaBlack     := "I_MMI_SR".e_Changeov_Blackout);
_03d: NOP   0;
NETWORK
TITLE =Differences between 3VF and 3WN6 Breaker
//Diese Funktion ersetzt durch Funktion im FB51/DB41.DBX148.5.
      L     2; //parameter =3VF
      L     "prm_pma".p_GenBrk_Type;
      ==I   ;
      SPB   _3VF;
      L     1;
      ==I   ;
      SPB   _3W1; //parameter =3WN1
      L     0;
      L     "prm_pma".p_GenBrk_Type;
      ==I   ;
      SPB   _3W6; //parameter =3WN6
      SPA   nxt;
//Current breaker =3VF
_3VF: NOP   0;
      SPA   nxt;
//Current breaker =3WN1
_3W1: NOP   0;
      SPA   nxt;
//Current Breaker =3WN6
_3W6: NOP   0;

nxt:  NOP   0;
NETWORK
TITLE =Signal to DO "Gen. breaker On command"
//For this project the digital output "Gen. breaker On command" has to be
//activated in order to release the On command coming from the GENOP71 (Blackout
//and synchonizing).
      O     "I_prtcSR".c_BR_ON;
      O     "I_prtcSR".c_SYN_EN;
      =     "OUT_GenBrk_cls";
NETWORK
TITLE =To MMI: Failure of simultaneous locking (time exceeded)

      U     "MEM".o515_simulLockErr;
      =     "I_MMI_SR".e_SimLock_Fail;
NETWORK
TITLE =To MMI: Blackout expected

      U     #temp_DelayStopAct;
      UN    "MEM".o515R_f_brk_clse;
      U     "IN_IgnitSpeed";
      U     "prm_pma".p_BlackExp_Alrm;
      =     "I_MMI_SR".e_BlackoutExp;
NETWORK
TITLE =Set is ready for function as standby set

      U(    ;
      O     "MEM".o53_Gen_Available;
      O     "MEM".o53_Gen_Running;
      )     ;
      U     "MEM".o57_Brk_Ready_Standby;
      =     "MEM".o515_f_rdyStandby;
      =     "I_MMI_SR".i_Gen_RdyStrt;
NETWORK
TITLE =Start request to standby set

      U(    ;
      O     "MEM".o511_req_Ustrt;
      O     "MEM".o512_req_Ustrt;
      O     "MEM".o53_req_Ustrt;
      O     "MEM".o57_req_Ustrt;
      )     ;
      U(    ;
      L     "MEM".o52_stdbyNo_1st;
      L     0;
      <>I   ;
      )     ;
      L     S5T#5S;
      SV    "StandbyRequ1_Pulse";
      NOP   0;
      NOP   0;
      NOP   0;
      U     "StandbyRequ1_Pulse";
      =     "MEM".o515_c_reqStrt;
      =     "I_MMI_SR".e_StStart;
NETWORK
TITLE =Start request to 2. standby set
//2nd standby request in case of Blackout (FB56) is going directly to FB53.
      U     "MEM".o512_req_Ustrt2;
      L     S5T#5S;
      SV    "StandbyRequ2_Pulse";
      NOP   0;
      NOP   0;
      NOP   0;
      U     "StandbyRequ2_Pulse";
      =     "MEM".o515_c_req2Strt;
NETWORK
TITLE =Signal to faulty set: New started set ready for connecting
//In some cases, the new started generator set is not synchronized. The change
//over from the faulty generator set to the new started set is made via blackout.
//With this signal the faulty set will trip the generator breaker.
      U     "MEM".o57_Brk_Ready_Closing;
      U     #temp_Auto;
      =     "MEM".o515_f_rdy_swtchOn;
NETWORK
TITLE =Indication line 2, no. 1: "press confirmation"

      L     1;
      U     "MEM".o51_i_pressCnfrm;
      SPB   indi;
NETWORK
TITLE =Indication line 2, no. 22: "blocked by key"

      L     22;
      U     "MEM".o51_blockD_OP;
      SPB   indi;
NETWORK
TITLE =Indication line 2, no. 21: "Starting"

      L     21;
      U     "MEM".o53_Gen_Starting;
      SPB   indi;
NETWORK
TITLE =Indication line 2, no. 20: "Blocked"

      L     20;
      U     "MEM".o53_Gen_Blocked;
      U     "true";
      SPB   indi;
NETWORK
TITLE =Indication line 2, no. 19: "Unbalanced mode, maximum load"

      L     19;
      U     "MEM".o513_c_UBLmode;
      U     #temp_Auto;
      UN    "MEM".o53_Gen_Blocked;
      U     "MEM".o59_LoadBal_On;
      SPB   indi;
NETWORK
TITLE =Indication line 2, no. 18: "Unbalanced mode, minimum load"

      L     18;
      U     "MEM".o513_c_UBLmin;
      U     #temp_Auto;
      UN    "MEM".o53_Gen_Blocked;
      U     "MEM".o59_LoadBal_On;
      SPB   indi;
NETWORK
TITLE =Indication line 2, no. 9: "Isochronous mode"

      L     9;
      U     "IN_brk_clse";
      U     "MEM".o513_i_isochron;
      SPB   indi;


NETWORK
TITLE =Indication line 2, no. 10: "Isochronous mode & next stop"

      L     10;
      U     #temp_Rel_UnderlShd;
      UN    "MEM".o53_Gen_Blocked;
      U     "MEM".o513_i_isochron;
      SPB   indi;


NETWORK
TITLE =Indication line 2, no. 17: "Next stop"

      L     17;
      U     #temp_Rel_UnderlShd;
      U     #temp_Auto;
      UN    "MEM".o53_Gen_Blocked;
      SPB   indi;
NETWORK
TITLE =Indication line 2, no. 16: "Load balance mode On" (Not used)
//This indication is not used in the moment!
//
//"Load balance On" is shown in semi automatic mode only, as load balance can be
//On or Off in semi automatic mode, but it is always On in automatic mode.
      L     16;
      U     "false";
      U     #temp_Semi;
      UN    "MEM".o53_Gen_Blocked;
      SPB   indi;
NETWORK
TITLE =Indication line 2, no. 15: "Set running"
//UN "Load balance On"
//UN "Next stop"    UN "UBL Mode"
      L     15;
      U     "MEM".o53_Gen_Running;
      U(    ;
      O(    ;
      U     "I_MMI_SR".i_GenBrk_rdy;
      U     "MEM".o57_Brk_Ready_Closing;
      )     ;
      O     "IN_brk_clse";
      )     ;
      U(    ;
      U     "prm_pma".p_Underl_Rel;
      U     "MEM".o52_SD;
      U     #temp_Auto;
      NOT   ;
      )     ;
      U(    ;
      U     "MEM".o513_c_UBLmin;
      U     #temp_Auto;
      NOT   ;
      )     ;
      U(    ;
      U     "MEM".o513_c_UBLmode;
      U     #temp_Auto;
      NOT   ;
      )     ;
      UN    "MEM".o53_Gen_Blocked;
      SPB   indi;
NETWORK
TITLE =Indication line 2, no. 14: "Set in 2nd standby"

      L     14;
      U(    ;
      O     "prm_pma".p_Blackout_StdbySt2;
      O     "prm_pma".p_SD_StdbySt2;
      )     ;
      U     "MEM".o52_stdby_2nd;
      UN    "MEM".o53_Gen_Running;
      UN    "MEM".o53_Gen_Blocked;
      SPB   indi;
NETWORK
TITLE =Indication line 2, no. 13: "Set in standby"

      L     13;
      U     "MEM".o52_stdby_1st;
      UN    "MEM".o53_Gen_Running;
      UN    "MEM".o53_Gen_Blocked;
      SPB   indi;
NETWORK
TITLE =Indication line 2, no. 12: "Set ready for start"

      L     12;
      U(    ;
      U     "MEM".o515_f_rdyStandby;
      U     #temp_Auto;
      O     ;
      U     "MEM".o53_Gen_Available;
      U     #temp_Semi;
      )     ;
      UN    "MEM".o53_Gen_Running;
      UN    "MEM".o53_Gen_Blocked;
      SPB   indi;

NETWORK
TITLE =Indication line2,no.11:"Set not ready for start or close CB"

      L     11;
      O(    ;
      U(    ;
      UN    "MEM".o515_f_rdyStandby;
      U     #temp_Auto;
      O     ;
      UN    "MEM".o53_Gen_Available;
      U     #temp_Semi;
      )     ;
      UN    "MEM".o53_Gen_Starting;
      UN    "MEM".o53_Gen_Running;
      UN    "MEM".o53_Gen_Blocked;
      )     ;
      O(    ;
      U     "MEM".o53_Gen_Running;
      U(    ;
      ON    "I_MMI_SR".i_GenBrk_rdy;
      ON    "MEM".o57_Brk_Ready_Closing;
      )     ;
      )     ;
      SPB   indi;
NETWORK
TITLE =Indication line 2, no. 10: "_______" (No indication)
//If there is no indication coming for this line, "10" is delivered.
      L     10;
indi: T     "I_MMI_SR".a_GenSet_stat_var;
NETWORK
TITLE =Transfer of indication line 1, no. 41 (FB51-->DB101)
//During load reduction FB51 will output number "41". This number is transfered
//to OP/MMI and the transfer of the indication number from FB47 is suppressed.
//The
//other time FB51 will output number "30" and the number from FB47 is transfered
//to OP/MMI.
      L     #temp_Indication2_FB51;
      L     41;
      ==I   ;
      SPB   ind;
NETWORK
TITLE =Transfer of indication line 1, no. 44, (FB51-->DB101)
//During synchronizing FB51 will output number "44". This number is transfered
//to OP/MMI and the transfer of the indication number from FB47 (number "37",
//"Running") is suppressed. The other time FB51 will output number "30" and the
//number from FB47 is transfered to OP/MMI.
      L     #temp_Indication2_FB51;
      L     44;
      ==I   ;
      SPB   ind;
NETWORK
TITLE =Transfer of indication no., line 2 (FB47-->DB101)

      L     #temp_Indication2_FB47;
ind:  T     "I_MMI_SR".a_GenSet_stat_ind;
END_FUNCTION













